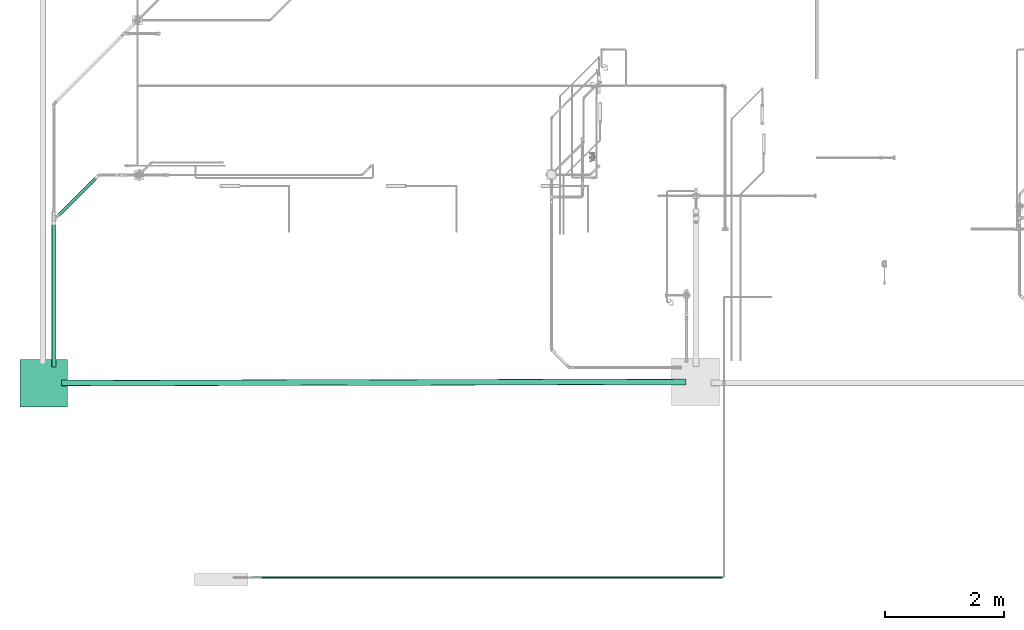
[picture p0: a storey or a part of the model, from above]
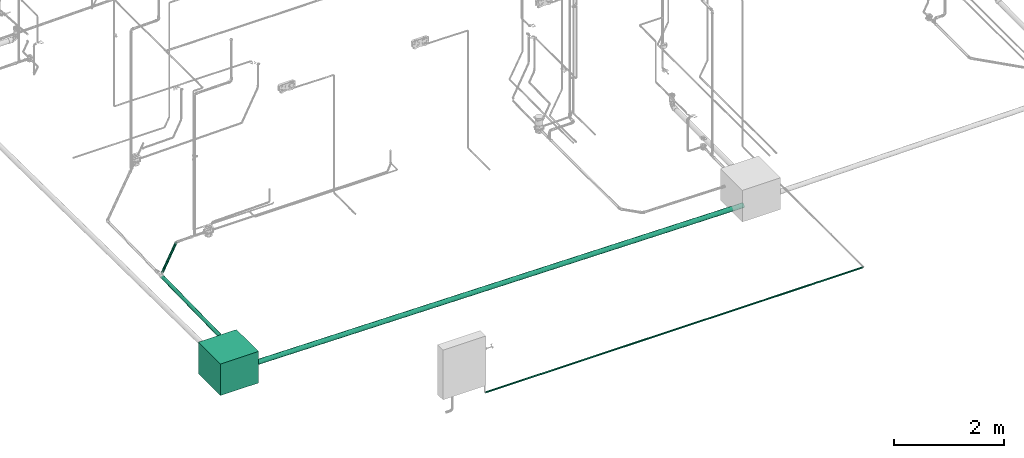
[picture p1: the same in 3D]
Properties of the parts of a building model (IFC2X3), part 1 of 4

# File
Description: ViewDefinition [CoordinationView_V2.0], RevitIdentifiers [VersionGUID: 1a3a2420-27dc-4e76-b48d-279fff6e6c55, NumberOfSaves: 164], CoordinateReference [CoordinateBase: Coordenadas compartilhadas]
File name: 14°43'43.87"S 56°20'14.91"O
Time: 2024-08-28T15:00:30-04:00
Written by: ODA SDAI 22.12
Made in: 23.1.20.70 - Exporter 23.2.5.0 - IU alternativa 23.2.5.0

# IfcProject, 14°43'43.87"S 56°20'14.91"O
LongName: CURSO PROJETO HIDROSSÁNITARIO RESIDENCIAL NO REVIT MEP; Phase: Project Status

# IfcSite, Default
RefLatitude: 42, 12, 46, 799999; RefLongitude: -71, -1, -58, -799999; RefElevation: 0 mm

# IfcBuilding
Pset_BuildingCommon - NumberOfStoreys: 2

# IfcBuildingStorey: Nível:Nivel Rodrigo MEP (2)
Name | LongName | Elevation (mm)
TÉRREO | TÉRREO | 100
DRENAGEM PLUVIAL - PLANTA DE COBERTURA | DRENAGEM PLUVIAL - PLANTA DE COBERTURA | 3200

# IfcBuildingElementProxy: Anel de Concreto Perfurado para Sumidouro_Rodrigo MEP:Anel de Concreto Perfurado para Sumidouro (4)
In: TÉRREO
Type - Material: .CONCRETO
Type - Pset_ManufacturerTypeInformation - Manufacturer: -
Pset_BuildingElementProxyCommon - Reference: Anel de Concreto Perfurado para Sumidouro; sets with these values: 2
Name (Anel de Concreto Perfurado para Sumidouro_Rodrigo MEP:Anel de Concreto Perfurado para Sumidouro:...)
7495602
7495603
7495605
7495606

# IfcBuildingElementProxy: Anel de Concreto para Fossa e Sumidouro_Rodrigo MEP:Anel de Concreto para Fossa e Sumidouro (7)
In: TÉRREO
Type - Material: .CONCRETO
Type - Pset_ManufacturerTypeInformation - Manufacturer: -
Pset_BuildingElementProxyCommon - Reference: Anel de Concreto para Fossa e Sumidouro; sets with these values: 2
Name (Anel de Concreto para Fossa e Sumidouro_Rodrigo MEP:Anel de Concreto para Fossa e Sumidouro:...)
7495571
7495572
7495577
7495578
7495588
7495589
7495593

# IfcBuildingElementProxy: Brita_Rodrigo MEP:Brita (2)
In: TÉRREO
Type - Material: Brita
Type - Pset_ManufacturerTypeInformation - Manufacturer: -
Pset_BuildingElementProxyCommon - Reference: Brita; sets with these values: 2
Name (Brita_Rodrigo MEP:Brita:...)
7495597
7495608

# IfcBuildingElementProxy: Laje de fundo para Fossa e Filtro Anaerobio_Rodrigo MEP:Laje de fundo para Fossa e Filtro Anaerobio (2)
In: TÉRREO
Type - Material: .CONCRETO
Type - Pset_ManufacturerTypeInformation - Manufacturer: -
Pset_BuildingElementProxyCommon - Reference: Laje de fundo para Fossa e Filtro Anaerobio; sets with these values: 2
Name (Laje de fundo para Fossa e Filtro Anaerobio_Rodrigo MEP:Laje de fundo para Fossa e Filtro Anaerobio:...)
7495576
7495592

# IfcBuildingElementProxy: Laje perfurada para Filtro Anaerobio_Rodrigo MEP:Laje perfurada para Filtro Anaerobio, Laje perfurada para Filtro Anaerobio_Rodrigo MEP:Laje perfurada para Filtro Anaerobio:7495595
In: TÉRREO
Type - Material: .CONCRETO
Type - Pset_ManufacturerTypeInformation - Manufacturer: -
Pset_BuildingElementProxyCommon - Reference: Laje perfurada para Filtro Anaerobio; sets with these values: 2

# IfcBuildingElementProxy: Tampa Fossa_Rodrigo MEP:Tampa Fossa (3)
In: TÉRREO
Type - Material: .CONCRETO
Type - Pset_ManufacturerTypeInformation - Manufacturer: -
Pset_BuildingElementProxyCommon - Reference: Tampa Fossa; sets with these values: 2
Name (Tampa Fossa_Rodrigo MEP:Tampa Fossa:...)
7495579
7495596
7495607

# IfcBuildingElementProxy: Tampa para Fossa, Filtro Anaerobio e Sumidouro_Rodrigo MEP:tampa para Fossa, Filtro Anaerobio e Sumidouro (3)
In: TÉRREO
Type - Material: .CONCRETO
Type - Pset_ManufacturerTypeInformation - Manufacturer: -
Pset_BuildingElementProxyCommon - Reference: tampa para Fossa, Filtro Anaerobio e Sumidouro; sets with these values: 2
Name (Tampa para Fossa, Filtro Anaerobio e Sumidouro_Rodrigo MEP:tampa para Fossa, Filtro Anaerobio e Sumidouro:...)
7495575
7495591
7495604

# IfcDistributionPort (2899)
Description: Flow
Name | FlowDirection | Group
Port_7029388_5 | SOURCEANDSINK | Esgoto Primário 7
InPort_7029716_0 | SINK | Esgoto Primário 7
OutPort_7029388_6 | SOURCE | Esgoto Primário 7
InPort_7029455_1 | SINK | Esgoto Primário 7
OutPort_7029509_1 | SOURCE | Esgoto Primário 7
InPort_7029455_2 | SINK
InPort_7029455_3 | SINK
InPort_7038227_0 | SINK | Esgoto Primário 8
OutPort_7029455_4 | SOURCE | Esgoto Primário 8
InPort_7029455_5 | SINK | Esgoto Primário 9
OutPort_7306475_0 | SOURCE | Esgoto Primário 9
InPort_7029509_0 | SINK | Esgoto Primário 7
OutPort_7029736_2 | SOURCE | Esgoto Primário 7
InPort_7029546_0 | SINK | Esgoto Primário 8
OutPort_7038226_1 | SOURCE | Esgoto Primário 8
OutPort_7029546_1 | SOURCE | Esgoto Primário 8
InPort_7029736_1 | SINK | Esgoto Primário 7
OutPort_7029716_1 | SOURCE | Esgoto Primário 7
InPort_7030112_0 | SINK | Esgoto Primário 10
OutPort_7029972_3 | SOURCE | Esgoto Primário 10
InPort_7030100_0 | SINK | Esgoto Primário 10
OutPort_7390308_2 | SOURCE | Esgoto Primário 10
OutPort_7030100_1 | SOURCE | Esgoto Primário 10
InPort_7390308_1 | SINK | Esgoto Primário 10
OutPort_7030112_1 | SOURCE | Esgoto Primário 10
InPort_7031165_1 | SINK | Água Fria - Extravasor e Limpeza 1
OutPort_7031441_1 | SOURCE | Água Fria - Extravasor e Limpeza 1
Port_7031165_2 | SOURCEANDSINK
InPort_7032074_1 | SINK | Água Fria - Extravasor e Limpeza 1
OutPort_7031418_0 | SOURCE | Água Fria - Extravasor e Limpeza 1
InPort_7031418_1 | SINK | Água Fria - Extravasor e Limpeza 1
OutPort_7031451_1 | SOURCE | Água Fria - Extravasor e Limpeza 1
InPort_7031441_2 | SINK | Água Fria - Extravasor e Limpeza 1
OutPort_7032081_0 | SOURCE | Água Fria - Extravasor e Limpeza 1
InPort_7031451_2 | SINK | Água Fria - Extravasor e Limpeza 1
OutPort_7031445_0 | SOURCE | Água Fria - Extravasor e Limpeza 1
InPort_7031445_1 | SINK | Água Fria - Extravasor e Limpeza 1
OutPort_7377898_1 | SOURCE | Água Fria - Extravasor e Limpeza 1
InPort_7031871_0 | SINK | Água Fria - Extravasor e Limpeza 1
OutPort_7377896_2 | SOURCE | Água Fria - Extravasor e Limpeza 1
InPort_7377898_2 | SINK | Água Fria - Extravasor e Limpeza 1
OutPort_7031871_1 | SOURCE | Água Fria - Extravasor e Limpeza 1
InPort_7032081_1 | SINK | Água Fria - Extravasor e Limpeza 1
OutPort_7032074_2 | SOURCE | Água Fria - Extravasor e Limpeza 1
InPort_7032948_1 | SINK | Água Fria - Extravasor e Limpeza 1
OutPort_7427211_1 | SOURCE | Água Fria - Extravasor e Limpeza 1
Port_7032948_2 | SOURCEANDSINK
InPort_7033167_1 | SINK | Água Fria - Extravasor e Limpeza 1
OutPort_7386636_0 | SOURCE | Água Fria - Extravasor e Limpeza 1
InPort_7033181_1 | SINK | Água Fria - Extravasor e Limpeza 1
OutPort_7033167_2 | SOURCE | Água Fria - Extravasor e Limpeza 1
InPort_7383525_1 | SINK | Água Fria - Extravasor e Limpeza 1
OutPort_7033181_0 | SOURCE | Água Fria - Extravasor e Limpeza 1
InPort_7293043_1 | SINK | Água Fria - Extravasor e Limpeza 1
OutPort_7033639_1 | SOURCE | Água Fria - Extravasor e Limpeza 1
InPort_7033639_2 | SINK | Água Fria - Extravasor e Limpeza 1
OutPort_7377745_0 | SOURCE | Água Fria - Extravasor e Limpeza 1
InPort_7033647_1 | SINK | Água Fria - Extravasor e Limpeza 1
OutPort_7386486_1 | SOURCE | Água Fria - Extravasor e Limpeza 1
InPort_7033652_1 | SINK | Água Fria - Extravasor e Limpeza 1
OutPort_7033647_2 | SOURCE | Água Fria - Extravasor e Limpeza 1
InPort_7377870_2 | SINK | Água Fria - Extravasor e Limpeza 1
OutPort_7033652_0 | SOURCE | Água Fria - Extravasor e Limpeza 1
InPort_7034796_1 | SINK | Água Fria - Extravasor e Limpeza 1
OutPort_7034971_1 | SOURCE | Água Fria - Extravasor e Limpeza 1
Port_7034796_2 | SOURCEANDSINK
InPort_7034971_2 | SINK | Água Fria - Extravasor e Limpeza 1
OutPort_7035195_0 | SOURCE | Água Fria - Extravasor e Limpeza 1
InPort_7035195_1 | SINK | Água Fria - Extravasor e Limpeza 1
OutPort_7377770_1 | SOURCE | Água Fria - Extravasor e Limpeza 1
InPort_7038217_0 | SINK | Esgoto - Ventilação 3
OutPort_7038239_2 | SOURCE | Esgoto - Ventilação 3
InPort_7038259_1 | SINK | Esgoto - Ventilação 3
OutPort_7038217_1 | SOURCE | Esgoto - Ventilação 3
InPort_7038226_2 | SINK | Esgoto Primário 8
OutPort_7038227_1 | SOURCE | Esgoto Primário 8
InPort_7038239_1 | SINK | Esgoto - Ventilação 3
OutPort_7038226_3 | SOURCE | Esgoto - Ventilação 3
OutPort_7038256_0 | SOURCE | Esgoto - Ventilação 3
InPort_7038256_1 | SINK | Esgoto - Ventilação 3
OutPort_7038259_2 | SOURCE | Esgoto - Ventilação 3
InPort_7435001_0 | SINK | Água Fria - Extravasor e Limpeza 1
OutPort_7132676_1 | SOURCE | Água Fria - Extravasor e Limpeza 1
InPort_7434857_0 | SINK | Água Fria - Extravasor e Limpeza 1
OutPort_7132676_2 | SOURCE | Água Fria - Extravasor e Limpeza 1
InPort_7389512_0 | SINK | Água Fria - Extravasor e Limpeza 2
OutPort_7132676_3 | SOURCE | Água Fria - Extravasor e Limpeza 2
InPort_7488134_0 | SINK | Água Fria - Extravasor e Limpeza 1
OutPort_7132676_4 | SOURCE | Água Fria - Extravasor e Limpeza 1
Port_7132676_5 | SOURCEANDSINK | Água Fria Alimentação 1
Port_7132676_6 | SOURCEANDSINK | Água Fria Alimentação 3
Port_7132676_7 | SOURCEANDSINK
Port_7132676_8 | SOURCEANDSINK
InPort_7435405_0 | SINK | Água Fria 9
OutPort_7133905_1 | SOURCE | Água Fria 9
InPort_7386144_1 | SINK | Água Fria 1
OutPort_7133905_2 | SOURCE | Água Fria 1
OutPort_7133905_3 | SOURCE | Água Fria - Extravasor e Limpeza 12
InPort_7389240_1 | SINK | Água Fria - Extravasor e Limpeza 2
OutPort_7133905_4 | SOURCE | Água Fria - Extravasor e Limpeza 2
Port_7133905_5 | SOURCEANDSINK | Água Fria - Extravasor e Limpeza 2
Port_7435984_0 | SOURCEANDSINK | Água Fria - Extravasor e Limpeza 2
Port_7133905_6 | SOURCEANDSINK | Água Fria Alimentação 4
InPort_7450968_0 | SINK | Água Fria - Extravasor e Limpeza 12
OutPort_7133905_7 | SOURCE | Água Fria - Extravasor e Limpeza 12
Port_7133905_8 | SOURCEANDSINK
InPort_7411687_0 | SINK | Esgoto Sanitário 72
OutPort_7182701_3 | SOURCE | Esgoto Sanitário 72
InPort_7182701_4 | SINK
InPort_7182701_5 | SINK
InPort_7182701_6 | SINK
InPort_7182701_7 | SINK
InPort_7182701_8 | SINK
InPort_7182701_9 | SINK
InPort_7182701_10 | SINK
InPort_7182701_11 | SINK
InPort_7182701_12 | SINK
InPort_7191995_0 | SINK | Água Pluvial 1
OutPort_7191267_1 | SOURCE | Água Pluvial 1
InPort_7192028_1 | SINK | Água Pluvial 1
OutPort_7191995_1 | SOURCE | Água Pluvial 1
InPort_7192022_0 | SINK | Água Pluvial 1
OutPort_7192028_2 | SOURCE | Água Pluvial 1
InPort_7192061_1 | SINK | Água Pluvial 1
OutPort_7192022_1 | SOURCE | Água Pluvial 1
InPort_7192041_0 | SINK | Água Pluvial 1
OutPort_7192061_2 | SOURCE | Água Pluvial 1
InPort_7192075_1 | SINK | Água Pluvial 1
OutPort_7192041_1 | SOURCE | Água Pluvial 1
OutPort_7192075_2 | SOURCE | Água Pluvial 1
Port_7293043_2 | SOURCEANDSINK
InPort_7306475_1 | SINK | Esgoto Primário 9
Port_7367177_0 | SOURCEANDSINK | Esgoto Primário 37
Port_7367177_1 | SOURCEANDSINK | Esgoto Primário 37
InPort_7377770_2 | SINK | Água Fria - Extravasor e Limpeza 1
OutPort_7377732_0 | SOURCE | Água Fria - Extravasor e Limpeza 1
InPort_7377732_1 | SINK | Água Fria - Extravasor e Limpeza 1
OutPort_7377744_3 | SOURCE | Água Fria - Extravasor e Limpeza 1
InPort_7377744_1 | SINK | Água Fria - Extravasor e Limpeza 1
OutPort_7377871_0 | SOURCE | Água Fria - Extravasor e Limpeza 1
InPort_7377745_1 | SINK | Água Fria - Extravasor e Limpeza 1
OutPort_7377744_2 | SOURCE | Água Fria - Extravasor e Limpeza 1
InPort_7377862_0 | SINK | Água Fria - Extravasor e Limpeza 1
OutPort_7377870_3 | SOURCE | Água Fria - Extravasor e Limpeza 1
InPort_7377896_1 | SINK | Água Fria - Extravasor e Limpeza 1
OutPort_7377862_1 | SOURCE | Água Fria - Extravasor e Limpeza 1
InPort_7377871_1 | SINK | Água Fria - Extravasor e Limpeza 1
OutPort_7377870_1 | SOURCE | Água Fria - Extravasor e Limpeza 1
InPort_7380749_1 | SINK | Água Fria - Extravasor e Limpeza 1
OutPort_7380714_1 | SOURCE | Água Fria - Extravasor e Limpeza 1
InPort_7380714_2 | SINK | Água Fria - Extravasor e Limpeza 1
OutPort_7380732_0 | SOURCE | Água Fria - Extravasor e Limpeza 1
InPort_7380722_1 | SINK | Água Fria - Extravasor e Limpeza 1
OutPort_7386044_1 | SOURCE | Água Fria - Extravasor e Limpeza 1
InPort_7380727_1 | SINK | Água Fria - Extravasor e Limpeza 1
OutPort_7380722_2 | SOURCE | Água Fria - Extravasor e Limpeza 1
InPort_7380731_1 | SINK | Água Fria - Extravasor e Limpeza 1
OutPort_7380727_0 | SOURCE | Água Fria - Extravasor e Limpeza 1
InPort_7380729_0 | SINK | Água Fria - Extravasor e Limpeza 1
OutPort_7380731_3 | SOURCE | Água Fria - Extravasor e Limpeza 1
InPort_7380745_2 | SINK | Água Fria - Extravasor e Limpeza 1
OutPort_7380729_1 | SOURCE | Água Fria - Extravasor e Limpeza 1
InPort_7380732_1 | SINK | Água Fria - Extravasor e Limpeza 1
OutPort_7380731_2 | SOURCE | Água Fria - Extravasor e Limpeza 1
InPort_7380735_0 | SINK | Água Fria - Extravasor e Limpeza 1
OutPort_7380743_1 | SOURCE | Água Fria - Extravasor e Limpeza 1
InPort_7380737_2 | SINK | Água Fria - Extravasor e Limpeza 1
OutPort_7380735_1 | SOURCE | Água Fria - Extravasor e Limpeza 1
InPort_7380750_1 | SINK | Água Fria - Extravasor e Limpeza 1
OutPort_7380737_1 | SOURCE | Água Fria - Extravasor e Limpeza 1
InPort_7380739_0 | SINK | Água Fria - Extravasor e Limpeza 1
OutPort_7380745_1 | SOURCE | Água Fria - Extravasor e Limpeza 1
InPort_7380747_2 | SINK | Água Fria - Extravasor e Limpeza 1
OutPort_7380739_1 | SOURCE | Água Fria - Extravasor e Limpeza 1
InPort_7380743_2 | SINK | Água Fria - Extravasor e Limpeza 1
OutPort_7380741_0 | SOURCE | Água Fria - Extravasor e Limpeza 1
InPort_7380741_1 | SINK | Água Fria - Extravasor e Limpeza 1
OutPort_7380747_1 | SOURCE | Água Fria - Extravasor e Limpeza 1
Port_7380749_2 | SOURCEANDSINK
Port_7380750_2 | SOURCEANDSINK
InPort_7380830_1 | SINK | Água Fria 1
OutPort_7380795_1 | SOURCE | Água Fria 1
InPort_7380795_2 | SINK | Água Fria 1
OutPort_7380813_0 | SOURCE | Água Fria 1
InPort_7380803_1 | SINK | Água Fria 1
OutPort_7386010_0 | SOURCE | Água Fria 1
InPort_7380808_1 | SINK | Água Fria 1
OutPort_7380803_2 | SOURCE | Água Fria 1
InPort_7380812_1 | SINK | Água Fria 1
OutPort_7380808_0 | SOURCE | Água Fria 1
InPort_7380810_0 | SINK | Água Fria 1
OutPort_7380812_3 | SOURCE | Água Fria 1
InPort_7380826_2 | SINK | Água Fria 1
OutPort_7380810_1 | SOURCE | Água Fria 1
InPort_7380813_1 | SINK | Água Fria 1
OutPort_7380812_2 | SOURCE | Água Fria 1
InPort_7380816_0 | SINK | Água Fria 1
OutPort_7380824_1 | SOURCE | Água Fria 1
InPort_7380818_2 | SINK | Água Fria 1
OutPort_7380816_1 | SOURCE | Água Fria 1
InPort_7380831_1 | SINK | Água Fria 1
OutPort_7380818_1 | SOURCE | Água Fria 1
InPort_7380820_0 | SINK | Água Fria 1
OutPort_7380826_1 | SOURCE | Água Fria 1
InPort_7380828_2 | SINK | Água Fria 1
OutPort_7380820_1 | SOURCE | Água Fria 1
InPort_7380824_2 | SINK | Água Fria 1
OutPort_7380822_0 | SOURCE | Água Fria 1
InPort_7380822_1 | SINK | Água Fria 1
OutPort_7380828_1 | SOURCE | Água Fria 1
Port_7380830_2 | SOURCEANDSINK
Port_7380831_2 | SOURCEANDSINK
InPort_7380996_1 | SINK | Água Fria 9
OutPort_7380961_1 | SOURCE | Água Fria 9
InPort_7380961_2 | SINK | Água Fria 9
OutPort_7380979_0 | SOURCE | Água Fria 9
InPort_7380969_1 | SINK | Água Fria 9
OutPort_7388749_0 | SOURCE | Água Fria 9
InPort_7380974_1 | SINK | Água Fria 9
OutPort_7380969_2 | SOURCE | Água Fria 9
InPort_7380978_1 | SINK | Água Fria 9
OutPort_7380974_0 | SOURCE | Água Fria 9
InPort_7380976_0 | SINK | Água Fria 9
OutPort_7380978_3 | SOURCE | Água Fria 9
InPort_7380992_2 | SINK | Água Fria 9
OutPort_7380976_1 | SOURCE | Água Fria 9
InPort_7380979_1 | SINK | Água Fria 9
OutPort_7380978_2 | SOURCE | Água Fria 9
InPort_7380982_0 | SINK | Água Fria 9
OutPort_7417016_1 | SOURCE | Água Fria 9
InPort_7380984_2 | SINK | Água Fria 9
OutPort_7380982_1 | SOURCE | Água Fria 9
InPort_7380997_1 | SINK | Água Fria 9
OutPort_7380984_1 | SOURCE | Água Fria 9
InPort_7380986_0 | SINK | Água Fria 9
OutPort_7380992_1 | SOURCE | Água Fria 9
InPort_7380994_2 | SINK | Água Fria 9
OutPort_7380986_1 | SOURCE | Água Fria 9
InPort_7380990_2 | SINK | Água Fria 9
OutPort_7380988_0 | SOURCE | Água Fria 9
InPort_7380988_1 | SINK | Água Fria 9
OutPort_7380994_1 | SOURCE | Água Fria 9
InPort_7417019_0 | SINK | Água Fria 9
OutPort_7380990_1 | SOURCE | Água Fria 9
Port_7380996_2 | SOURCEANDSINK
Port_7380997_2 | SOURCEANDSINK
InPort_7382155_1 | SINK | Água Fria - Extravasor e Limpeza 1
OutPort_7382259_1 | SOURCE | Água Fria - Extravasor e Limpeza 1
Port_7382155_2 | SOURCEANDSINK
InPort_7382259_2 | SINK | Água Fria - Extravasor e Limpeza 1
OutPort_7382245_0 | SOURCE | Água Fria - Extravasor e Limpeza 1
InPort_7382245_1 | SINK | Água Fria - Extravasor e Limpeza 1
OutPort_7388926_1 | SOURCE | Água Fria - Extravasor e Limpeza 1
InPort_7382303_1 | SINK | Água Fria - Extravasor e Limpeza 1
OutPort_7382351_1 | SOURCE | Água Fria - Extravasor e Limpeza 1
Port_7382303_2 | SOURCEANDSINK
InPort_7382351_2 | SINK | Água Fria - Extravasor e Limpeza 1
OutPort_7382432_0 | SOURCE | Água Fria - Extravasor e Limpeza 1
InPort_7382415_1 | SINK | Água Fria - Extravasor e Limpeza 1
OutPort_7387592_0 | SOURCE | Água Fria - Extravasor e Limpeza 1
InPort_7382432_1 | SINK | Água Fria - Extravasor e Limpeza 1
OutPort_7382415_2 | SOURCE | Água Fria - Extravasor e Limpeza 1
InPort_7382590_1 | SINK | Água Fria - Extravasor e Limpeza 1
OutPort_7382593_1 | SOURCE | Água Fria - Extravasor e Limpeza 1
Port_7382590_2 | SOURCEANDSINK
InPort_7382593_2 | SINK | Água Fria - Extravasor e Limpeza 1
OutPort_7382600_0 | SOURCE | Água Fria - Extravasor e Limpeza 1
InPort_7382595_1 | SINK | Água Fria - Extravasor e Limpeza 1
OutPort_7387844_0 | SOURCE | Água Fria - Extravasor e Limpeza 1
InPort_7382600_1 | SINK | Água Fria - Extravasor e Limpeza 1
OutPort_7382595_2 | SOURCE | Água Fria - Extravasor e Limpeza 1
InPort_7382800_1 | SINK | Água Fria - Extravasor e Limpeza 1
OutPort_7382840_1 | SOURCE | Água Fria - Extravasor e Limpeza 1
Port_7382800_2 | SOURCEANDSINK
InPort_7382981_1 | SINK | Água Fria - Extravasor e Limpeza 1
OutPort_7382826_0 | SOURCE | Água Fria - Extravasor e Limpeza 1
InPort_7382826_1 | SINK | Água Fria - Extravasor e Limpeza 1
OutPort_7389126_1 | SOURCE | Água Fria - Extravasor e Limpeza 1
InPort_7382840_2 | SINK | Água Fria - Extravasor e Limpeza 1
OutPort_7383059_0 | SOURCE | Água Fria - Extravasor e Limpeza 1
InPort_7382987_1 | SINK | Água Fria - Extravasor e Limpeza 1
OutPort_7382981_2 | SOURCE | Água Fria - Extravasor e Limpeza 1
InPort_7383058_1 | SINK | Água Fria - Extravasor e Limpeza 1
OutPort_7382987_0 | SOURCE | Água Fria - Extravasor e Limpeza 1
InPort_7383050_0 | SINK | Água Fria - Extravasor e Limpeza 1
OutPort_7383058_3 | SOURCE | Água Fria - Extravasor e Limpeza 1
InPort_7383086_2 | SINK | Água Fria - Extravasor e Limpeza 1
OutPort_7383050_1 | SOURCE | Água Fria - Extravasor e Limpeza 1
InPort_7383059_1 | SINK | Água Fria - Extravasor e Limpeza 1
OutPort_7383058_2 | SOURCE | Água Fria - Extravasor e Limpeza 1
InPort_7383078_0 | SINK | Água Fria - Extravasor e Limpeza 1
OutPort_7383086_1 | SOURCE | Água Fria - Extravasor e Limpeza 1
InPort_7383177_1 | SINK | Água Fria - Extravasor e Limpeza 1
OutPort_7383078_1 | SOURCE | Água Fria - Extravasor e Limpeza 1
InPort_7383169_0 | SINK | Água Fria - Extravasor e Limpeza 1
OutPort_7383177_2 | SOURCE | Água Fria - Extravasor e Limpeza 1
InPort_7383206_1 | SINK | Água Fria - Extravasor e Limpeza 1
OutPort_7383169_1 | SOURCE | Água Fria - Extravasor e Limpeza 1
InPort_7383223_1 | SINK | Água Fria - Extravasor e Limpeza 1
OutPort_7383206_2 | SOURCE | Água Fria - Extravasor e Limpeza 1
InPort_7383275_0 | SINK | Água Fria - Extravasor e Limpeza 1
OutPort_7383281_1 | SOURCE | Água Fria - Extravasor e Limpeza 1
InPort_7383277_2 | SINK | Água Fria - Extravasor e Limpeza 1
OutPort_7383275_1 | SOURCE | Água Fria - Extravasor e Limpeza 1
InPort_7383279_1 | SINK | Água Fria - Extravasor e Limpeza 1
OutPort_7383277_1 | SOURCE | Água Fria - Extravasor e Limpeza 1
Port_7383279_2 | SOURCEANDSINK
InPort_7383280_1 | SINK | Água Fria - Extravasor e Limpeza 1
OutPort_7383281_3 | SOURCE | Água Fria - Extravasor e Limpeza 1
Port_7383280_2 | SOURCEANDSINK
InPort_7383281_2 | SINK | Água Fria - Extravasor e Limpeza 1
OutPort_7383283_1 | SOURCE | Água Fria - Extravasor e Limpeza 1
InPort_7383283_0 | SINK | Água Fria - Extravasor e Limpeza 1
OutPort_7383294_2 | SOURCE | Água Fria - Extravasor e Limpeza 1
InPort_7383294_1 | SINK | Água Fria - Extravasor e Limpeza 1
OutPort_7383292_0 | SOURCE | Água Fria - Extravasor e Limpeza 1
InPort_7383292_1 | SINK | Água Fria - Extravasor e Limpeza 1
OutPort_7383564_1 | SOURCE | Água Fria - Extravasor e Limpeza 1
InPort_7427189_0 | SINK | Água Fria - Extravasor e Limpeza 1
OutPort_7383525_2 | SOURCE | Água Fria - Extravasor e Limpeza 1
InPort_7383542_0 | SINK | Água Fria - Extravasor e Limpeza 1
OutPort_7383525_3 | SOURCE | Água Fria - Extravasor e Limpeza 1
InPort_7383564_2 | SINK | Água Fria - Extravasor e Limpeza 1
OutPort_7383542_1 | SOURCE | Água Fria - Extravasor e Limpeza 1
InPort_7383580_1 | SINK | Água Fria - Extravasor e Limpeza 1
OutPort_7383583_1 | SOURCE | Água Fria - Extravasor e Limpeza 1
Port_7383580_2 | SOURCEANDSINK
InPort_7383583_2 | SINK | Água Fria - Extravasor e Limpeza 1
OutPort_7383590_0 | SOURCE | Água Fria - Extravasor e Limpeza 1
InPort_7383585_1 | SINK | Água Fria - Extravasor e Limpeza 1
OutPort_7389001_0 | SOURCE | Água Fria - Extravasor e Limpeza 1
InPort_7383590_1 | SINK | Água Fria - Extravasor e Limpeza 1
OutPort_7383585_2 | SOURCE | Água Fria - Extravasor e Limpeza 1
InPort_7383633_1 | SINK | Água Fria - Extravasor e Limpeza 1
OutPort_7383636_1 | SOURCE | Água Fria - Extravasor e Limpeza 1
Port_7383633_2 | SOURCEANDSINK
InPort_7383638_1 | SINK | Água Fria - Extravasor e Limpeza 1
OutPort_7383634_0 | SOURCE | Água Fria - Extravasor e Limpeza 1
InPort_7383634_1 | SINK | Água Fria - Extravasor e Limpeza 1
OutPort_7388879_1 | SOURCE | Água Fria - Extravasor e Limpeza 1
InPort_7383636_2 | SINK | Água Fria - Extravasor e Limpeza 1
OutPort_7383643_0 | SOURCE | Água Fria - Extravasor e Limpeza 1
InPort_7383643_1 | SINK | Água Fria - Extravasor e Limpeza 1
OutPort_7383638_2 | SOURCE | Água Fria - Extravasor e Limpeza 1
InPort_7383758_0 | SINK | Água Fria 9
OutPort_7383764_1 | SOURCE | Água Fria 9
InPort_7383760_2 | SINK | Água Fria 9
OutPort_7383758_1 | SOURCE | Água Fria 9
InPort_7383762_1 | SINK | Água Fria 9
OutPort_7383760_1 | SOURCE | Água Fria 9
Port_7383762_2 | SOURCEANDSINK
InPort_7383763_1 | SINK | Água Fria 9
OutPort_7383764_3 | SOURCE | Água Fria 9
Port_7383763_2 | SOURCEANDSINK
InPort_7383764_2 | SINK | Água Fria 9
OutPort_7383766_1 | SOURCE | Água Fria 9
InPort_7383766_0 | SINK | Água Fria 9
OutPort_7383777_2 | SOURCE | Água Fria 9
InPort_7383770_1 | SINK | Água Fria 9
OutPort_7383768_0 | SOURCE | Água Fria 9
InPort_7383768_1 | SINK | Água Fria 9
OutPort_7389791_1 | SOURCE | Água Fria 9
InPort_7383775_1 | SINK | Água Fria 9
OutPort_7383770_2 | SOURCE | Água Fria 9
InPort_7383777_1 | SINK | Água Fria 9
OutPort_7383775_0 | SOURCE | Água Fria 9
Port_7383818_0 | SOURCEANDSINK | Água Fria 9
Port_7383921_1 | SOURCEANDSINK | Água Fria 9
Port_7383818_1 | SOURCEANDSINK | Água Fria 9
Port_7501636_1 | SOURCEANDSINK | Água Fria 9
Port_7383921_2 | SOURCEANDSINK | Água Fria 9
Port_7383927_0 | SOURCEANDSINK | Água Fria 9
Port_7383927_1 | SOURCEANDSINK | Água Fria 9
Port_7492597_1 | SOURCEANDSINK | Água Fria 9
Port_7384061_0 | SOURCEANDSINK | Água Fria 9
Port_7501647_2 | SOURCEANDSINK | Água Fria 9
Port_7384061_1 | SOURCEANDSINK | Água Fria 9
Port_7384180_1 | SOURCEANDSINK | Água Fria 9
Port_7384077_1 | SOURCEANDSINK | Água Fria 9
Port_7384181_0 | SOURCEANDSINK | Água Fria 9
Port_7384077_2 | SOURCEANDSINK | Água Fria 9
Port_7384169_0 | SOURCEANDSINK | Água Fria 9
Port_7384180_3 | SOURCEANDSINK | Água Fria 9
Port_7384169_1 | SOURCEANDSINK | Água Fria 9
Port_7384190_1 | SOURCEANDSINK | Água Fria 9
Port_7384180_2 | SOURCEANDSINK | Água Fria 9
Port_7384181_1 | SOURCEANDSINK | Água Fria 9
Port_7384184_0 | SOURCEANDSINK | Água Fria 9
Port_7384190_2 | SOURCEANDSINK | Água Fria 9
Port_7384184_1 | SOURCEANDSINK | Água Fria 9
Port_7384202_1 | SOURCEANDSINK | Água Fria 9
Port_7384192_0 | SOURCEANDSINK | Água Fria 9
Port_7384202_2 | SOURCEANDSINK | Água Fria 9
Port_7384192_1 | SOURCEANDSINK | Água Fria 9
Port_7384294_1 | SOURCEANDSINK | Água Fria 9
Port_7384294_2 | SOURCEANDSINK | Água Fria 9
InPort_7384374_0 | SINK | Água Fria 9
OutPort_7384380_1 | SOURCE | Água Fria 9
InPort_7384376_2 | SINK | Água Fria 9
OutPort_7384374_1 | SOURCE | Água Fria 9
InPort_7384378_1 | SINK | Água Fria 9
OutPort_7384376_1 | SOURCE | Água Fria 9
Port_7384378_2 | SOURCEANDSINK
InPort_7384379_1 | SINK | Água Fria 9
OutPort_7384380_3 | SOURCE | Água Fria 9
Port_7384379_2 | SOURCEANDSINK
InPort_7384380_2 | SINK | Água Fria 9
OutPort_7384382_1 | SOURCE | Água Fria 9
InPort_7384382_0 | SINK | Água Fria 9
OutPort_7384393_2 | SOURCE | Água Fria 9
InPort_7384386_1 | SINK | Água Fria 9
OutPort_7384384_0 | SOURCE | Água Fria 9
InPort_7384384_1 | SINK | Água Fria 9
OutPort_7388571_1 | SOURCE | Água Fria 9
InPort_7384391_1 | SINK | Água Fria 9
OutPort_7384386_2 | SOURCE | Água Fria 9
InPort_7384393_1 | SINK | Água Fria 9
OutPort_7384391_0 | SOURCE | Água Fria 9
InPort_7384567_1 | SINK | Água Fria 9
OutPort_7384610_2 | SOURCE | Água Fria 9
Port_7384567_2 | SOURCEANDSINK
InPort_7384610_1 | SINK | Água Fria 9
OutPort_7384607_0 | SOURCE | Água Fria 9
InPort_7384607_1 | SINK | Água Fria 9
OutPort_7384639_1 | SOURCE | Água Fria 9
InPort_7384782_1 | SINK | Água Fria 9
OutPort_7384636_0 | SOURCE | Água Fria 9
InPort_7384636_1 | SINK | Água Fria 9
OutPort_7388602_1 | SOURCE | Água Fria 9
InPort_7384639_2 | SINK | Água Fria 9
OutPort_7384799_0 | SOURCE | Água Fria 9
InPort_7384799_1 | SINK | Água Fria 9
OutPort_7384782_2 | SOURCE | Água Fria 9
InPort_7385013_1 | SINK | Água Fria 1
OutPort_7385016_1 | SOURCE | Água Fria 1
Port_7385013_2 | SOURCEANDSINK
InPort_7385018_1 | SINK | Água Fria 1
OutPort_7385014_0 | SOURCE | Água Fria 1
InPort_7385014_1 | SINK | Água Fria 1
OutPort_7486918_1 | SOURCE | Água Fria 1
InPort_7385016_2 | SINK | Água Fria 1
OutPort_7385023_0 | SOURCE | Água Fria 1
InPort_7385023_1 | SINK | Água Fria 1
OutPort_7385018_2 | SOURCE | Água Fria 1
InPort_7385173_1 | SINK | Água Fria 1
OutPort_7385176_2 | SOURCE | Água Fria 1
Port_7385173_2 | SOURCEANDSINK
InPort_7385176_1 | SINK | Água Fria 1
OutPort_7385174_0 | SOURCE | Água Fria 1
InPort_7385174_1 | SINK | Água Fria 1
OutPort_7385180_1 | SOURCE | Água Fria 1
InPort_7385182_1 | SINK | Água Fria 1
OutPort_7385178_0 | SOURCE | Água Fria 1
InPort_7385178_1 | SINK | Água Fria 1
OutPort_7486926_1 | SOURCE | Água Fria 1
InPort_7385180_2 | SINK | Água Fria 1
OutPort_7385187_0 | SOURCE | Água Fria 1
InPort_7385187_1 | SINK | Água Fria 1
OutPort_7385182_2 | SOURCE | Água Fria 1
InPort_7385301_1 | SINK | Água Fria - Extravasor e Limpeza 1
OutPort_7385315_1 | SOURCE | Água Fria - Extravasor e Limpeza 1
Port_7385301_2 | SOURCEANDSINK
InPort_7385302_0 | SINK | Água Fria - Extravasor e Limpeza 1
OutPort_7385313_2 | SOURCE | Água Fria - Extravasor e Limpeza 1
InPort_7385315_2 | SINK | Água Fria - Extravasor e Limpeza 1
OutPort_7385302_1 | SOURCE | Água Fria - Extravasor e Limpeza 1
InPort_7385306_1 | SINK | Água Fria - Extravasor e Limpeza 1
OutPort_7385304_0 | SOURCE | Água Fria - Extravasor e Limpeza 1
InPort_7385304_1 | SINK | Água Fria - Extravasor e Limpeza 1
OutPort_7387908_1 | SOURCE | Água Fria - Extravasor e Limpeza 1
InPort_7385311_1 | SINK | Água Fria - Extravasor e Limpeza 1
OutPort_7385306_2 | SOURCE | Água Fria - Extravasor e Limpeza 1
InPort_7385313_1 | SINK | Água Fria - Extravasor e Limpeza 1
OutPort_7385311_0 | SOURCE | Água Fria - Extravasor e Limpeza 1
InPort_7385352_1 | SINK | Água Fria 1
OutPort_7385403_1 | SOURCE | Água Fria 1
Port_7385352_2 | SOURCEANDSINK
InPort_7432426_1 | SINK | Água Fria 1
OutPort_7385389_0 | SOURCE | Água Fria 1
InPort_7385389_1 | SINK | Água Fria 1
OutPort_7388818_1 | SOURCE | Água Fria 1
InPort_7385403_2 | SINK | Água Fria 1
OutPort_7432432_0 | SOURCE | Água Fria 1
InPort_7385497_1 | SINK | Água Fria - Extravasor e Limpeza 1
OutPort_7385482_1 | SOURCE | Água Fria - Extravasor e Limpeza 1
InPort_7385482_2 | SINK | Água Fria - Extravasor e Limpeza 1
OutPort_7385501_0 | SOURCE | Água Fria - Extravasor e Limpeza 1
InPort_7385492_1 | SINK | Água Fria - Extravasor e Limpeza 1
OutPort_7385493_1 | SOURCE | Água Fria - Extravasor e Limpeza 1
Port_7385492_2 | SOURCEANDSINK
InPort_7385493_2 | SINK | Água Fria - Extravasor e Limpeza 1
OutPort_7385495_0 | SOURCE | Água Fria - Extravasor e Limpeza 1
InPort_7385495_1 | SINK | Água Fria - Extravasor e Limpeza 1
OutPort_7385504_1 | SOURCE | Água Fria - Extravasor e Limpeza 1
Port_7385497_2 | SOURCEANDSINK
InPort_7416091_1 | SINK | Água Fria - Extravasor e Limpeza 1
OutPort_7385498_0 | SOURCE | Água Fria - Extravasor e Limpeza 1
InPort_7385498_1 | SINK | Água Fria - Extravasor e Limpeza 1
OutPort_7385500_3 | SOURCE | Água Fria - Extravasor e Limpeza 1
InPort_7385500_1 | SINK | Água Fria - Extravasor e Limpeza 1
OutPort_7429220_0 | SOURCE | Água Fria - Extravasor e Limpeza 1
InPort_7385501_1 | SINK | Água Fria - Extravasor e Limpeza 1
OutPort_7385500_2 | SOURCE | Água Fria - Extravasor e Limpeza 1
InPort_7385504_2 | SINK | Água Fria - Extravasor e Limpeza 1
OutPort_7416094_0 | SOURCE | Água Fria - Extravasor e Limpeza 1
InPort_7385545_1 | SINK | Água Fria - Extravasor e Limpeza 1
OutPort_7385548_1 | SOURCE | Água Fria - Extravasor e Limpeza 1
Port_7385545_2 | SOURCEANDSINK
InPort_7385562_1 | SINK | Água Fria - Extravasor e Limpeza 1
OutPort_7385546_0 | SOURCE | Água Fria - Extravasor e Limpeza 1
InPort_7385546_1 | SINK | Água Fria - Extravasor e Limpeza 1
OutPort_7385551_1 | SOURCE | Água Fria - Extravasor e Limpeza 1
InPort_7385548_2 | SINK | Água Fria - Extravasor e Limpeza 1
OutPort_7385567_0 | SOURCE | Água Fria - Extravasor e Limpeza 1
InPort_7385551_2 | SINK | Água Fria - Extravasor e Limpeza 1
OutPort_7385549_0 | SOURCE | Água Fria - Extravasor e Limpeza 1
InPort_7385549_1 | SINK | Água Fria - Extravasor e Limpeza 1
OutPort_7385554_1 | SOURCE | Água Fria - Extravasor e Limpeza 1
InPort_7385554_2 | SINK | Água Fria - Extravasor e Limpeza 1
OutPort_7385560_0 | SOURCE | Água Fria - Extravasor e Limpeza 1
InPort_7385555_1 | SINK | Água Fria - Extravasor e Limpeza 1
OutPort_7387007_0 | SOURCE | Água Fria - Extravasor e Limpeza 1
InPort_7385560_1 | SINK | Água Fria - Extravasor e Limpeza 1
OutPort_7385555_2 | SOURCE | Água Fria - Extravasor e Limpeza 1
InPort_7385567_1 | SINK | Água Fria - Extravasor e Limpeza 1
OutPort_7385562_2 | SOURCE | Água Fria - Extravasor e Limpeza 1
InPort_7388945_2 | SINK | Água Fria - Extravasor e Limpeza 1
OutPort_7385954_0 | SOURCE | Água Fria - Extravasor e Limpeza 1
InPort_7385954_1 | SINK | Água Fria - Extravasor e Limpeza 1
OutPort_7487359_1 | SOURCE | Água Fria - Extravasor e Limpeza 1
InPort_7386010_1 | SINK | Água Fria 1
OutPort_7387137_1 | SOURCE | Água Fria 1
InPort_7386044_0 | SINK | Água Fria - Extravasor e Limpeza 1
OutPort_7388945_1 | SOURCE | Água Fria - Extravasor e Limpeza 1
InPort_7435461_1 | SINK | Água Fria 1
OutPort_7386144_0 | SOURCE | Água Fria 1
InPort_7386152_0 | SINK | Água Fria 1
OutPort_7386160_2 | SOURCE | Água Fria 1
InPort_7386168_1 | SINK | Água Fria 1
OutPort_7386152_1 | SOURCE | Água Fria 1
InPort_7386160_1 | SINK | Água Fria 1
OutPort_7435463_0 | SOURCE | Água Fria 1
InPort_7388803_0 | SINK | Água Fria 1
OutPort_7386168_2 | SOURCE | Água Fria 1
InPort_7386232_0 | SINK | Água Fria - Extravasor e Limpeza 1
OutPort_7434855_1 | SOURCE | Água Fria - Extravasor e Limpeza 1
InPort_7493223_1 | SINK | Água Fria - Extravasor e Limpeza 1
OutPort_7386232_1 | SOURCE | Água Fria - Extravasor e Limpeza 1
InPort_7386320_0 | SINK | Água Fria - Extravasor e Limpeza 1
OutPort_7487381_2 | SOURCE | Água Fria - Extravasor e Limpeza 1
InPort_7388843_1 | SINK | Água Fria - Extravasor e Limpeza 1
OutPort_7386320_1 | SOURCE | Água Fria - Extravasor e Limpeza 1
InPort_7387137_2 | SINK | Água Fria 1
OutPort_7386331_0 | SOURCE | Água Fria 1
InPort_7386331_1 | SINK | Água Fria 1
OutPort_7387979_2 | SOURCE | Água Fria 1
InPort_7386461_0 | SINK | Água Fria - Extravasor e Limpeza 1
OutPort_7389058_1 | SOURCE | Água Fria - Extravasor e Limpeza 1
InPort_7386593_1 | SINK | Água Fria - Extravasor e Limpeza 1
OutPort_7386461_1 | SOURCE | Água Fria - Extravasor e Limpeza 1
InPort_7386510_1 | SINK | Água Fria - Extravasor e Limpeza 1
OutPort_7386471_0 | SOURCE | Água Fria - Extravasor e Limpeza 1
InPort_7386471_1 | SINK | Água Fria - Extravasor e Limpeza 1
OutPort_7386593_2 | SOURCE | Água Fria - Extravasor e Limpeza 1
InPort_7386486_0 | SINK | Água Fria - Extravasor e Limpeza 1
OutPort_7389983_2 | SOURCE | Água Fria - Extravasor e Limpeza 1
InPort_7389983_1 | SINK | Água Fria - Extravasor e Limpeza 1
OutPort_7386510_2 | SOURCE | Água Fria - Extravasor e Limpeza 1
InPort_7386565_0 | SINK | Água Fria - Extravasor e Limpeza 1
OutPort_7386614_2 | SOURCE | Água Fria - Extravasor e Limpeza 1
InPort_7389058_3 | SINK | Água Fria - Extravasor e Limpeza 1
OutPort_7386565_1 | SOURCE | Água Fria - Extravasor e Limpeza 1
InPort_7386604_0 | SINK | Água Fria - Extravasor e Limpeza 1
OutPort_7388966_2 | SOURCE | Água Fria - Extravasor e Limpeza 1
InPort_7386743_2 | SINK | Água Fria - Extravasor e Limpeza 1
OutPort_7386604_1 | SOURCE | Água Fria - Extravasor e Limpeza 1
InPort_7386614_1 | SINK | Água Fria - Extravasor e Limpeza 1
OutPort_7386615_1 | SOURCE | Água Fria - Extravasor e Limpeza 1
InPort_7388967_0 | SINK | Água Fria - Extravasor e Limpeza 1
OutPort_7386614_3 | SOURCE | Água Fria - Extravasor e Limpeza 1
InPort_7386615_0 | SINK | Água Fria - Extravasor e Limpeza 1
OutPort_7387822_2 | SOURCE | Água Fria - Extravasor e Limpeza 1
InPort_7386739_2 | SINK | Água Fria - Extravasor e Limpeza 1
OutPort_7386620_0 | SOURCE | Água Fria - Extravasor e Limpeza 1
InPort_7386620_1 | SINK | Água Fria - Extravasor e Limpeza 1
OutPort_7389902_2 | SOURCE | Água Fria - Extravasor e Limpeza 1
InPort_7386636_1 | SINK | Água Fria - Extravasor e Limpeza 1
OutPort_7386739_1 | SOURCE | Água Fria - Extravasor e Limpeza 1
InPort_7389902_1 | SINK | Água Fria - Extravasor e Limpeza 1
OutPort_7386743_1 | SOURCE | Água Fria - Extravasor e Limpeza 1
InPort_7386789_0 | SINK | Água Fria - Extravasor e Limpeza 1
OutPort_7434999_1 | SOURCE | Água Fria - Extravasor e Limpeza 1
InPort_7386806_1 | SINK | Água Fria - Extravasor e Limpeza 1
OutPort_7386789_1 | SOURCE | Água Fria - Extravasor e Limpeza 1
InPort_7386798_0 | SINK | Água Fria - Extravasor e Limpeza 1
OutPort_7386806_2 | SOURCE | Água Fria - Extravasor e Limpeza 1
InPort_7486542_1 | SINK | Água Fria - Extravasor e Limpeza 1
OutPort_7386798_1 | SOURCE | Água Fria - Extravasor e Limpeza 1
InPort_7386968_0 | SINK | Água Fria - Extravasor e Limpeza 1
OutPort_7386976_3 | SOURCE | Água Fria - Extravasor e Limpeza 1
InPort_7387075_1 | SINK | Água Fria - Extravasor e Limpeza 1
OutPort_7386968_1 | SOURCE | Água Fria - Extravasor e Limpeza 1
InPort_7386976_1 | SINK | Água Fria - Extravasor e Limpeza 1
OutPort_7452819_0 | SOURCE | Água Fria - Extravasor e Limpeza 1
InPort_7386977_1 | SINK | Água Fria - Extravasor e Limpeza 1
OutPort_7386976_2 | SOURCE | Água Fria - Extravasor e Limpeza 1
InPort_7389700_1 | SINK | Água Fria - Extravasor e Limpeza 1
OutPort_7386977_0 | SOURCE | Água Fria - Extravasor e Limpeza 1
InPort_7387071_2 | SINK | Água Fria - Extravasor e Limpeza 1
OutPort_7386985_0 | SOURCE | Água Fria - Extravasor e Limpeza 1
InPort_7386985_1 | SINK | Água Fria - Extravasor e Limpeza 1
OutPort_7387085_2 | SOURCE | Água Fria - Extravasor e Limpeza 1
InPort_7387007_1 | SINK | Água Fria - Extravasor e Limpeza 1
OutPort_7387071_1 | SOURCE | Água Fria - Extravasor e Limpeza 1
InPort_7387085_1 | SINK | Água Fria - Extravasor e Limpeza 1
OutPort_7387075_2 | SOURCE | Água Fria - Extravasor e Limpeza 1
InPort_7387144_0 | SINK | Água Fria 1
OutPort_7388802_2 | SOURCE | Água Fria 1
InPort_7387979_1 | SINK | Água Fria 1
OutPort_7387144_1 | SOURCE | Água Fria 1
InPort_7387386_0 | SINK | Água Fria 1
OutPort_7486914_1 | SOURCE | Água Fria 1
InPort_7486926_2 | SINK | Água Fria 1
OutPort_7387386_1 | SOURCE | Água Fria 1
InPort_7388926_2 | SINK | Água Fria - Extravasor e Limpeza 1
OutPort_7387515_0 | SOURCE | Água Fria - Extravasor e Limpeza 1
InPort_7387515_1 | SINK | Água Fria - Extravasor e Limpeza 1
OutPort_7388920_3 | SOURCE | Água Fria - Extravasor e Limpeza 1
InPort_7487181_1 | SINK | Água Fria - Extravasor e Limpeza 1
OutPort_7387569_0 | SOURCE | Água Fria - Extravasor e Limpeza 1
InPort_7387569_1 | SINK | Água Fria - Extravasor e Limpeza 1
OutPort_7486542_2 | SOURCE | Água Fria - Extravasor e Limpeza 1
InPort_7387592_1 | SINK | Água Fria - Extravasor e Limpeza 1
OutPort_7487477_2 | SOURCE | Água Fria - Extravasor e Limpeza 1
InPort_7387812_0 | SINK | Água Fria - Extravasor e Limpeza 1
OutPort_7387822_3 | SOURCE | Água Fria - Extravasor e Limpeza 1
InPort_7387855_2 | SINK | Água Fria - Extravasor e Limpeza 1
OutPort_7387812_1 | SOURCE | Água Fria - Extravasor e Limpeza 1
InPort_7387822_1 | SINK | Água Fria - Extravasor e Limpeza 1
OutPort_7487182_0 | SOURCE | Água Fria - Extravasor e Limpeza 1
InPort_7387851_2 | SINK | Água Fria - Extravasor e Limpeza 1
OutPort_7387830_0 | SOURCE | Água Fria - Extravasor e Limpeza 1
InPort_7387830_1 | SINK | Água Fria - Extravasor e Limpeza 1
OutPort_7387855_1 | SOURCE | Água Fria - Extravasor e Limpeza 1
InPort_7387844_1 | SINK | Água Fria - Extravasor e Limpeza 1
OutPort_7387851_1 | SOURCE | Água Fria - Extravasor e Limpeza 1
InPort_7387875_0 | SINK | Água Fria - Extravasor e Limpeza 1
OutPort_7387883_3 | SOURCE | Água Fria - Extravasor e Limpeza 1
InPort_7387897_1 | SINK | Água Fria - Extravasor e Limpeza 1
OutPort_7387875_1 | SOURCE | Água Fria - Extravasor e Limpeza 1
InPort_7387883_1 | SINK | Água Fria - Extravasor e Limpeza 1
OutPort_7486484_0 | SOURCE | Água Fria - Extravasor e Limpeza 1
Port_7387883_2 | SOURCEANDSINK | Água Fria - Extravasor e Limpeza 1
Port_7387884_1 | SOURCEANDSINK | Água Fria - Extravasor e Limpeza 1
Port_7387884_0 | SOURCEANDSINK | Água Fria - Extravasor e Limpeza 1
Port_7452818_1 | SOURCEANDSINK | Água Fria - Extravasor e Limpeza 1
InPort_7387891_0 | SINK | Água Fria - Extravasor e Limpeza 1
OutPort_7387897_2 | SOURCE | Água Fria - Extravasor e Limpeza 1
InPort_7387912_2 | SINK | Água Fria - Extravasor e Limpeza 1
OutPort_7387891_1 | SOURCE | Água Fria - Extravasor e Limpeza 1
InPort_7387908_2 | SINK | Água Fria - Extravasor e Limpeza 1
OutPort_7387900_0 | SOURCE | Água Fria - Extravasor e Limpeza 1
InPort_7387900_1 | SINK | Água Fria - Extravasor e Limpeza 1
OutPort_7387912_1 | SOURCE | Água Fria - Extravasor e Limpeza 1
Port_7388152_0 | SOURCEANDSINK | Água Fria 9
Port_7492559_3 | SOURCEANDSINK | Água Fria 9
Port_7388152_1 | SOURCEANDSINK | Água Fria 9
Port_7388553_2 | SOURCEANDSINK | Água Fria 9
InPort_7388208_0 | SINK | Água Fria 9
OutPort_7492646_2 | SOURCE | Água Fria 9
InPort_7389791_2 | SINK | Água Fria 9
OutPort_7388208_1 | SOURCE | Água Fria 9
Port_7388444_0 | SOURCEANDSINK | Água Fria 9
Port_7492595_1 | SOURCEANDSINK | Água Fria 9
Port_7388444_1 | SOURCEANDSINK | Água Fria 9
Port_7492597_2 | SOURCEANDSINK | Água Fria 9
InPort_7388538_0 | SINK | Água Fria 9
OutPort_7388553_3 | SOURCE | Água Fria 9
InPort_7388575_1 | SINK | Água Fria 9
OutPort_7388538_1 | SOURCE | Água Fria 9
Port_7388553_1 | SOURCEANDSINK | Água Fria 9
Port_7388554_1 | SOURCEANDSINK | Água Fria 9
Port_7388554_0 | SOURCEANDSINK | Água Fria 9
Port_7388586_2 | SOURCEANDSINK | Água Fria 9
InPort_7388571_2 | SINK | Água Fria 9
OutPort_7388561_0 | SOURCE | Água Fria 9
InPort_7388561_1 | SINK | Água Fria 9
OutPort_7388575_2 | SOURCE | Água Fria 9
InPort_7388578_0 | SINK | Água Fria 9
OutPort_7388586_3 | SOURCE | Água Fria 9
InPort_7388606_1 | SINK | Água Fria 9
OutPort_7388578_1 | SOURCE | Água Fria 9
Port_7388586_1 | SOURCEANDSINK | Água Fria 9
Port_7486633_0 | SOURCEANDSINK | Água Fria 9
InPort_7388602_2 | SINK | Água Fria 9
OutPort_7388594_0 | SOURCE | Água Fria 9
InPort_7388594_1 | SINK | Água Fria 9
OutPort_7388606_2 | SOURCE | Água Fria 9
InPort_7388662_0 | SINK | Água Fria 9
OutPort_7435403_1 | SOURCE | Água Fria 9
InPort_7388678_1 | SINK | Água Fria 9
OutPort_7388662_1 | SOURCE | Água Fria 9
InPort_7388670_0 | SINK | Água Fria 9
OutPort_7388678_2 | SOURCE | Água Fria 9
InPort_7388686_1 | SINK | Água Fria 9
OutPort_7388670_1 | SOURCE | Água Fria 9
InPort_7388680_0 | SINK | Água Fria 9
OutPort_7486627_2 | SOURCE | Água Fria 9
InPort_7388761_2 | SINK | Água Fria 9
OutPort_7388680_1 | SOURCE | Água Fria 9
InPort_7486628_0 | SINK | Água Fria 9
OutPort_7388686_2 | SOURCE | Água Fria 9
InPort_7388757_2 | SINK | Água Fria 9
OutPort_7388738_0 | SOURCE | Água Fria 9
InPort_7388738_1 | SINK | Água Fria 9
OutPort_7388761_1 | SOURCE | Água Fria 9
InPort_7388749_1 | SINK | Água Fria 9
OutPort_7388757_1 | SOURCE | Água Fria 9
InPort_7388794_0 | SINK | Água Fria 1
OutPort_7388802_3 | SOURCE | Água Fria 1
InPort_7486852_1 | SINK | Água Fria 1
OutPort_7388794_1 | SOURCE | Água Fria 1
InPort_7388802_1 | SINK | Água Fria 1
OutPort_7388803_1 | SOURCE | Água Fria 1
InPort_7388818_2 | SINK | Água Fria 1
OutPort_7388810_0 | SOURCE | Água Fria 1
InPort_7388810_1 | SINK | Água Fria 1
OutPort_7486852_3 | SOURCE | Água Fria 1
InPort_7388835_0 | SINK | Água Fria - Extravasor e Limpeza 1
OutPort_7388920_2 | SOURCE | Água Fria - Extravasor e Limpeza 1
InPort_7509194_1 | SINK | Água Fria - Extravasor e Limpeza 1
OutPort_7388835_1 | SOURCE | Água Fria - Extravasor e Limpeza 1
InPort_7487359_2 | SINK | Água Fria - Extravasor e Limpeza 1
OutPort_7388843_2 | SOURCE | Água Fria - Extravasor e Limpeza 1
InPort_7501685_0 | SINK | Água Fria - Extravasor e Limpeza 1
OutPort_7388843_3 | SOURCE | Água Fria - Extravasor e Limpeza 1
InPort_7388879_2 | SINK | Água Fria - Extravasor e Limpeza 1
OutPort_7388869_0 | SOURCE | Água Fria - Extravasor e Limpeza 1
InPort_7388869_1 | SINK | Água Fria - Extravasor e Limpeza 1
OutPort_7509194_3 | SOURCE | Água Fria - Extravasor e Limpeza 1
InPort_7388920_1 | SINK | Água Fria - Extravasor e Limpeza 1
OutPort_7501697_0 | SOURCE | Água Fria - Extravasor e Limpeza 1
InPort_7388958_0 | SINK | Água Fria - Extravasor e Limpeza 1
OutPort_7388966_3 | SOURCE | Água Fria - Extravasor e Limpeza 1
InPort_7389049_1 | SINK | Água Fria - Extravasor e Limpeza 1
OutPort_7388958_1 | SOURCE | Água Fria - Extravasor e Limpeza 1
InPort_7388966_1 | SINK | Água Fria - Extravasor e Limpeza 1
OutPort_7388967_1 | SOURCE | Água Fria - Extravasor e Limpeza 1
InPort_7389045_2 | SINK | Água Fria - Extravasor e Limpeza 1
OutPort_7388989_0 | SOURCE | Água Fria - Extravasor e Limpeza 1
InPort_7388989_1 | SINK | Água Fria - Extravasor e Limpeza 1
OutPort_7389049_2 | SOURCE | Água Fria - Extravasor e Limpeza 1
InPort_7389001_1 | SINK | Água Fria - Extravasor e Limpeza 1
OutPort_7389045_1 | SOURCE | Água Fria - Extravasor e Limpeza 1
InPort_7389079_1 | SINK | Água Fria - Extravasor e Limpeza 1
OutPort_7389058_2 | SOURCE | Água Fria - Extravasor e Limpeza 1
InPort_7389069_0 | SINK | Água Fria - Extravasor e Limpeza 1
OutPort_7389079_2 | SOURCE | Água Fria - Extravasor e Limpeza 1
InPort_7389145_2 | SINK | Água Fria - Extravasor e Limpeza 1
OutPort_7389069_1 | SOURCE | Água Fria - Extravasor e Limpeza 1
InPort_7389126_2 | SINK | Água Fria - Extravasor e Limpeza 1
OutPort_7389081_0 | SOURCE | Água Fria - Extravasor e Limpeza 1
InPort_7389081_1 | SINK | Água Fria - Extravasor e Limpeza 1
OutPort_7389145_1 | SOURCE | Água Fria - Extravasor e Limpeza 1
InPort_7389462_1 | SINK | Água Fria - Extravasor e Limpeza 2
OutPort_7389240_0 | SOURCE | Água Fria - Extravasor e Limpeza 2
InPort_7436973_0 | SINK | Água Fria - Extravasor e Limpeza 2
OutPort_7389462_2 | SOURCE | Água Fria - Extravasor e Limpeza 2
InPort_7436959_1 | SINK | Água Fria - Extravasor e Limpeza 2
OutPort_7389510_1 | SOURCE | Água Fria - Extravasor e Limpeza 2
InPort_7389510_2 | SINK | Água Fria - Extravasor e Limpeza 2
OutPort_7389512_1 | SOURCE | Água Fria - Extravasor e Limpeza 2
InPort_7429214_1 | SINK | Água Fria - Extravasor e Limpeza 1
OutPort_7389688_0 | SOURCE | Água Fria - Extravasor e Limpeza 1
InPort_7389688_1 | SINK | Água Fria - Extravasor e Limpeza 1
OutPort_7389731_2 | SOURCE | Água Fria - Extravasor e Limpeza 1
InPort_7389731_1 | SINK | Água Fria - Extravasor e Limpeza 1
OutPort_7389700_2 | SOURCE | Água Fria - Extravasor e Limpeza 1
InPort_7390480_3 | SINK
InPort_7390728_0 | SINK | Esgoto Sanitário 2
OutPort_7390480_4 | SOURCE | Esgoto Sanitário 2
InPort_7390557_1 | SINK | Esgoto Sanitário 3
OutPort_7390870_0 | SOURCE | Esgoto Sanitário 3
InPort_7390557_2 | SINK
InPort_7390557_3 | SINK | Esgoto Sanitário 2
OutPort_7390759_0 | SOURCE | Esgoto Sanitário 2
InPort_7415520_0 | SINK | Esgoto Sanitário 1
OutPort_7390557_4 | SOURCE | Esgoto Sanitário 1
InPort_7390557_5 | SINK
InPort_7390658_0 | SINK | Esgoto Sanitário 1
OutPort_7390674_1 | SOURCE | Esgoto Sanitário 1
OutPort_7390658_1 | SOURCE | Esgoto Sanitário 1
InPort_7390674_2 | SINK | Esgoto Sanitário 1
OutPort_7415463_1 | SOURCE | Esgoto Sanitário 1
InPort_7390753_2 | SINK | Esgoto Sanitário 2
OutPort_7390728_1 | SOURCE | Esgoto Sanitário 2
InPort_7390743_0 | SINK | Esgoto Sanitário 2
OutPort_7390753_1 | SOURCE | Esgoto Sanitário 2
InPort_7390838_1 | SINK | Esgoto Sanitário 2
OutPort_7390743_1 | SOURCE | Esgoto Sanitário 2
InPort_7390759_1 | SINK | Esgoto Sanitário 2
OutPort_7390838_2 | SOURCE | Esgoto Sanitário 2
Port_7390845_5 | SOURCEANDSINK
InPort_7390895_0 | SINK | Esgoto Sanitário 3
OutPort_7390845_6 | SOURCE | Esgoto Sanitário 3
InPort_7390870_1 | SINK | Esgoto Sanitário 3
OutPort_7390907_2 | SOURCE | Esgoto Sanitário 3
InPort_7390881_0 | SINK | Esgoto Sanitário 3
OutPort_7390897_2 | SOURCE | Esgoto Sanitário 3
InPort_7390907_1 | SINK | Esgoto Sanitário 3
OutPort_7390881_1 | SOURCE | Esgoto Sanitário 3
InPort_7390897_1 | SINK | Esgoto Sanitário 3
OutPort_7390895_1 | SOURCE | Esgoto Sanitário 3
InPort_7390940_1 | SINK
InPort_7390940_2 | SINK
InPort_7390940_3 | SINK | Esgoto Sanitário 4
OutPort_7391026_0 | SOURCE | Esgoto Sanitário 4
InPort_7414859_0 | SINK | Esgoto Sanitário 6
OutPort_7390940_4 | SOURCE | Esgoto Sanitário 6
InPort_7390940_5 | SINK | Esgoto Sanitário 5
OutPort_7415421_0 | SOURCE | Esgoto Sanitário 5
Port_7390981_5 | SOURCEANDSINK
InPort_7391049_0 | SINK | Esgoto Sanitário 4
OutPort_7390981_6 | SOURCE | Esgoto Sanitário 4
InPort_7391026_1 | SINK | Esgoto Sanitário 4
OutPort_7391055_2 | SOURCE | Esgoto Sanitário 4
InPort_7391035_0 | SINK | Esgoto Sanitário 4
OutPort_7391051_2 | SOURCE | Esgoto Sanitário 4
InPort_7391055_1 | SINK | Esgoto Sanitário 4
OutPort_7391035_1 | SOURCE | Esgoto Sanitário 4
InPort_7391051_1 | SINK | Esgoto Sanitário 4
OutPort_7391049_1 | SOURCE | Esgoto Sanitário 4
InPort_7391071_0 | SINK | Esgoto Sanitário 6
OutPort_7414858_1 | SOURCE | Esgoto Sanitário 6
OutPort_7391071_1 | SOURCE | Esgoto Sanitário 6
InPort_7391109_0 | SINK | Esgoto Sanitário 7
OutPort_7391105_3 | SOURCE | Esgoto Sanitário 7
InPort_7391107_0 | SINK | Esgoto Sanitário 7
OutPort_7391111_2 | SOURCE | Esgoto Sanitário 7
OutPort_7391107_1 | SOURCE | Esgoto Sanitário 7
InPort_7391111_1 | SINK | Esgoto Sanitário 7
OutPort_7391109_1 | SOURCE | Esgoto Sanitário 7
InPort_7399081_0 | SINK | Esgoto Sanitário 11
OutPort_7391159_1 | SOURCE | Esgoto Sanitário 11
InPort_7391159_2 | SINK
InPort_7391159_3 | SINK
InPort_7391159_4 | SINK | Esgoto Sanitário 10
OutPort_7391445_1 | SOURCE | Esgoto Sanitário 10
InPort_7391159_5 | SINK | Água Fria Alimentação 2
OutPort_7439256_0 | SOURCE | Água Fria Alimentação 2
InPort_7391159_6 | SINK
InPort_7391159_7 | SINK | Esgoto Sanitário 9
OutPort_7391866_0 | SOURCE | Esgoto Sanitário 9
InPort_7391159_8 | SINK | Esgoto Sanitário 8
OutPort_7391497_0 | SOURCE | Esgoto Sanitário 8
InPort_7391159_9 | SINK
Port_7391229_5 | SOURCEANDSINK
InPort_7391530_0 | SINK | Esgoto Sanitário 8
OutPort_7391229_6 | SOURCE | Esgoto Sanitário 8
Port_7391275_5 | SOURCEANDSINK | Esgoto Sanitário 13
Port_7391464_0 | SOURCEANDSINK | Esgoto Sanitário 13
InPort_7392050_0 | SINK | Esgoto Sanitário 10
OutPort_7391275_6 | SOURCE | Esgoto Sanitário 10
InPort_7391445_0 | SINK | Esgoto Sanitário 10
OutPort_7392074_2 | SOURCE | Esgoto Sanitário 10
Port_7391464_1 | SOURCEANDSINK | Esgoto Sanitário 13
InPort_7391497_1 | SINK | Esgoto Sanitário 8
OutPort_7391512_2 | SOURCE | Esgoto Sanitário 8
InPort_7391512_1 | SINK | Esgoto Sanitário 8
OutPort_7391506_0 | SOURCE | Esgoto Sanitário 8
InPort_7391506_1 | SINK | Esgoto Sanitário 8
OutPort_7391536_1 | SOURCE | Esgoto Sanitário 8
InPort_7391516_0 | SINK | Esgoto Sanitário 8
OutPort_7391532_2 | SOURCE | Esgoto Sanitário 8
InPort_7391536_2 | SINK | Esgoto Sanitário 8
OutPort_7391516_1 | SOURCE | Esgoto Sanitário 8
InPort_7391532_1 | SINK | Esgoto Sanitário 8
OutPort_7391530_1 | SOURCE | Esgoto Sanitário 8
InPort_7391560_0 | SINK | Esgoto Sanitário 11
OutPort_7505195_1 | SOURCE | Esgoto Sanitário 11
OutPort_7391560_1 | SOURCE | Esgoto Sanitário 11
Port_7391618_5 | SOURCEANDSINK | Esgoto Sanitário 12
InPort_7391895_0 | SINK | Esgoto Sanitário 9
OutPort_7391618_6 | SOURCE | Esgoto Sanitário 9
InPort_7391866_1 | SINK | Esgoto Sanitário 9
OutPort_7391901_2 | SOURCE | Esgoto Sanitário 9
InPort_7391881_0 | SINK | Esgoto Sanitário 9
OutPort_7391897_2 | SOURCE | Esgoto Sanitário 9
InPort_7391901_1 | SINK | Esgoto Sanitário 9
OutPort_7391881_1 | SOURCE | Esgoto Sanitário 9
InPort_7391897_1 | SINK | Esgoto Sanitário 9
OutPort_7391895_1 | SOURCE | Esgoto Sanitário 9
InPort_7392074_1 | SINK | Esgoto Sanitário 10
OutPort_7392050_1 | SOURCE | Esgoto Sanitário 10
InPort_7392107_1 | SINK
InPort_7392107_2 | SINK | Esgoto Sanitário 14
InPort_7392107_3 | SINK | Esgoto Sanitário 15
OutPort_7491224_0 | SOURCE | Esgoto Sanitário 15
InPort_7491366_0 | SINK | Esgoto Sanitário 16
OutPort_7392107_4 | SOURCE | Esgoto Sanitário 16
InPort_7392107_5 | SINK
InPort_7392509_0 | SINK | Esgoto Sanitário 17
OutPort_7392505_3 | SOURCE | Esgoto Sanitário 17
InPort_7392507_0 | SINK | Esgoto Sanitário 17
OutPort_7503503_2 | SOURCE | Esgoto Sanitário 17
InPort_7503883_3 | SINK | Esgoto Sanitário 17
OutPort_7392507_1 | SOURCE | Esgoto Sanitário 17
InPort_7503503_1 | SINK | Esgoto Sanitário 17
OutPort_7392509_1 | SOURCE | Esgoto Sanitário 17
InPort_7392586_0 | SINK | Esgoto Sanitário 18
OutPort_7392582_3 | SOURCE | Esgoto Sanitário 18
InPort_7392584_0 | SINK | Esgoto Sanitário 18
OutPort_7392588_2 | SOURCE | Esgoto Sanitário 18
OutPort_7392584_1 | SOURCE | Esgoto Sanitário 18
InPort_7392588_1 | SINK | Esgoto Sanitário 18
OutPort_7392586_1 | SOURCE | Esgoto Sanitário 18
InPort_7507308_0 | SINK | Esgoto Sanitário 40
OutPort_7392671_3 | SOURCE | Esgoto Sanitário 40
InPort_7392671_4 | SINK
InPort_7392671_5 | SINK
InPort_7392671_6 | SINK
InPort_7392671_7 | SINK
InPort_7392671_8 | SINK
InPort_7392671_9 | SINK
InPort_7392671_10 | SINK
InPort_7392671_11 | SINK
InPort_7392671_12 | SINK
InPort_7504511_0 | SINK | Esgoto Sanitário 23
OutPort_7392928_3 | SOURCE | Esgoto Sanitário 23
InPort_7392928_4 | SINK
InPort_7392928_5 | SINK | Esgoto Sanitário 41
InPort_7392928_6 | SINK
InPort_7392928_7 | SINK
InPort_7392928_8 | SINK
InPort_7392928_9 | SINK
InPort_7392928_10 | SINK
InPort_7392928_11 | SINK
InPort_7392928_12 | SINK
InPort_7392972_3 | SINK | Esgoto Sanitário 79
OutPort_7426250_0 | SOURCE | Esgoto Sanitário 79
InPort_7504074_0 | SINK | Esgoto Sanitário 20
OutPort_7392972_4 | SOURCE | Esgoto Sanitário 20
InPort_7392994_1 | SINK | Esgoto Sanitário 20
OutPort_7504074_1 | SOURCE | Esgoto Sanitário 20
InPort_7392994_2 | SINK
InPort_7392994_3 | SINK | Esgoto Sanitário 20
OutPort_7504140_1 | SOURCE | Esgoto Sanitário 20
InPort_7503828_0 | SINK | Esgoto Sanitário 17
OutPort_7392994_4 | SOURCE | Esgoto Sanitário 17
InPort_7392994_5 | SINK | Esgoto Sanitário 76
OutPort_7415914_0 | SOURCE | Esgoto Sanitário 76
Port_7393067_5 | SOURCEANDSINK
InPort_7393334_0 | SINK | Esgoto Sanitário 20
OutPort_7393067_6 | SOURCE | Esgoto Sanitário 20
InPort_7393320_0 | SINK | Esgoto Sanitário 20
OutPort_7393336_2 | SOURCE | Esgoto Sanitário 20
InPort_7504214_1 | SINK | Esgoto Sanitário 20
OutPort_7393320_1 | SOURCE | Esgoto Sanitário 20
InPort_7393336_1 | SINK | Esgoto Sanitário 20
OutPort_7393334_1 | SOURCE | Esgoto Sanitário 20
Port_7397277_7 | SOURCEANDSINK
InPort_7397335_0 | SINK | Esgoto Sanitário 24
OutPort_7397277_8 | SOURCE | Esgoto Sanitário 24
InPort_7397354_1 | SINK | Esgoto Sanitário 24
OutPort_7397335_1 | SOURCE | Esgoto Sanitário 24
InPort_7397348_0 | SINK | Esgoto Sanitário 24
OutPort_7397354_2 | SOURCE | Esgoto Sanitário 24
OutPort_7397348_1 | SOURCE | Esgoto Sanitário 24
InPort_7397422_3 | SINK
InPort_7505148_0 | SINK | Esgoto Sanitário 25
OutPort_7397422_4 | SOURCE | Esgoto Sanitário 25
Port_7397422_5 | SOURCEANDSINK
Port_7397422_6 | SOURCEANDSINK
InPort_7397422_7 | SINK
InPort_7397422_8 | SINK
InPort_7399067_0 | SINK | Esgoto - Ventilação 4
OutPort_7399092_2 | SOURCE | Esgoto - Ventilação 4
InPort_7399111_1 | SINK | Esgoto - Ventilação 4
OutPort_7399067_1 | SOURCE | Esgoto - Ventilação 4
InPort_7399078_0 | SINK | Esgoto - Ventilação 4
OutPort_7399080_3 | SOURCE | Esgoto - Ventilação 4
InPort_7399092_1 | SINK | Esgoto - Ventilação 4
OutPort_7399078_1 | SOURCE | Esgoto - Ventilação 4
InPort_7505196_0 | SINK | Esgoto Sanitário 11
OutPort_7399080_1 | SOURCE | Esgoto Sanitário 11
InPort_7399080_2 | SINK | Esgoto Sanitário 11
OutPort_7399081_1 | SOURCE | Esgoto Sanitário 11
InPort_7399108_0 | SINK | Esgoto - Ventilação 4
OutPort_7399111_2 | SOURCE | Esgoto - Ventilação 4
InPort_7399147_1 | SINK | Esgoto - Ventilação 4
OutPort_7399108_1 | SOURCE | Esgoto - Ventilação 4
InPort_7399139_0 | SINK | Esgoto - Ventilação 4
OutPort_7399147_2 | SOURCE | Esgoto - Ventilação 4
InPort_7399163_1 | SINK | Esgoto - Ventilação 4
OutPort_7399139_1 | SOURCE | Esgoto - Ventilação 4
InPort_7399157_0 | SINK | Esgoto - Ventilação 4
OutPort_7399163_2 | SOURCE | Esgoto - Ventilação 4
InPort_7399192_1 | SINK | Esgoto - Ventilação 4
OutPort_7399157_1 | SOURCE | Esgoto - Ventilação 4
Port_7399608_5 | SOURCEANDSINK
InPort_7400434_0 | SINK | Esgoto Sanitário 30
OutPort_7399608_6 | SOURCE | Esgoto Sanitário 30
InPort_7400951_0 | SINK | Esgoto Sanitário 27
OutPort_7400082_1 | SOURCE | Esgoto Sanitário 27
InPort_7400082_2 | SINK
InPort_7400082_3 | SINK
InPort_7400082_4 | SINK
InPort_7400082_5 | SINK
InPort_7400082_6 | SINK
InPort_7400082_7 | SINK
InPort_7400082_8 | SINK | Esgoto Sanitário 30
OutPort_7400512_0 | SOURCE | Esgoto Sanitário 30
InPort_7400082_9 | SINK
InPort_7400200_0 | SINK | Esgoto Sanitário 27
OutPort_7400206_2 | SOURCE | Esgoto Sanitário 27
OutPort_7400200_1 | SOURCE | Esgoto Sanitário 27
InPort_7400206_1 | SINK | Esgoto Sanitário 27
OutPort_7400762_1 | SOURCE | Esgoto Sanitário 27
InPort_7400453_1 | SINK | Esgoto Sanitário 30
OutPort_7400434_1 | SOURCE | Esgoto Sanitário 30
InPort_7400447_0 | SINK | Esgoto Sanitário 30
OutPort_7400453_2 | SOURCE | Esgoto Sanitário 30
InPort_7400732_2 | SINK | Esgoto Sanitário 30
OutPort_7400447_1 | SOURCE | Esgoto Sanitário 30
InPort_7400512_1 | SINK | Esgoto Sanitário 30
OutPort_7400732_1 | SOURCE | Esgoto Sanitário 30
InPort_7400758_0 | SINK | Esgoto - Ventilação 7
OutPort_7400950_3 | SOURCE | Esgoto - Ventilação 7
InPort_7400990_1 | SINK | Esgoto - Ventilação 7
OutPort_7400758_1 | SOURCE | Esgoto - Ventilação 7
InPort_7400762_0 | SINK | Esgoto Sanitário 27
OutPort_7401249_1 | SOURCE | Esgoto Sanitário 27
InPort_7401250_0 | SINK | Esgoto Sanitário 27
OutPort_7400950_1 | SOURCE | Esgoto Sanitário 27
InPort_7400950_2 | SINK | Esgoto Sanitário 27
OutPort_7400951_1 | SOURCE | Esgoto Sanitário 27
InPort_7400973_0 | SINK | Esgoto - Ventilação 7
OutPort_7400990_2 | SOURCE | Esgoto - Ventilação 7
InPort_7401006_1 | SINK | Esgoto - Ventilação 7
OutPort_7400973_1 | SOURCE | Esgoto - Ventilação 7
InPort_7401000_0 | SINK | Esgoto - Ventilação 7
OutPort_7401006_2 | SOURCE | Esgoto - Ventilação 7
InPort_7401035_1 | SINK | Esgoto - Ventilação 7
OutPort_7401000_1 | SOURCE | Esgoto - Ventilação 7
InPort_7401068_1 | SINK
InPort_7401068_2 | SINK | Esgoto Sanitário 31
OutPort_7401724_1 | SOURCE | Esgoto Sanitário 31
InPort_7401068_3 | SINK
InPort_7412471_0 | SINK | Esgoto Sanitário 27
OutPort_7401068_4 | SOURCE | Esgoto Sanitário 27
InPort_7401068_5 | SINK
InPort_7401178_0 | SINK | Esgoto Sanitário 27
OutPort_7412470_1 | SOURCE | Esgoto Sanitário 27
InPort_7401487_1 | SINK | Esgoto Sanitário 27
OutPort_7401178_1 | SOURCE | Esgoto Sanitário 27
InPort_7401249_3 | SINK | Esgoto Sanitário 27
OutPort_7401186_0 | SOURCE | Esgoto Sanitário 27
InPort_7401186_1 | SINK | Esgoto Sanitário 27
OutPort_7401487_2 | SOURCE | Esgoto Sanitário 27
InPort_7401249_2 | SINK | Esgoto Sanitário 27
OutPort_7401250_1 | SOURCE | Esgoto Sanitário 27
Port_7401636_5 | SOURCEANDSINK | Esgoto Sanitário 32
Port_7401736_0 | SOURCEANDSINK | Esgoto Sanitário 32
InPort_7401868_0 | SINK | Esgoto Sanitário 31
OutPort_7401636_6 | SOURCE | Esgoto Sanitário 31
InPort_7401724_0 | SINK | Esgoto Sanitário 31
OutPort_7412950_2 | SOURCE | Esgoto Sanitário 31
Port_7401736_1 | SOURCEANDSINK | Esgoto Sanitário 32
InPort_7412950_1 | SINK | Esgoto Sanitário 31
OutPort_7401868_1 | SOURCE | Esgoto Sanitário 31
InPort_7401928_1 | SINK | Esgoto Sanitário 34
OutPort_7402094_1 | SOURCE | Esgoto Sanitário 34
InPort_7401928_2 | SINK
InPort_7401928_3 | SINK
InPort_7412048_0 | SINK | Esgoto Sanitário 33
OutPort_7401928_4 | SOURCE | Esgoto Sanitário 33
InPort_7401928_5 | SINK
InPort_7401988_0 | SINK | Esgoto Sanitário 33
OutPort_7412047_1 | SOURCE | Esgoto Sanitário 33
InPort_7402002_2 | SINK | Esgoto Sanitário 33
OutPort_7401988_1 | SOURCE | Esgoto Sanitário 33
InPort_7401996_0 | SINK | Esgoto Sanitário 33
OutPort_7402002_1 | SOURCE | Esgoto Sanitário 33
InPort_7402018_2 | SINK | Esgoto Sanitário 33
OutPort_7401996_1 | SOURCE | Esgoto Sanitário 33
InPort_7402012_0 | SINK | Esgoto Sanitário 33
OutPort_7402018_1 | SOURCE | Esgoto Sanitário 33
OutPort_7402012_1 | SOURCE | Esgoto Sanitário 33
Port_7402067_5 | SOURCEANDSINK | Esgoto Sanitário 35
Port_7402106_0 | SOURCEANDSINK | Esgoto Sanitário 35
InPort_7402135_0 | SINK | Esgoto Sanitário 34
OutPort_7402067_6 | SOURCE | Esgoto Sanitário 34
InPort_7402094_0 | SINK | Esgoto Sanitário 34
OutPort_7402154_2 | SOURCE | Esgoto Sanitário 34
Port_7402106_1 | SOURCEANDSINK | Esgoto Sanitário 35
InPort_7402154_1 | SINK | Esgoto Sanitário 34
OutPort_7402135_1 | SOURCE | Esgoto Sanitário 34
InPort_7412315_0 | SINK | Esgoto Sanitário 36
OutPort_7402194_1 | SOURCE | Esgoto Sanitário 36
InPort_7402194_2 | SINK
InPort_7402194_3 | SINK | Esgoto Sanitário 37
OutPort_7403063_0 | SOURCE | Esgoto Sanitário 37
InPort_7402194_4 | SINK
InPort_7402194_5 | SINK
InPort_7402194_6 | SINK
InPort_7402194_7 | SINK | Esgoto Sanitário 38
OutPort_7403006_1 | SOURCE | Esgoto Sanitário 38
InPort_7402194_8 | SINK | Esgoto Sanitário 39
OutPort_7403128_0 | SOURCE | Esgoto Sanitário 39
InPort_7402194_9 | SINK
Port_7402464_0 | SOURCEANDSINK | Esgoto Sanitário 36
Port_7412314_1 | SOURCEANDSINK | Esgoto Sanitário 36
Port_7402464_1 | SOURCEANDSINK | Esgoto Sanitário 36
Port_7402841_5 | SOURCEANDSINK
InPort_7403084_0 | SINK | Esgoto Sanitário 37
OutPort_7402841_6 | SOURCE | Esgoto Sanitário 37
Port_7402857_5 | SOURCEANDSINK
InPort_7403151_0 | SINK | Esgoto Sanitário 39
OutPort_7402857_6 | SOURCE | Esgoto Sanitário 39
Port_7402901_5 | SOURCEANDSINK
InPort_7403023_0 | SINK | Esgoto Sanitário 38
OutPort_7402901_6 | SOURCE | Esgoto Sanitário 38
InPort_7403006_0 | SINK | Esgoto Sanitário 38
OutPort_7403025_2 | SOURCE | Esgoto Sanitário 38
InPort_7403025_1 | SINK | Esgoto Sanitário 38
OutPort_7403023_1 | SOURCE | Esgoto Sanitário 38
InPort_7403063_1 | SINK | Esgoto Sanitário 37
OutPort_7403090_1 | SOURCE | Esgoto Sanitário 37
InPort_7403072_0 | SINK | Esgoto Sanitário 37
OutPort_7403086_2 | SOURCE | Esgoto Sanitário 37
InPort_7403090_2 | SINK | Esgoto Sanitário 37
OutPort_7403072_1 | SOURCE | Esgoto Sanitário 37
InPort_7403086_1 | SINK | Esgoto Sanitário 37
OutPort_7403084_1 | SOURCE | Esgoto Sanitário 37
InPort_7403128_1 | SINK | Esgoto Sanitário 39
OutPort_7403157_1 | SOURCE | Esgoto Sanitário 39
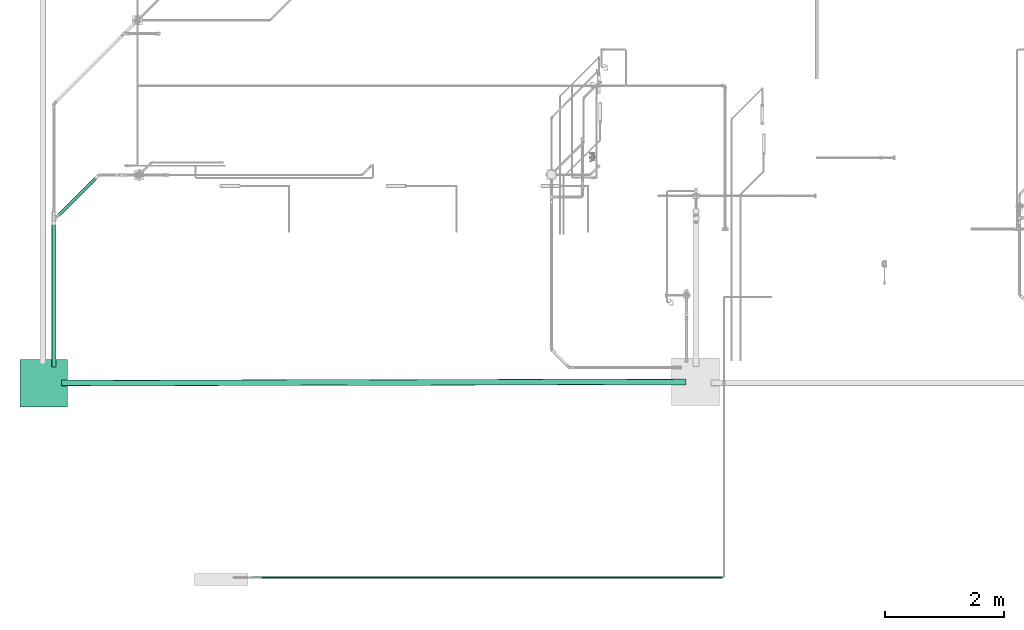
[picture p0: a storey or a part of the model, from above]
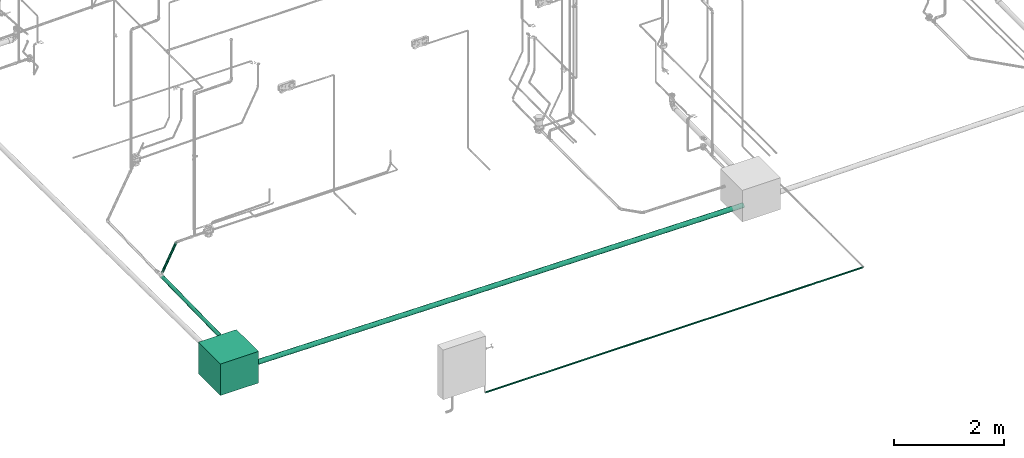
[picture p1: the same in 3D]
Properties of the parts of a building model (IFC2X3), part 2 of 4

# IfcDistributionPort (2899)
Name | FlowDirection | Group
InPort_7403137_0 | SINK | Esgoto Sanitário 39
OutPort_7403153_2 | SOURCE | Esgoto Sanitário 39
InPort_7403157_2 | SINK | Esgoto Sanitário 39
OutPort_7403137_1 | SOURCE | Esgoto Sanitário 39
InPort_7403153_1 | SINK | Esgoto Sanitário 39
OutPort_7403151_1 | SOURCE | Esgoto Sanitário 39
Port_7403470_5 | SOURCEANDSINK | Esgoto Sanitário 42
InPort_7403479_0 | SINK | Esgoto Sanitário 42
OutPort_7403470_6 | SOURCE | Esgoto Sanitário 42
InPort_7403472_1 | SINK | Esgoto Sanitário 42
OutPort_7403475_1 | SOURCE | Esgoto Sanitário 42
InPort_7403472_2 | SINK
InPort_7403472_3 | SINK
InPort_7403486_0 | SINK | Esgoto Sanitário 44
OutPort_7403472_4 | SOURCE | Esgoto Sanitário 44
InPort_7403472_5 | SINK | Esgoto Sanitário 45
OutPort_7403511_0 | SOURCE | Esgoto Sanitário 45
InPort_7403475_0 | SINK | Esgoto Sanitário 42
OutPort_7403481_2 | SOURCE | Esgoto Sanitário 42
InPort_7403477_0 | SINK | Esgoto Sanitário 44
OutPort_7403485_1 | SOURCE | Esgoto Sanitário 44
OutPort_7403477_1 | SOURCE | Esgoto Sanitário 44
InPort_7403481_1 | SINK | Esgoto Sanitário 42
OutPort_7403479_1 | SOURCE | Esgoto Sanitário 42
InPort_7403483_0 | SINK | Esgoto - Ventilação 2
OutPort_7403493_2 | SOURCE | Esgoto - Ventilação 2
InPort_7403499_1 | SINK | Esgoto - Ventilação 2
OutPort_7403483_1 | SOURCE | Esgoto - Ventilação 2
InPort_7403485_2 | SINK | Esgoto Sanitário 44
OutPort_7403486_1 | SOURCE | Esgoto Sanitário 44
InPort_7403493_1 | SINK | Esgoto - Ventilação 2
OutPort_7403485_3 | SOURCE | Esgoto - Ventilação 2
InPort_7438639_1 | SINK | Esgoto - Ventilação 2
OutPort_7403497_0 | SOURCE | Esgoto - Ventilação 2
InPort_7403497_1 | SINK | Esgoto - Ventilação 2
OutPort_7403499_2 | SOURCE | Esgoto - Ventilação 2
InPort_7403511_1 | SINK | Esgoto Sanitário 45
InPort_7403517_0 | SINK | Esgoto Sanitário 49
OutPort_7403513_3 | SOURCE | Esgoto Sanitário 49
InPort_7403515_0 | SINK | Esgoto Sanitário 49
OutPort_7403579_2 | SOURCE | Esgoto Sanitário 49
OutPort_7403515_1 | SOURCE | Esgoto Sanitário 49
InPort_7403579_1 | SINK | Esgoto Sanitário 49
OutPort_7403517_1 | SOURCE | Esgoto Sanitário 49
InPort_7405101_0 | SINK | Esgoto Sanitário 51
OutPort_7403525_3 | SOURCE | Esgoto Sanitário 51
InPort_7403525_4 | SINK
InPort_7403525_5 | SINK
InPort_7403525_6 | SINK
InPort_7403525_7 | SINK
InPort_7403525_8 | SINK | Esgoto Sanitário 21
OutPort_7508052_0 | SOURCE | Esgoto Sanitário 21
InPort_7403525_9 | SINK
InPort_7403525_10 | SINK
InPort_7403525_11 | SINK
InPort_7403525_12 | SINK
InPort_7403859_1 | SINK
InPort_7403859_2 | SINK | Esgoto Sanitário 46
OutPort_7404314_1 | SOURCE | Esgoto Sanitário 46
InPort_7403859_3 | SINK
InPort_7413020_0 | SINK | Esgoto Sanitário 43
OutPort_7403859_4 | SOURCE | Esgoto Sanitário 43
InPort_7403859_5 | SINK
InPort_7403936_1 | SINK
InPort_7403936_2 | SINK | Esgoto Sanitário 48
OutPort_7404531_0 | SOURCE | Esgoto Sanitário 48
InPort_7403936_3 | SINK
InPort_7413272_0 | SINK | Esgoto Sanitário 43
OutPort_7403936_4 | SOURCE | Esgoto Sanitário 43
InPort_7403936_5 | SINK
InPort_7403986_0 | SINK | Esgoto Sanitário 43
OutPort_7413271_1 | SOURCE | Esgoto Sanitário 43
InPort_7404252_2 | SINK | Esgoto Sanitário 43
OutPort_7403986_1 | SOURCE | Esgoto Sanitário 43
InPort_7404107_3 | SINK | Esgoto Sanitário 43
OutPort_7404000_0 | SOURCE | Esgoto Sanitário 43
InPort_7404000_1 | SINK | Esgoto Sanitário 43
OutPort_7404252_1 | SOURCE | Esgoto Sanitário 43
InPort_7404034_0 | SINK | Esgoto Sanitário 43
OutPort_7404107_1 | SOURCE | Esgoto Sanitário 43
InPort_7404048_2 | SINK | Esgoto Sanitário 43
OutPort_7404034_1 | SOURCE | Esgoto Sanitário 43
InPort_7404042_0 | SINK | Esgoto Sanitário 43
OutPort_7404048_1 | SOURCE | Esgoto Sanitário 43
OutPort_7404042_1 | SOURCE | Esgoto Sanitário 43
InPort_7404107_2 | SINK | Esgoto Sanitário 43
OutPort_7404108_1 | SOURCE | Esgoto Sanitário 43
InPort_7404108_0 | SINK | Esgoto Sanitário 43
OutPort_7413019_1 | SOURCE | Esgoto Sanitário 43
Port_7404263_5 | SOURCEANDSINK | Esgoto Sanitário 47
Port_7404326_0 | SOURCEANDSINK | Esgoto Sanitário 47
InPort_7404457_0 | SINK | Esgoto Sanitário 46
OutPort_7404263_6 | SOURCE | Esgoto Sanitário 46
InPort_7404314_0 | SINK | Esgoto Sanitário 46
OutPort_7404474_2 | SOURCE | Esgoto Sanitário 46
Port_7404326_1 | SOURCEANDSINK | Esgoto Sanitário 47
InPort_7404474_1 | SINK | Esgoto Sanitário 46
OutPort_7404457_1 | SOURCE | Esgoto Sanitário 46
Port_7404506_5 | SOURCEANDSINK
InPort_7404554_0 | SINK | Esgoto Sanitário 48
OutPort_7404506_6 | SOURCE | Esgoto Sanitário 48
InPort_7404531_1 | SINK | Esgoto Sanitário 48
OutPort_7404560_1 | SOURCE | Esgoto Sanitário 48
InPort_7404540_0 | SINK | Esgoto Sanitário 48
OutPort_7404556_2 | SOURCE | Esgoto Sanitário 48
InPort_7404560_2 | SINK | Esgoto Sanitário 48
OutPort_7404540_1 | SOURCE | Esgoto Sanitário 48
InPort_7404556_1 | SINK | Esgoto Sanitário 48
OutPort_7404554_1 | SOURCE | Esgoto Sanitário 48
OutPort_7404690_3 | SOURCE | Esgoto Sanitário 78
InPort_7404690_4 | SINK
InPort_7404690_5 | SINK
InPort_7404690_6 | SINK
InPort_7404690_7 | SINK
InPort_7404690_8 | SINK
InPort_7404690_9 | SINK
InPort_7404690_10 | SINK
InPort_7404690_11 | SINK
InPort_7404690_12 | SINK
InPort_7404861_0 | SINK | Esgoto Sanitário 50
OutPort_7404857_3 | SOURCE | Esgoto Sanitário 50
InPort_7502599_1 | SINK | Esgoto Sanitário 50
OutPort_7404861_1 | SOURCE | Esgoto Sanitário 50
OutPort_7405101_1 | SOURCE | Esgoto Sanitário 51
InPort_7405141_1 | SINK
InPort_7405141_2 | SINK | Esgoto Sanitário 53
OutPort_7405296_0 | SOURCE | Esgoto Sanitário 53
InPort_7405141_3 | SINK
InPort_7413539_0 | SINK | Esgoto Sanitário 52
OutPort_7405141_4 | SOURCE | Esgoto Sanitário 52
InPort_7405141_5 | SINK
InPort_7405192_0 | SINK | Esgoto Sanitário 52
OutPort_7413538_1 | SOURCE | Esgoto Sanitário 52
InPort_7405207_1 | SINK | Esgoto Sanitário 52
OutPort_7405192_1 | SOURCE | Esgoto Sanitário 52
InPort_7405201_0 | SINK | Esgoto Sanitário 52
OutPort_7405207_2 | SOURCE | Esgoto Sanitário 52
OutPort_7405201_1 | SOURCE | Esgoto Sanitário 52
Port_7405253_5 | SOURCEANDSINK
InPort_7405569_0 | SINK | Esgoto Sanitário 53
OutPort_7405253_6 | SOURCE | Esgoto Sanitário 53
InPort_7405296_1 | SINK | Esgoto Sanitário 53
OutPort_7405577_2 | SOURCE | Esgoto Sanitário 53
InPort_7405551_0 | SINK | Esgoto Sanitário 53
OutPort_7405571_2 | SOURCE | Esgoto Sanitário 53
InPort_7405577_1 | SINK | Esgoto Sanitário 53
OutPort_7405551_1 | SOURCE | Esgoto Sanitário 53
InPort_7405571_1 | SINK | Esgoto Sanitário 53
OutPort_7405569_1 | SOURCE | Esgoto Sanitário 53
InPort_7405864_0 | SINK | Esgoto Sanitário 50
OutPort_7502599_2 | SOURCE | Esgoto Sanitário 50
OutPort_7405864_1 | SOURCE | Esgoto Sanitário 50
Port_7406668_5 | SOURCEANDSINK
InPort_7407364_0 | SINK | Esgoto Sanitário 57
OutPort_7406668_6 | SOURCE | Esgoto Sanitário 57
Port_7406707_5 | SOURCEANDSINK
InPort_7407313_0 | SINK | Esgoto Sanitário 59
OutPort_7406707_6 | SOURCE | Esgoto Sanitário 59
Port_7406719_5 | SOURCEANDSINK
InPort_7407245_0 | SINK | Esgoto Sanitário 58
OutPort_7406719_6 | SOURCE | Esgoto Sanitário 58
InPort_7413811_0 | SINK | Esgoto Sanitário 56
OutPort_7407036_1 | SOURCE | Esgoto Sanitário 56
InPort_7407036_2 | SINK
InPort_7407036_3 | SINK | Esgoto Sanitário 57
OutPort_7407343_0 | SOURCE | Esgoto Sanitário 57
InPort_7407036_4 | SINK | Esgoto Sanitário 58
OutPort_7407217_0 | SOURCE | Esgoto Sanitário 58
InPort_7407036_5 | SINK | Esgoto Sanitário 75
OutPort_7414809_0 | SOURCE | Esgoto Sanitário 75
InPort_7407036_6 | SINK
InPort_7407036_7 | SINK | Esgoto Sanitário 59
OutPort_7407275_0 | SOURCE | Esgoto Sanitário 59
InPort_7407036_8 | SINK
InPort_7407036_9 | SINK
InPort_7407157_0 | SINK | Esgoto Sanitário 56
OutPort_7413810_1 | SOURCE | Esgoto Sanitário 56
InPort_7502825_1 | SINK | Esgoto Sanitário 56
OutPort_7407157_1 | SOURCE | Esgoto Sanitário 56
InPort_7407217_1 | SINK | Esgoto Sanitário 58
OutPort_7407251_1 | SOURCE | Esgoto Sanitário 58
InPort_7407233_0 | SINK | Esgoto Sanitário 58
OutPort_7407247_2 | SOURCE | Esgoto Sanitário 58
InPort_7407251_2 | SINK | Esgoto Sanitário 58
OutPort_7407233_1 | SOURCE | Esgoto Sanitário 58
InPort_7407247_1 | SINK | Esgoto Sanitário 58
OutPort_7407245_1 | SOURCE | Esgoto Sanitário 58
InPort_7407275_1 | SINK | Esgoto Sanitário 59
OutPort_7407297_1 | SOURCE | Esgoto Sanitário 59
InPort_7407297_2 | SINK | Esgoto Sanitário 59
OutPort_7407291_0 | SOURCE | Esgoto Sanitário 59
InPort_7407291_1 | SINK | Esgoto Sanitário 59
OutPort_7407319_2 | SOURCE | Esgoto Sanitário 59
InPort_7407301_0 | SINK | Esgoto Sanitário 59
OutPort_7407315_2 | SOURCE | Esgoto Sanitário 59
InPort_7407319_1 | SINK | Esgoto Sanitário 59
OutPort_7407301_1 | SOURCE | Esgoto Sanitário 59
InPort_7407315_1 | SINK | Esgoto Sanitário 59
OutPort_7407313_1 | SOURCE | Esgoto Sanitário 59
InPort_7407343_1 | SINK | Esgoto Sanitário 57
OutPort_7407370_2 | SOURCE | Esgoto Sanitário 57
InPort_7407352_0 | SINK | Esgoto Sanitário 57
OutPort_7407366_2 | SOURCE | Esgoto Sanitário 57
InPort_7407370_1 | SINK | Esgoto Sanitário 57
OutPort_7407352_1 | SOURCE | Esgoto Sanitário 57
InPort_7407366_1 | SINK | Esgoto Sanitário 57
OutPort_7407364_1 | SOURCE | Esgoto Sanitário 57
InPort_7506664_0 | SINK | Esgoto Sanitário 63
OutPort_7407902_1 | SOURCE | Esgoto Sanitário 63
InPort_7407902_2 | SINK | Esgoto Sanitário 64
InPort_7407902_3 | SINK | Esgoto Sanitário 64
OutPort_7408856_0 | SOURCE | Esgoto Sanitário 64
InPort_7407902_4 | SINK
InPort_7407902_5 | SINK
InPort_7407902_6 | SINK | Esgoto Sanitário 66
InPort_7407902_7 | SINK | Esgoto Sanitário 66
OutPort_7408917_1 | SOURCE | Esgoto Sanitário 66
InPort_7407902_8 | SINK
InPort_7407902_9 | SINK
Port_7408344_5 | SOURCEANDSINK
InPort_7408946_0 | SINK | Esgoto Sanitário 66
OutPort_7408344_6 | SOURCE | Esgoto Sanitário 66
Port_7408401_5 | SOURCEANDSINK
InPort_7408887_0 | SINK | Esgoto Sanitário 64
OutPort_7408401_6 | SOURCE | Esgoto Sanitário 64
InPort_7408856_1 | SINK | Esgoto Sanitário 64
OutPort_7506366_2 | SOURCE | Esgoto Sanitário 64
InPort_7506366_1 | SINK | Esgoto Sanitário 64
OutPort_7408865_0 | SOURCE | Esgoto Sanitário 64
InPort_7408865_1 | SINK | Esgoto Sanitário 64
OutPort_7408893_1 | SOURCE | Esgoto Sanitário 64
InPort_7408875_0 | SINK | Esgoto Sanitário 64
OutPort_7408889_2 | SOURCE | Esgoto Sanitário 64
InPort_7408893_2 | SINK | Esgoto Sanitário 64
OutPort_7408875_1 | SOURCE | Esgoto Sanitário 64
InPort_7408889_1 | SINK | Esgoto Sanitário 64
OutPort_7408887_1 | SOURCE | Esgoto Sanitário 64
InPort_7408917_0 | SINK | Esgoto Sanitário 66
OutPort_7408952_1 | SOURCE | Esgoto Sanitário 66
InPort_7408934_0 | SINK | Esgoto Sanitário 66
OutPort_7408948_2 | SOURCE | Esgoto Sanitário 66
InPort_7408952_2 | SINK | Esgoto Sanitário 66
OutPort_7408934_1 | SOURCE | Esgoto Sanitário 66
InPort_7408948_1 | SINK | Esgoto Sanitário 66
OutPort_7408946_1 | SOURCE | Esgoto Sanitário 66
InPort_7414209_0 | SINK | Esgoto Sanitário 63
OutPort_7409151_1 | SOURCE | Esgoto Sanitário 63
InPort_7409151_2 | SINK
InPort_7409151_3 | SINK | Esgoto Sanitário 65
OutPort_7409279_0 | SOURCE | Esgoto Sanitário 65
InPort_7409151_4 | SINK
InPort_7409151_5 | SINK
InPort_7409151_6 | SINK | Esgoto Sanitário 68
OutPort_7409360_0 | SOURCE | Esgoto Sanitário 68
InPort_7409151_7 | SINK
InPort_7409151_8 | SINK
InPort_7409151_9 | SINK
InPort_7409279_1 | SINK | Esgoto Sanitário 65
OutPort_7409296_1 | SOURCE | Esgoto Sanitário 65
InPort_7409296_2 | SINK | Esgoto Sanitário 65
OutPort_7409290_0 | SOURCE | Esgoto Sanitário 65
InPort_7409290_1 | SINK | Esgoto Sanitário 65
OutPort_7409309_1 | SOURCE | Esgoto Sanitário 65
InPort_7409306_0 | SINK | Esgoto Sanitário 65
InPort_7409309_2 | SINK | Esgoto Sanitário 65
OutPort_7409306_1 | SOURCE | Esgoto Sanitário 65
InPort_7409360_1 | SINK | Esgoto Sanitário 68
OutPort_7409382_2 | SOURCE | Esgoto Sanitário 68
InPort_7409382_1 | SINK | Esgoto Sanitário 68
OutPort_7409376_0 | SOURCE | Esgoto Sanitário 68
InPort_7409376_1 | SINK | Esgoto Sanitário 68
OutPort_7409395_1 | SOURCE | Esgoto Sanitário 68
InPort_7409392_0 | SINK | Esgoto Sanitário 68
InPort_7409395_2 | SINK | Esgoto Sanitário 68
OutPort_7409392_1 | SOURCE | Esgoto Sanitário 68
InPort_7409821_1 | SINK | Esgoto Sanitário 83
InPort_7409821_2 | SINK
InPort_7409821_3 | SINK | Esgoto Sanitário 85
OutPort_7480440_1 | SOURCE | Esgoto Sanitário 85
InPort_7479980_0 | SINK | Esgoto Sanitário 69
OutPort_7409821_4 | SOURCE | Esgoto Sanitário 69
InPort_7409821_5 | SINK
OutPort_7411241_3 | SOURCE | Esgoto Sanitário 73
InPort_7411241_4 | SINK
InPort_7411241_5 | SINK
InPort_7411241_6 | SINK | Esgoto Sanitário 19
OutPort_7506964_0 | SOURCE | Esgoto Sanitário 19
InPort_7411241_7 | SINK
InPort_7411241_8 | SINK
InPort_7411241_9 | SINK
InPort_7411241_10 | SINK
InPort_7411241_11 | SINK
InPort_7411241_12 | SINK
Port_7411528_0 | SOURCEANDSINK | Esgoto Sanitário 71
Port_7411528_1 | SOURCEANDSINK | Esgoto Sanitário 71
OutPort_7411687_1 | SOURCE | Esgoto Sanitário 72
InPort_7412038_0 | SINK | Esgoto - Ventilação 5
OutPort_7412059_2 | SOURCE | Esgoto - Ventilação 5
InPort_7412078_1 | SINK | Esgoto - Ventilação 5
OutPort_7412038_1 | SOURCE | Esgoto - Ventilação 5
InPort_7412045_0 | SINK | Esgoto - Ventilação 5
OutPort_7412047_3 | SOURCE | Esgoto - Ventilação 5
InPort_7412059_1 | SINK | Esgoto - Ventilação 5
OutPort_7412045_1 | SOURCE | Esgoto - Ventilação 5
InPort_7412047_2 | SINK | Esgoto Sanitário 33
OutPort_7412048_1 | SOURCE | Esgoto Sanitário 33
InPort_7412075_0 | SINK | Esgoto - Ventilação 5
OutPort_7412078_2 | SOURCE | Esgoto - Ventilação 5
InPort_7412169_1 | SINK | Esgoto - Ventilação 5
OutPort_7412075_1 | SOURCE | Esgoto - Ventilação 5
InPort_7412163_0 | SINK | Esgoto - Ventilação 5
OutPort_7412169_2 | SOURCE | Esgoto - Ventilação 5
InPort_7412185_1 | SINK | Esgoto - Ventilação 5
OutPort_7412163_1 | SOURCE | Esgoto - Ventilação 5
InPort_7412179_0 | SINK | Esgoto - Ventilação 5
OutPort_7412185_2 | SOURCE | Esgoto - Ventilação 5
InPort_7412237_1 | SINK | Esgoto - Ventilação 5
OutPort_7412179_1 | SOURCE | Esgoto - Ventilação 5
InPort_7412314_2 | SINK | Esgoto Sanitário 36
OutPort_7412315_1 | SOURCE | Esgoto Sanitário 36
Port_7412314_3 | SOURCEANDSINK | Esgoto Sanitário 36
InPort_7412444_0 | SINK | Esgoto - Ventilação 10
OutPort_7412483_2 | SOURCE | Esgoto - Ventilação 10
InPort_7412499_2 | SINK | Esgoto - Ventilação 10
OutPort_7412444_1 | SOURCE | Esgoto - Ventilação 10
InPort_7412464_0 | SINK | Esgoto - Ventilação 10
OutPort_7412470_3 | SOURCE | Esgoto - Ventilação 10
InPort_7412483_1 | SINK | Esgoto - Ventilação 10
OutPort_7412464_1 | SOURCE | Esgoto - Ventilação 10
InPort_7412470_2 | SINK | Esgoto Sanitário 27
OutPort_7412471_1 | SOURCE | Esgoto Sanitário 27
InPort_7412493_0 | SINK | Esgoto - Ventilação 10
OutPort_7412499_1 | SOURCE | Esgoto - Ventilação 10
InPort_7412521_1 | SINK | Esgoto - Ventilação 10
OutPort_7412493_1 | SOURCE | Esgoto - Ventilação 10
InPort_7412518_0 | SINK | Esgoto - Ventilação 10
OutPort_7412521_2 | SOURCE | Esgoto - Ventilação 10
InPort_7412696_1 | SINK | Esgoto - Ventilação 10
OutPort_7412518_1 | SOURCE | Esgoto - Ventilação 10
InPort_7412688_0 | SINK | Esgoto - Ventilação 10
OutPort_7412696_2 | SOURCE | Esgoto - Ventilação 10
InPort_7412712_1 | SINK | Esgoto - Ventilação 10
OutPort_7412688_1 | SOURCE | Esgoto - Ventilação 10
InPort_7412706_0 | SINK | Esgoto - Ventilação 10
OutPort_7412712_2 | SOURCE | Esgoto - Ventilação 10
InPort_7412741_1 | SINK | Esgoto - Ventilação 10
OutPort_7412706_1 | SOURCE | Esgoto - Ventilação 10
InPort_7413010_0 | SINK | Esgoto - Ventilação 11
OutPort_7413031_2 | SOURCE | Esgoto - Ventilação 11
InPort_7413047_2 | SINK | Esgoto - Ventilação 11
OutPort_7413010_1 | SOURCE | Esgoto - Ventilação 11
InPort_7413017_0 | SINK | Esgoto - Ventilação 11
OutPort_7413019_3 | SOURCE | Esgoto - Ventilação 11
InPort_7413031_1 | SINK | Esgoto - Ventilação 11
OutPort_7413017_1 | SOURCE | Esgoto - Ventilação 11
InPort_7413019_2 | SINK | Esgoto Sanitário 43
OutPort_7413020_1 | SOURCE | Esgoto Sanitário 43
InPort_7413041_0 | SINK | Esgoto - Ventilação 11
OutPort_7413047_1 | SOURCE | Esgoto - Ventilação 11
InPort_7413066_1 | SINK | Esgoto - Ventilação 11
OutPort_7413041_1 | SOURCE | Esgoto - Ventilação 11
InPort_7413063_0 | SINK | Esgoto - Ventilação 11
OutPort_7413066_2 | SOURCE | Esgoto - Ventilação 11
InPort_7413205_1 | SINK | Esgoto - Ventilação 11
OutPort_7413063_1 | SOURCE | Esgoto - Ventilação 11
InPort_7413258_0 | SINK | Esgoto - Ventilação 12
OutPort_7413283_2 | SOURCE | Esgoto - Ventilação 12
InPort_7413309_1 | SINK | Esgoto - Ventilação 12
OutPort_7413258_1 | SOURCE | Esgoto - Ventilação 12
InPort_7413269_0 | SINK | Esgoto - Ventilação 12
OutPort_7413271_3 | SOURCE | Esgoto - Ventilação 12
InPort_7413283_1 | SINK | Esgoto - Ventilação 12
OutPort_7413269_1 | SOURCE | Esgoto - Ventilação 12
InPort_7413271_2 | SINK | Esgoto Sanitário 43
OutPort_7413272_1 | SOURCE | Esgoto Sanitário 43
InPort_7413306_0 | SINK | Esgoto - Ventilação 12
OutPort_7413309_2 | SOURCE | Esgoto - Ventilação 12
InPort_7413462_1 | SINK | Esgoto - Ventilação 12
OutPort_7413306_1 | SOURCE | Esgoto - Ventilação 12
InPort_7413454_0 | SINK | Esgoto - Ventilação 12
OutPort_7413462_2 | SOURCE | Esgoto - Ventilação 12
InPort_7413478_1 | SINK | Esgoto - Ventilação 12
OutPort_7413454_1 | SOURCE | Esgoto - Ventilação 12
InPort_7413472_0 | SINK | Esgoto - Ventilação 12
OutPort_7413478_2 | SOURCE | Esgoto - Ventilação 12
InPort_7413508_1 | SINK | Esgoto - Ventilação 12
OutPort_7413472_1 | SOURCE | Esgoto - Ventilação 12
InPort_7413529_0 | SINK | Esgoto - Ventilação 13
OutPort_7413550_2 | SOURCE | Esgoto - Ventilação 13
InPort_7413569_1 | SINK | Esgoto - Ventilação 13
OutPort_7413529_1 | SOURCE | Esgoto - Ventilação 13
InPort_7413536_0 | SINK | Esgoto - Ventilação 13
OutPort_7413538_3 | SOURCE | Esgoto - Ventilação 13
InPort_7413550_1 | SINK | Esgoto - Ventilação 13
OutPort_7413536_1 | SOURCE | Esgoto - Ventilação 13
InPort_7413538_2 | SINK | Esgoto Sanitário 52
OutPort_7413539_1 | SOURCE | Esgoto Sanitário 52
InPort_7413566_0 | SINK | Esgoto - Ventilação 13
OutPort_7413569_2 | SOURCE | Esgoto - Ventilação 13
InPort_7413638_1 | SINK | Esgoto - Ventilação 13
OutPort_7413566_1 | SOURCE | Esgoto - Ventilação 13
InPort_7413630_0 | SINK | Esgoto - Ventilação 13
OutPort_7413638_2 | SOURCE | Esgoto - Ventilação 13
InPort_7413654_1 | SINK | Esgoto - Ventilação 13
OutPort_7413630_1 | SOURCE | Esgoto - Ventilação 13
InPort_7413648_0 | SINK | Esgoto - Ventilação 13
OutPort_7413654_2 | SOURCE | Esgoto - Ventilação 13
InPort_7413683_1 | SINK | Esgoto - Ventilação 13
OutPort_7413648_1 | SOURCE | Esgoto - Ventilação 13
InPort_7413799_0 | SINK | Esgoto - Ventilação 14
OutPort_7413822_2 | SOURCE | Esgoto - Ventilação 14
InPort_7413839_1 | SINK | Esgoto - Ventilação 14
OutPort_7413799_1 | SOURCE | Esgoto - Ventilação 14
InPort_7413808_0 | SINK | Esgoto - Ventilação 14
OutPort_7413810_3 | SOURCE | Esgoto - Ventilação 14
InPort_7413822_1 | SINK | Esgoto - Ventilação 14
OutPort_7413808_1 | SOURCE | Esgoto - Ventilação 14
InPort_7413810_2 | SINK | Esgoto Sanitário 56
OutPort_7413811_1 | SOURCE | Esgoto Sanitário 56
InPort_7413833_0 | SINK | Esgoto - Ventilação 14
OutPort_7413839_2 | SOURCE | Esgoto - Ventilação 14
InPort_7413862_1 | SINK | Esgoto - Ventilação 14
OutPort_7413833_1 | SOURCE | Esgoto - Ventilação 14
InPort_7413859_0 | SINK | Esgoto - Ventilação 14
OutPort_7413862_2 | SOURCE | Esgoto - Ventilação 14
InPort_7413941_1 | SINK | Esgoto - Ventilação 14
OutPort_7413859_1 | SOURCE | Esgoto - Ventilação 14
InPort_7413933_0 | SINK | Esgoto - Ventilação 14
OutPort_7413941_2 | SOURCE | Esgoto - Ventilação 14
InPort_7413957_1 | SINK | Esgoto - Ventilação 14
OutPort_7413933_1 | SOURCE | Esgoto - Ventilação 14
InPort_7413951_0 | SINK | Esgoto - Ventilação 14
OutPort_7413957_2 | SOURCE | Esgoto - Ventilação 14
InPort_7413991_1 | SINK | Esgoto - Ventilação 14
OutPort_7413951_1 | SOURCE | Esgoto - Ventilação 14
InPort_7414020_0 | SINK | Esgoto - Ventilação 16
OutPort_7414208_3 | SOURCE | Esgoto - Ventilação 16
InPort_7414233_1 | SINK | Esgoto - Ventilação 16
OutPort_7414020_1 | SOURCE | Esgoto - Ventilação 16
InPort_7414024_0 | SINK | Esgoto Sanitário 63
OutPort_7414208_1 | SOURCE | Esgoto Sanitário 63
InPort_7505487_1 | SINK | Esgoto Sanitário 63
OutPort_7414024_1 | SOURCE | Esgoto Sanitário 63
InPort_7414208_2 | SINK | Esgoto Sanitário 63
OutPort_7414209_1 | SOURCE | Esgoto Sanitário 63
InPort_7414225_0 | SINK | Esgoto - Ventilação 16
OutPort_7414233_2 | SOURCE | Esgoto - Ventilação 16
InPort_7414249_1 | SINK | Esgoto - Ventilação 16
OutPort_7414225_1 | SOURCE | Esgoto - Ventilação 16
InPort_7414243_0 | SINK | Esgoto - Ventilação 16
OutPort_7414249_2 | SOURCE | Esgoto - Ventilação 16
InPort_7414279_1 | SINK | Esgoto - Ventilação 16
OutPort_7414243_1 | SOURCE | Esgoto - Ventilação 16
InPort_7414809_1 | SINK | Esgoto Sanitário 75
InPort_7414847_0 | SINK | Esgoto - Ventilação 15
OutPort_7414870_2 | SOURCE | Esgoto - Ventilação 15
InPort_7414886_1 | SINK | Esgoto - Ventilação 15
OutPort_7414847_1 | SOURCE | Esgoto - Ventilação 15
InPort_7414856_0 | SINK | Esgoto - Ventilação 15
OutPort_7414858_3 | SOURCE | Esgoto - Ventilação 15
InPort_7414870_1 | SINK | Esgoto - Ventilação 15
OutPort_7414856_1 | SOURCE | Esgoto - Ventilação 15
InPort_7414858_2 | SINK | Esgoto Sanitário 6
OutPort_7414859_1 | SOURCE | Esgoto Sanitário 6
InPort_7414880_0 | SINK | Esgoto - Ventilação 15
OutPort_7414886_2 | SOURCE | Esgoto - Ventilação 15
InPort_7414905_1 | SINK | Esgoto - Ventilação 15
OutPort_7414880_1 | SOURCE | Esgoto - Ventilação 15
InPort_7415004_1 | SINK | Esgoto - Ventilação 15
OutPort_7414902_0 | SOURCE | Esgoto - Ventilação 15
InPort_7414902_1 | SINK | Esgoto - Ventilação 15
OutPort_7414905_2 | SOURCE | Esgoto - Ventilação 15
InPort_7415421_1 | SINK | Esgoto Sanitário 5
InPort_7415459_0 | SINK | Esgoto - Ventilação 19
OutPort_7415519_3 | SOURCE | Esgoto - Ventilação 19
InPort_7415538_1 | SINK | Esgoto - Ventilação 19
OutPort_7415459_1 | SOURCE | Esgoto - Ventilação 19
InPort_7415463_0 | SINK | Esgoto Sanitário 1
OutPort_7415519_1 | SOURCE | Esgoto Sanitário 1
InPort_7415519_2 | SINK | Esgoto Sanitário 1
OutPort_7415520_1 | SOURCE | Esgoto Sanitário 1
InPort_7415532_0 | SINK | Esgoto - Ventilação 19
OutPort_7415538_2 | SOURCE | Esgoto - Ventilação 19
InPort_7415554_1 | SINK | Esgoto - Ventilação 19
OutPort_7415532_1 | SOURCE | Esgoto - Ventilação 19
InPort_7415548_0 | SINK | Esgoto - Ventilação 19
OutPort_7415554_2 | SOURCE | Esgoto - Ventilação 19
InPort_7415583_1 | SINK | Esgoto - Ventilação 19
OutPort_7415548_1 | SOURCE | Esgoto - Ventilação 19
InPort_7415914_1 | SINK | Esgoto Sanitário 76
InPort_7416094_1 | SINK | Água Fria - Extravasor e Limpeza 1
OutPort_7416091_2 | SOURCE | Água Fria - Extravasor e Limpeza 1
InPort_7417016_2 | SINK | Água Fria 9
OutPort_7417019_1 | SOURCE | Água Fria 9
InPort_7417941_0 | SINK | Água Pluvial 2
OutPort_7417940_1 | SOURCE | Água Pluvial 2
InPort_7418412_1 | SINK | Água Pluvial 2
OutPort_7417941_1 | SOURCE | Água Pluvial 2
InPort_7417943_0 | SINK | Água Pluvial 2
OutPort_7418412_2 | SOURCE | Água Pluvial 2
InPort_7418434_2 | SINK | Água Pluvial 2
OutPort_7417943_1 | SOURCE | Água Pluvial 2
InPort_7417947_0 | SINK | Água Pluvial 2
OutPort_7418434_1 | SOURCE | Água Pluvial 2
InPort_7418469_1 | SINK | Água Pluvial 2
OutPort_7417947_1 | SOURCE | Água Pluvial 2
InPort_7417951_0 | SINK | Água Pluvial 2
OutPort_7418469_2 | SOURCE | Água Pluvial 2
OutPort_7417951_1 | SOURCE | Água Pluvial 2
InPort_7418822_0 | SINK | Água Pluvial 3
OutPort_7418821_1 | SOURCE | Água Pluvial 3
InPort_7418830_1 | SINK | Água Pluvial 3
OutPort_7418822_1 | SOURCE | Água Pluvial 3
InPort_7418824_0 | SINK | Água Pluvial 3
OutPort_7418830_2 | SOURCE | Água Pluvial 3
InPort_7418832_2 | SINK | Água Pluvial 3
OutPort_7418824_1 | SOURCE | Água Pluvial 3
InPort_7418826_0 | SINK | Água Pluvial 3
OutPort_7418832_1 | SOURCE | Água Pluvial 3
InPort_7418834_1 | SINK | Água Pluvial 3
OutPort_7418826_1 | SOURCE | Água Pluvial 3
InPort_7418828_0 | SINK | Água Pluvial 3
OutPort_7418834_2 | SOURCE | Água Pluvial 3
OutPort_7418828_1 | SOURCE | Água Pluvial 3
InPort_7419044_0 | SINK | Água Pluvial 4
OutPort_7419043_1 | SOURCE | Água Pluvial 4
InPort_7419048_1 | SINK | Água Pluvial 4
OutPort_7419044_1 | SOURCE | Água Pluvial 4
InPort_7419046_0 | SINK | Água Pluvial 4
OutPort_7419048_2 | SOURCE | Água Pluvial 4
InPort_7419052_1 | SINK | Água Pluvial 4
OutPort_7419046_1 | SOURCE | Água Pluvial 4
InPort_7419050_0 | SINK | Água Pluvial 4
OutPort_7419052_2 | SOURCE | Água Pluvial 4
InPort_7419056_1 | SINK | Água Pluvial 4
OutPort_7419050_1 | SOURCE | Água Pluvial 4
OutPort_7419056_2 | SOURCE | Água Pluvial 4
InPort_7419068_0 | SINK | Água Pluvial 5
OutPort_7419067_1 | SOURCE | Água Pluvial 5
InPort_7419072_1 | SINK | Água Pluvial 5
OutPort_7419068_1 | SOURCE | Água Pluvial 5
InPort_7419070_0 | SINK | Água Pluvial 5
OutPort_7419072_2 | SOURCE | Água Pluvial 5
InPort_7419076_1 | SINK | Água Pluvial 5
OutPort_7419070_1 | SOURCE | Água Pluvial 5
InPort_7419074_0 | SINK | Água Pluvial 5
OutPort_7419076_2 | SOURCE | Água Pluvial 5
InPort_7419080_1 | SINK | Água Pluvial 5
OutPort_7419074_1 | SOURCE | Água Pluvial 5
OutPort_7419080_2 | SOURCE | Água Pluvial 5
InPort_7419108_0 | SINK | Água Pluvial 6
OutPort_7419107_1 | SOURCE | Água Pluvial 6
InPort_7419264_1 | SINK | Água Pluvial 6
OutPort_7419108_1 | SOURCE | Água Pluvial 6
InPort_7419110_0 | SINK | Água Pluvial 6
OutPort_7419264_2 | SOURCE | Água Pluvial 6
InPort_7419470_2 | SINK | Água Pluvial 6
OutPort_7419110_1 | SOURCE | Água Pluvial 6
InPort_7419114_0 | SINK | Água Pluvial 6
OutPort_7419323_1 | SOURCE | Água Pluvial 6
InPort_7419120_1 | SINK | Água Pluvial 6
OutPort_7419114_1 | SOURCE | Água Pluvial 6
OutPort_7419120_2 | SOURCE | Água Pluvial 6
InPort_7419323_2 | SINK | Água Pluvial 6
OutPort_7419269_0 | SOURCE | Água Pluvial 6
InPort_7419269_1 | SINK | Água Pluvial 6
OutPort_7419470_1 | SOURCE | Água Pluvial 6
InPort_7419507_0 | SINK | Água Pluvial 7
OutPort_7419506_1 | SOURCE | Água Pluvial 7
InPort_7419517_1 | SINK | Água Pluvial 7
OutPort_7419507_1 | SOURCE | Água Pluvial 7
InPort_7419509_0 | SINK | Água Pluvial 7
OutPort_7419517_2 | SOURCE | Água Pluvial 7
InPort_7419523_2 | SINK | Água Pluvial 7
OutPort_7419509_1 | SOURCE | Água Pluvial 7
InPort_7419511_0 | SINK | Água Pluvial 7
OutPort_7419521_1 | SOURCE | Água Pluvial 7
InPort_7419515_1 | SINK | Água Pluvial 7
OutPort_7419511_1 | SOURCE | Água Pluvial 7
OutPort_7419515_2 | SOURCE | Água Pluvial 7
InPort_7419521_2 | SINK | Água Pluvial 7
OutPort_7419519_0 | SOURCE | Água Pluvial 7
InPort_7419519_1 | SINK | Água Pluvial 7
OutPort_7419523_1 | SOURCE | Água Pluvial 7
InPort_7420571_0 | SINK | Água Pluvial 15
OutPort_7420570_1 | SOURCE | Água Pluvial 15
InPort_7420816_1 | SINK | Água Pluvial 15
OutPort_7420571_1 | SOURCE | Água Pluvial 15
InPort_7420573_0 | SINK | Água Pluvial 15
OutPort_7420816_2 | SOURCE | Água Pluvial 15
InPort_7421032_1 | SINK | Água Pluvial 15
OutPort_7420573_1 | SOURCE | Água Pluvial 15
InPort_7420823_0 | SINK | Água Pluvial 15
OutPort_7421032_2 | SOURCE | Água Pluvial 15
InPort_7421063_1 | SINK | Água Pluvial 15
OutPort_7420823_1 | SOURCE | Água Pluvial 15
InPort_7421055_0 | SINK | Água Pluvial 15
OutPort_7421063_2 | SOURCE | Água Pluvial 15
InPort_7421108_1 | SINK | Água Pluvial 15
OutPort_7421055_1 | SOURCE | Água Pluvial 15
OutPort_7421108_2 | SOURCE | Água Pluvial 15
InPort_7421404_0 | SINK | Água Pluvial 17
OutPort_7421403_1 | SOURCE | Água Pluvial 17
InPort_7421408_1 | SINK | Água Pluvial 17
OutPort_7421404_1 | SOURCE | Água Pluvial 17
InPort_7421406_0 | SINK | Água Pluvial 17
OutPort_7421408_2 | SOURCE | Água Pluvial 17
InPort_7421412_1 | SINK | Água Pluvial 17
OutPort_7421406_1 | SOURCE | Água Pluvial 17
InPort_7421410_0 | SINK | Água Pluvial 17
OutPort_7421412_2 | SOURCE | Água Pluvial 17
InPort_7421416_1 | SINK | Água Pluvial 17
OutPort_7421410_1 | SOURCE | Água Pluvial 17
InPort_7421414_0 | SINK | Água Pluvial 17
OutPort_7421416_2 | SOURCE | Água Pluvial 17
InPort_7421457_1 | SINK | Água Pluvial 17
OutPort_7421414_1 | SOURCE | Água Pluvial 17
OutPort_7421457_2 | SOURCE | Água Pluvial 17
InPort_7422312_0 | SINK | Água Pluvial 18
OutPort_7422311_1 | SOURCE | Água Pluvial 18
InPort_7422320_1 | SINK | Água Pluvial 18
OutPort_7422312_1 | SOURCE | Água Pluvial 18
InPort_7422314_0 | SINK | Água Pluvial 18
OutPort_7422320_2 | SOURCE | Água Pluvial 18
InPort_7422322_2 | SINK | Água Pluvial 18
OutPort_7422314_1 | SOURCE | Água Pluvial 18
InPort_7422316_0 | SINK | Água Pluvial 18
OutPort_7422322_1 | SOURCE | Água Pluvial 18
InPort_7422324_1 | SINK | Água Pluvial 18
OutPort_7422316_1 | SOURCE | Água Pluvial 18
InPort_7422318_0 | SINK | Água Pluvial 18
OutPort_7422324_2 | SOURCE | Água Pluvial 18
OutPort_7422318_1 | SOURCE | Água Pluvial 18
Port_7424440_1 | SOURCEANDSINK
Port_7424440_2 | SOURCEANDSINK
Port_7424489_0 | SOURCEANDSINK | Dreno Ar 3
Port_7440947_2 | SOURCEANDSINK | Dreno Ar 3
Port_7424489_1 | SOURCEANDSINK | Dreno Ar 3
Port_7440964_2 | SOURCEANDSINK | Dreno Ar 3
Port_7424491_1 | SOURCEANDSINK | Dreno Ar 3
Port_7424495_0 | SOURCEANDSINK | Dreno Ar 3
Port_7424491_2 | SOURCEANDSINK | Dreno Ar 3
Port_7424493_0 | SOURCEANDSINK | Dreno Ar 3
Port_7424497_2 | SOURCEANDSINK | Dreno Ar 3
Port_7424493_1 | SOURCEANDSINK | Dreno Ar 3
Port_7440947_1 | SOURCEANDSINK | Dreno Ar 3
Port_7424495_1 | SOURCEANDSINK | Dreno Ar 3
Port_7424497_1 | SOURCEANDSINK | Dreno Ar 3
InPort_7426250_1 | SINK | Esgoto Sanitário 79
InPort_7427211_2 | SINK | Água Fria - Extravasor e Limpeza 1
OutPort_7427189_1 | SOURCE | Água Fria - Extravasor e Limpeza 1
InPort_7429220_1 | SINK | Água Fria - Extravasor e Limpeza 1
OutPort_7429214_2 | SOURCE | Água Fria - Extravasor e Limpeza 1
InPort_7432432_1 | SINK | Água Fria 1
OutPort_7432426_2 | SOURCE | Água Fria 1
InPort_7432856_0 | SINK | Água Fria Alimentação 5
OutPort_7449886_1 | SOURCE | Água Fria Alimentação 5
InPort_7432859_2 | SINK | Água Fria Alimentação 5
OutPort_7432856_1 | SOURCE | Água Fria Alimentação 5
InPort_7475143_0 | SINK | Água Fria Alimentação 5
OutPort_7432859_1 | SOURCE | Água Fria Alimentação 5
InPort_7434855_2 | SINK | Água Fria - Extravasor e Limpeza 1
OutPort_7434857_1 | SOURCE | Água Fria - Extravasor e Limpeza 1
InPort_7434999_2 | SINK | Água Fria - Extravasor e Limpeza 1
OutPort_7435001_1 | SOURCE | Água Fria - Extravasor e Limpeza 1
InPort_7435403_2 | SINK | Água Fria 9
OutPort_7435405_1 | SOURCE | Água Fria 9
InPort_7435463_1 | SINK | Água Fria 1
OutPort_7435461_2 | SOURCE | Água Fria 1
InPort_7435879_1 | SINK | Água Fria - Extravasor e Limpeza 2
OutPort_7436959_0 | SOURCE | Água Fria - Extravasor e Limpeza 2
InPort_7435879_2 | SINK | Água Fria - Extravasor e Limpeza 2
OutPort_7436973_1 | SOURCE | Água Fria - Extravasor e Limpeza 2
InPort_7436766_0 | SINK | Água Fria - Extravasor e Limpeza 2
OutPort_7435879_3 | SOURCE | Água Fria - Extravasor e Limpeza 2
Port_7435984_1 | SOURCEANDSINK | Água Fria - Extravasor e Limpeza 2
Port_7436000_1 | SOURCEANDSINK | Água Fria - Extravasor e Limpeza 2
Port_7435992_0 | SOURCEANDSINK | Água Fria - Extravasor e Limpeza 2
Port_7436000_2 | SOURCEANDSINK | Água Fria - Extravasor e Limpeza 2
Port_7435992_1 | SOURCEANDSINK | Água Fria - Extravasor e Limpeza 2
Port_7436934_1 | SOURCEANDSINK | Água Fria - Extravasor e Limpeza 2
Port_7436002_0 | SOURCEANDSINK | Água Fria - Extravasor e Limpeza 2
Port_7436934_2 | SOURCEANDSINK | Água Fria - Extravasor e Limpeza 2
Port_7436002_1 | SOURCEANDSINK | Água Fria - Extravasor e Limpeza 2
Port_7436557_2 | SOURCEANDSINK | Água Fria - Extravasor e Limpeza 2
Port_7436305_0 | SOURCEANDSINK | Água Fria - Extravasor e Limpeza 2
Port_7436563_2 | SOURCEANDSINK | Água Fria - Extravasor e Limpeza 2
Port_7436305_1 | SOURCEANDSINK | Água Fria - Extravasor e Limpeza 2
Port_7436557_3 | SOURCEANDSINK | Água Fria - Extravasor e Limpeza 2
Port_7436348_0 | SOURCEANDSINK | Água Fria - Extravasor e Limpeza 2
Port_7436563_1 | SOURCEANDSINK | Água Fria - Extravasor e Limpeza 2
Port_7436348_1 | SOURCEANDSINK | Água Fria - Extravasor e Limpeza 2
Port_7436398_1 | SOURCEANDSINK | Água Fria - Extravasor e Limpeza 2
Port_7436386_0 | SOURCEANDSINK | Água Fria - Extravasor e Limpeza 2
Port_7436398_2 | SOURCEANDSINK | Água Fria - Extravasor e Limpeza 2
Port_7436386_1 | SOURCEANDSINK | Água Fria - Extravasor e Limpeza 2
InPort_7436546_1 | SINK | Água Fria - Extravasor e Limpeza 2
OutPort_7436993_0 | SOURCE | Água Fria - Extravasor e Limpeza 2
InPort_7436558_0 | SINK | Água Fria - Extravasor e Limpeza 2
OutPort_7436546_2 | SOURCE | Água Fria - Extravasor e Limpeza 2
InPort_7436557_1 | SINK | Água Fria - Extravasor e Limpeza 2
OutPort_7436558_1 | SOURCE | Água Fria - Extravasor e Limpeza 2
InPort_7436991_1 | SINK | Água Fria - Extravasor e Limpeza 2
OutPort_7436766_1 | SOURCE | Água Fria - Extravasor e Limpeza 2
InPort_7436993_1 | SINK | Água Fria - Extravasor e Limpeza 2
OutPort_7436991_2 | SOURCE | Água Fria - Extravasor e Limpeza 2
InPort_7439104_0 | SINK | Água Fria Alimentação 5
OutPort_7439112_2 | SOURCE | Água Fria Alimentação 5
InPort_7449845_1 | SINK | Água Fria Alimentação 5
OutPort_7439104_1 | SOURCE | Água Fria Alimentação 5
InPort_7439112_1 | SINK | Água Fria Alimentação 5
OutPort_7451251_0 | SOURCE | Água Fria Alimentação 5
InPort_7439256_1 | SINK | Água Fria Alimentação 2
Port_7440521_1 | SOURCEANDSINK
Port_7440521_2 | SOURCEANDSINK
Port_7440522_0 | SOURCEANDSINK | Dreno Ar 2
Port_7440693_2 | SOURCEANDSINK | Dreno Ar 2
Port_7440522_1 | SOURCEANDSINK | Dreno Ar 2
Port_7440710_1 | SOURCEANDSINK | Dreno Ar 2
Port_7440524_1 | SOURCEANDSINK | Dreno Ar 2
Port_7440528_0 | SOURCEANDSINK | Dreno Ar 2
Port_7440524_2 | SOURCEANDSINK | Dreno Ar 2
Port_7440526_0 | SOURCEANDSINK | Dreno Ar 2
Port_7440530_2 | SOURCEANDSINK | Dreno Ar 2
Port_7440526_1 | SOURCEANDSINK | Dreno Ar 2
Port_7440693_1 | SOURCEANDSINK | Dreno Ar 2
Port_7440528_1 | SOURCEANDSINK | Dreno Ar 2
Port_7440530_1 | SOURCEANDSINK | Dreno Ar 2
Port_7440630_1 | SOURCEANDSINK
Port_7440630_2 | SOURCEANDSINK
Port_7440648_0 | SOURCEANDSINK | Dreno Ar 2
Port_7440916_2 | SOURCEANDSINK | Dreno Ar 2
Port_7440648_1 | SOURCEANDSINK | Dreno Ar 2
Port_7440920_2 | SOURCEANDSINK | Dreno Ar 2
Port_7440650_1 | SOURCEANDSINK | Dreno Ar 2
Port_7440654_0 | SOURCEANDSINK | Dreno Ar 2
Port_7440650_2 | SOURCEANDSINK | Dreno Ar 2
Port_7440652_0 | SOURCEANDSINK | Dreno Ar 2
Port_7440656_2 | SOURCEANDSINK | Dreno Ar 2
Port_7440652_1 | SOURCEANDSINK | Dreno Ar 2
Port_7440916_1 | SOURCEANDSINK | Dreno Ar 2
Port_7440654_1 | SOURCEANDSINK | Dreno Ar 2
Port_7440656_1 | SOURCEANDSINK | Dreno Ar 2
Port_7440699_0 | SOURCEANDSINK | Dreno Ar 2
Port_7440908_1 | SOURCEANDSINK | Dreno Ar 2
Port_7440699_1 | SOURCEANDSINK | Dreno Ar 2
Port_7440722_2 | SOURCEANDSINK | Dreno Ar 2
Port_7440710_2 | SOURCEANDSINK | Dreno Ar 2
Port_7440909_0 | SOURCEANDSINK | Dreno Ar 2
Port_7440712_0 | SOURCEANDSINK | Dreno Ar 2
Port_7440722_1 | SOURCEANDSINK | Dreno Ar 2
Port_7440712_1 | SOURCEANDSINK | Dreno Ar 2
Port_7440906_0 | SOURCEANDSINK | Dreno Ar 2
Port_7440908_3 | SOURCEANDSINK | Dreno Ar 2
Port_7440906_1 | SOURCEANDSINK | Dreno Ar 2
Port_7440920_1 | SOURCEANDSINK | Dreno Ar 2
Port_7440908_2 | SOURCEANDSINK | Dreno Ar 2
Port_7440909_1 | SOURCEANDSINK | Dreno Ar 2
Port_7440953_0 | SOURCEANDSINK | Dreno Ar 3
Port_7440964_1 | SOURCEANDSINK | Dreno Ar 3
Port_7440953_1 | SOURCEANDSINK | Dreno Ar 3
Port_7440989_1 | SOURCEANDSINK
Port_7440989_2 | SOURCEANDSINK
Port_7440990_0 | SOURCEANDSINK | Dreno Ar 4
Port_7441000_2 | SOURCEANDSINK | Dreno Ar 4
Port_7440990_1 | SOURCEANDSINK | Dreno Ar 4
Port_7440992_1 | SOURCEANDSINK | Dreno Ar 4
Port_7440996_0 | SOURCEANDSINK | Dreno Ar 4
Port_7440992_2 | SOURCEANDSINK | Dreno Ar 4
Port_7440994_0 | SOURCEANDSINK | Dreno Ar 4
Port_7440998_2 | SOURCEANDSINK | Dreno Ar 4
Port_7440994_1 | SOURCEANDSINK | Dreno Ar 4
Port_7441000_1 | SOURCEANDSINK | Dreno Ar 4
Port_7440996_1 | SOURCEANDSINK | Dreno Ar 4
Port_7440998_1 | SOURCEANDSINK | Dreno Ar 4
Port_7441154_1 | SOURCEANDSINK
Port_7441154_2 | SOURCEANDSINK
Port_7441155_0 | SOURCEANDSINK | Dreno Ar 6
Port_7441187_2 | SOURCEANDSINK | Dreno Ar 6
Port_7441155_1 | SOURCEANDSINK | Dreno Ar 6
Port_7441214_1 | SOURCEANDSINK | Dreno Ar 6
Port_7441157_1 | SOURCEANDSINK | Dreno Ar 6
Port_7441161_0 | SOURCEANDSINK | Dreno Ar 6
Port_7441157_2 | SOURCEANDSINK | Dreno Ar 6
Port_7441159_0 | SOURCEANDSINK | Dreno Ar 6
Port_7441163_2 | SOURCEANDSINK | Dreno Ar 6
Port_7441159_1 | SOURCEANDSINK | Dreno Ar 6
Port_7441187_1 | SOURCEANDSINK | Dreno Ar 6
Port_7441161_1 | SOURCEANDSINK | Dreno Ar 6
Port_7441163_1 | SOURCEANDSINK | Dreno Ar 6
Port_7441206_0 | SOURCEANDSINK | Dreno Ar 6
Port_7441214_2 | SOURCEANDSINK | Dreno Ar 6
Port_7441206_1 | SOURCEANDSINK | Dreno Ar 6
Port_7441452_1 | SOURCEANDSINK
Port_7441452_2 | SOURCEANDSINK
Port_7441453_0 | SOURCEANDSINK | Dreno Ar 5
Port_7441654_2 | SOURCEANDSINK | Dreno Ar 5
Port_7441453_1 | SOURCEANDSINK | Dreno Ar 5
Port_7441667_2 | SOURCEANDSINK | Dreno Ar 5
Port_7441455_1 | SOURCEANDSINK | Dreno Ar 5
Port_7441459_0 | SOURCEANDSINK | Dreno Ar 5
Port_7441455_2 | SOURCEANDSINK | Dreno Ar 5
Port_7441457_0 | SOURCEANDSINK | Dreno Ar 5
Port_7441461_2 | SOURCEANDSINK | Dreno Ar 5
Port_7441457_1 | SOURCEANDSINK | Dreno Ar 5
Port_7441654_1 | SOURCEANDSINK | Dreno Ar 5
Port_7441459_1 | SOURCEANDSINK | Dreno Ar 5
Port_7441461_1 | SOURCEANDSINK | Dreno Ar 5
Port_7441477_1 | SOURCEANDSINK
Port_7441477_2 | SOURCEANDSINK
Port_7441478_0 | SOURCEANDSINK | Dreno Ar 7
Port_7441569_2 | SOURCEANDSINK | Dreno Ar 7
Port_7441478_1 | SOURCEANDSINK | Dreno Ar 7
Port_7441480_1 | SOURCEANDSINK | Dreno Ar 7
Port_7441484_0 | SOURCEANDSINK | Dreno Ar 7
Port_7441480_2 | SOURCEANDSINK | Dreno Ar 7
Port_7441482_0 | SOURCEANDSINK | Dreno Ar 7
Port_7441486_2 | SOURCEANDSINK | Dreno Ar 7
Port_7441482_1 | SOURCEANDSINK | Dreno Ar 7
Port_7441569_1 | SOURCEANDSINK | Dreno Ar 7
Port_7441484_1 | SOURCEANDSINK | Dreno Ar 7
Port_7441486_1 | SOURCEANDSINK | Dreno Ar 7
Port_7441510_1 | SOURCEANDSINK
Port_7441510_2 | SOURCEANDSINK
Port_7441511_0 | SOURCEANDSINK | Dreno Ar 8
Port_7441521_2 | SOURCEANDSINK | Dreno Ar 8
Port_7441511_1 | SOURCEANDSINK | Dreno Ar 8
Port_7441513_1 | SOURCEANDSINK | Dreno Ar 8
Port_7441517_0 | SOURCEANDSINK | Dreno Ar 8
Port_7441513_2 | SOURCEANDSINK | Dreno Ar 8
Port_7441515_0 | SOURCEANDSINK | Dreno Ar 8
Port_7441519_2 | SOURCEANDSINK | Dreno Ar 8
Port_7441515_1 | SOURCEANDSINK | Dreno Ar 8
Port_7441521_1 | SOURCEANDSINK | Dreno Ar 8
Port_7441517_1 | SOURCEANDSINK | Dreno Ar 8
Port_7441519_1 | SOURCEANDSINK | Dreno Ar 8
Port_7441659_0 | SOURCEANDSINK | Dreno Ar 5
Port_7441667_1 | SOURCEANDSINK | Dreno Ar 5
Port_7441659_1 | SOURCEANDSINK | Dreno Ar 5
Port_7441712_1 | SOURCEANDSINK
Port_7441712_2 | SOURCEANDSINK
Port_7441713_0 | SOURCEANDSINK | Dreno Ar 9
Port_7441723_2 | SOURCEANDSINK | Dreno Ar 9
Port_7441713_1 | SOURCEANDSINK | Dreno Ar 9
Port_7441727_1 | SOURCEANDSINK | Dreno Ar 9
Port_7441715_1 | SOURCEANDSINK | Dreno Ar 9
Port_7441719_0 | SOURCEANDSINK | Dreno Ar 9
Port_7441715_2 | SOURCEANDSINK | Dreno Ar 9
Port_7441717_0 | SOURCEANDSINK | Dreno Ar 9
Port_7441721_2 | SOURCEANDSINK | Dreno Ar 9
Port_7441717_1 | SOURCEANDSINK | Dreno Ar 9
Port_7441723_1 | SOURCEANDSINK | Dreno Ar 9
Port_7441719_1 | SOURCEANDSINK | Dreno Ar 9
Port_7441721_1 | SOURCEANDSINK | Dreno Ar 9
Port_7441725_0 | SOURCEANDSINK | Dreno Ar 9
Port_7441727_2 | SOURCEANDSINK | Dreno Ar 9
Port_7441725_1 | SOURCEANDSINK | Dreno Ar 9
Port_7441975_1 | SOURCEANDSINK
Port_7441975_2 | SOURCEANDSINK
Port_7442001_0 | SOURCEANDSINK | Dreno Ar 11
Port_7442123_2 | SOURCEANDSINK | Dreno Ar 11
Port_7442001_1 | SOURCEANDSINK | Dreno Ar 11
Port_7442003_1 | SOURCEANDSINK | Dreno Ar 11
Port_7442007_0 | SOURCEANDSINK | Dreno Ar 11
Port_7442003_2 | SOURCEANDSINK | Dreno Ar 11
Port_7442005_0 | SOURCEANDSINK | Dreno Ar 11
Port_7442009_2 | SOURCEANDSINK | Dreno Ar 11
Port_7442005_1 | SOURCEANDSINK | Dreno Ar 11
Port_7442123_1 | SOURCEANDSINK | Dreno Ar 11
Port_7442007_1 | SOURCEANDSINK | Dreno Ar 11
Port_7442009_1 | SOURCEANDSINK | Dreno Ar 11
Port_7442147_1 | SOURCEANDSINK
Port_7442147_2 | SOURCEANDSINK
Port_7442148_0 | SOURCEANDSINK | Dreno Ar 10
Port_7442158_2 | SOURCEANDSINK | Dreno Ar 10
Port_7442148_1 | SOURCEANDSINK | Dreno Ar 10
Port_7442150_1 | SOURCEANDSINK | Dreno Ar 10
Port_7442154_0 | SOURCEANDSINK | Dreno Ar 10
Port_7442150_2 | SOURCEANDSINK | Dreno Ar 10
Port_7442152_0 | SOURCEANDSINK | Dreno Ar 10
Port_7442156_2 | SOURCEANDSINK | Dreno Ar 10
Port_7442152_1 | SOURCEANDSINK | Dreno Ar 10
Port_7442158_1 | SOURCEANDSINK | Dreno Ar 10
Port_7442154_1 | SOURCEANDSINK | Dreno Ar 10
Port_7442156_1 | SOURCEANDSINK | Dreno Ar 10
Port_7442586_1 | SOURCEANDSINK
Port_7442586_2 | SOURCEANDSINK
Port_7442587_0 | SOURCEANDSINK | Dreno Ar 14
Port_7442597_2 | SOURCEANDSINK | Dreno Ar 14
Port_7442587_1 | SOURCEANDSINK | Dreno Ar 14
Port_7442589_1 | SOURCEANDSINK | Dreno Ar 14
Port_7442593_0 | SOURCEANDSINK | Dreno Ar 14
Port_7442589_2 | SOURCEANDSINK | Dreno Ar 14
Port_7442591_0 | SOURCEANDSINK | Dreno Ar 14
Port_7442595_2 | SOURCEANDSINK | Dreno Ar 14
Port_7442591_1 | SOURCEANDSINK | Dreno Ar 14
Port_7442597_1 | SOURCEANDSINK | Dreno Ar 14
Port_7442593_1 | SOURCEANDSINK | Dreno Ar 14
Port_7442595_1 | SOURCEANDSINK | Dreno Ar 14
Port_7442636_1 | SOURCEANDSINK
Port_7442636_2 | SOURCEANDSINK
Port_7442637_0 | SOURCEANDSINK | Dreno Ar 13
Port_7442647_2 | SOURCEANDSINK | Dreno Ar 13
Port_7442637_1 | SOURCEANDSINK | Dreno Ar 13
Port_7442639_1 | SOURCEANDSINK | Dreno Ar 13
Port_7442643_0 | SOURCEANDSINK | Dreno Ar 13
Port_7442639_2 | SOURCEANDSINK | Dreno Ar 13
Port_7442641_0 | SOURCEANDSINK | Dreno Ar 13
Port_7442645_2 | SOURCEANDSINK | Dreno Ar 13
Port_7442641_1 | SOURCEANDSINK | Dreno Ar 13
Port_7442647_1 | SOURCEANDSINK | Dreno Ar 13
Port_7442643_1 | SOURCEANDSINK | Dreno Ar 13
Port_7442645_1 | SOURCEANDSINK | Dreno Ar 13
Port_7442705_1 | SOURCEANDSINK
Port_7442705_2 | SOURCEANDSINK
Port_7442975_0 | SOURCEANDSINK | Dreno Ar 17
Port_7443071_2 | SOURCEANDSINK | Dreno Ar 17
Port_7442975_1 | SOURCEANDSINK | Dreno Ar 17
Port_7443087_1 | SOURCEANDSINK | Dreno Ar 17
Port_7442977_1 | SOURCEANDSINK | Dreno Ar 17
Port_7442981_0 | SOURCEANDSINK | Dreno Ar 17
Port_7442977_2 | SOURCEANDSINK | Dreno Ar 17
Port_7442979_0 | SOURCEANDSINK | Dreno Ar 17
Port_7442983_2 | SOURCEANDSINK | Dreno Ar 17
Port_7442979_1 | SOURCEANDSINK | Dreno Ar 17
Port_7443071_1 | SOURCEANDSINK | Dreno Ar 17
Port_7442981_1 | SOURCEANDSINK | Dreno Ar 17
Port_7442983_1 | SOURCEANDSINK | Dreno Ar 17
Port_7443077_0 | SOURCEANDSINK | Dreno Ar 17
Port_7443087_2 | SOURCEANDSINK | Dreno Ar 17
Port_7443077_1 | SOURCEANDSINK | Dreno Ar 17
Port_7443112_1 | SOURCEANDSINK
Port_7443112_2 | SOURCEANDSINK
Port_7443113_0 | SOURCEANDSINK | Dreno Ar 15
Port_7443163_2 | SOURCEANDSINK | Dreno Ar 15
Port_7443113_1 | SOURCEANDSINK | Dreno Ar 15
Port_7443176_2 | SOURCEANDSINK | Dreno Ar 15
Port_7443115_1 | SOURCEANDSINK | Dreno Ar 15
Port_7443119_0 | SOURCEANDSINK | Dreno Ar 15
Port_7443115_2 | SOURCEANDSINK | Dreno Ar 15
Port_7443117_0 | SOURCEANDSINK | Dreno Ar 15
Port_7443121_2 | SOURCEANDSINK | Dreno Ar 15
Port_7443117_1 | SOURCEANDSINK | Dreno Ar 15
Port_7443163_1 | SOURCEANDSINK | Dreno Ar 15
Port_7443119_1 | SOURCEANDSINK | Dreno Ar 15
Port_7443121_1 | SOURCEANDSINK | Dreno Ar 15
Port_7443168_0 | SOURCEANDSINK | Dreno Ar 15
Port_7443176_1 | SOURCEANDSINK | Dreno Ar 15
Port_7443168_1 | SOURCEANDSINK | Dreno Ar 15
Port_7443210_1 | SOURCEANDSINK
Port_7443210_2 | SOURCEANDSINK
Port_7443211_0 | SOURCEANDSINK | Dreno Ar 12
Port_7443251_2 | SOURCEANDSINK | Dreno Ar 12
Port_7443211_1 | SOURCEANDSINK | Dreno Ar 12
Port_7443264_2 | SOURCEANDSINK | Dreno Ar 12
Port_7443213_1 | SOURCEANDSINK | Dreno Ar 12
Port_7443217_0 | SOURCEANDSINK | Dreno Ar 12
Port_7443213_2 | SOURCEANDSINK | Dreno Ar 12
Port_7443215_0 | SOURCEANDSINK | Dreno Ar 12
Port_7443219_2 | SOURCEANDSINK | Dreno Ar 12
Port_7443215_1 | SOURCEANDSINK | Dreno Ar 12
Port_7443251_1 | SOURCEANDSINK | Dreno Ar 12
Port_7443217_1 | SOURCEANDSINK | Dreno Ar 12
Port_7443219_1 | SOURCEANDSINK | Dreno Ar 12
Port_7443256_0 | SOURCEANDSINK | Dreno Ar 12
Port_7443264_1 | SOURCEANDSINK | Dreno Ar 12
Port_7443256_1 | SOURCEANDSINK | Dreno Ar 12
Port_7443292_1 | SOURCEANDSINK
Port_7443292_2 | SOURCEANDSINK
Port_7443293_0 | SOURCEANDSINK | Dreno Ar 16
Port_7443335_2 | SOURCEANDSINK | Dreno Ar 16
Port_7443293_1 | SOURCEANDSINK | Dreno Ar 16
Port_7443356_2 | SOURCEANDSINK | Dreno Ar 16
Port_7443295_1 | SOURCEANDSINK | Dreno Ar 16
Port_7443299_0 | SOURCEANDSINK | Dreno Ar 16
Port_7443295_2 | SOURCEANDSINK | Dreno Ar 16
Port_7443297_0 | SOURCEANDSINK | Dreno Ar 16
Port_7443301_2 | SOURCEANDSINK | Dreno Ar 16
Port_7443297_1 | SOURCEANDSINK | Dreno Ar 16
Port_7443335_1 | SOURCEANDSINK | Dreno Ar 16
Port_7443299_1 | SOURCEANDSINK | Dreno Ar 16
Port_7443301_1 | SOURCEANDSINK | Dreno Ar 16
Port_7443348_0 | SOURCEANDSINK | Dreno Ar 16
Port_7443356_1 | SOURCEANDSINK | Dreno Ar 16
Port_7443348_1 | SOURCEANDSINK | Dreno Ar 16
Port_7443365_1 | SOURCEANDSINK
Port_7443365_2 | SOURCEANDSINK
Port_7443366_0 | SOURCEANDSINK | Dreno Ar 18
Port_7443376_2 | SOURCEANDSINK | Dreno Ar 18
Port_7443366_1 | SOURCEANDSINK | Dreno Ar 18
Port_7443416_1 | SOURCEANDSINK | Dreno Ar 18
Port_7443368_1 | SOURCEANDSINK | Dreno Ar 18
Port_7443372_0 | SOURCEANDSINK | Dreno Ar 18
Port_7443368_2 | SOURCEANDSINK | Dreno Ar 18
Port_7443370_0 | SOURCEANDSINK | Dreno Ar 18
Port_7443374_2 | SOURCEANDSINK | Dreno Ar 18
Port_7443370_1 | SOURCEANDSINK | Dreno Ar 18
Port_7443376_1 | SOURCEANDSINK | Dreno Ar 18
Port_7443372_1 | SOURCEANDSINK | Dreno Ar 18
Port_7443374_1 | SOURCEANDSINK | Dreno Ar 18
Port_7443408_0 | SOURCEANDSINK | Dreno Ar 18
Port_7443416_2 | SOURCEANDSINK | Dreno Ar 18
Port_7443408_1 | SOURCEANDSINK | Dreno Ar 18
Port_7443437_1 | SOURCEANDSINK
Port_7443437_2 | SOURCEANDSINK
Port_7443438_0 | SOURCEANDSINK | Dreno Ar 19
Port_7443448_2 | SOURCEANDSINK | Dreno Ar 19
Port_7443438_1 | SOURCEANDSINK | Dreno Ar 19
Port_7443452_1 | SOURCEANDSINK | Dreno Ar 19
Port_7443440_1 | SOURCEANDSINK | Dreno Ar 19
Port_7443444_0 | SOURCEANDSINK | Dreno Ar 19
Port_7443440_2 | SOURCEANDSINK | Dreno Ar 19
Port_7443442_0 | SOURCEANDSINK | Dreno Ar 19
Port_7443446_2 | SOURCEANDSINK | Dreno Ar 19
Port_7443442_1 | SOURCEANDSINK | Dreno Ar 19
Port_7443448_1 | SOURCEANDSINK | Dreno Ar 19
Port_7443444_1 | SOURCEANDSINK | Dreno Ar 19
Port_7443446_1 | SOURCEANDSINK | Dreno Ar 19
Port_7443450_0 | SOURCEANDSINK | Dreno Ar 19
Port_7443452_2 | SOURCEANDSINK | Dreno Ar 19
Port_7443450_1 | SOURCEANDSINK | Dreno Ar 19
Port_7443454_1 | SOURCEANDSINK
Port_7443454_2 | SOURCEANDSINK
Port_7443455_0 | SOURCEANDSINK | Dreno Ar 21
Port_7443465_2 | SOURCEANDSINK | Dreno Ar 21
Port_7443455_1 | SOURCEANDSINK | Dreno Ar 21
Port_7443495_1 | SOURCEANDSINK | Dreno Ar 21
Port_7443457_1 | SOURCEANDSINK | Dreno Ar 21
Port_7443461_0 | SOURCEANDSINK | Dreno Ar 21
Port_7443457_2 | SOURCEANDSINK | Dreno Ar 21
Port_7443459_0 | SOURCEANDSINK | Dreno Ar 21
Port_7443463_2 | SOURCEANDSINK | Dreno Ar 21
Port_7443459_1 | SOURCEANDSINK | Dreno Ar 21
Port_7443465_1 | SOURCEANDSINK | Dreno Ar 21
Port_7443461_1 | SOURCEANDSINK | Dreno Ar 21
Port_7443463_1 | SOURCEANDSINK | Dreno Ar 21
Port_7443487_0 | SOURCEANDSINK | Dreno Ar 21
Port_7443495_2 | SOURCEANDSINK | Dreno Ar 21
Port_7443487_1 | SOURCEANDSINK | Dreno Ar 21
Port_7443563_1 | SOURCEANDSINK
Port_7443563_2 | SOURCEANDSINK
Port_7443564_0 | SOURCEANDSINK | Dreno Ar 20
Port_7443574_2 | SOURCEANDSINK | Dreno Ar 20
Port_7443564_1 | SOURCEANDSINK | Dreno Ar 20
Port_7443566_1 | SOURCEANDSINK | Dreno Ar 20
Port_7443570_0 | SOURCEANDSINK | Dreno Ar 20
Port_7443566_2 | SOURCEANDSINK | Dreno Ar 20
Port_7443568_0 | SOURCEANDSINK | Dreno Ar 20
Port_7443572_2 | SOURCEANDSINK | Dreno Ar 20
Port_7443568_1 | SOURCEANDSINK | Dreno Ar 20
Port_7443574_1 | SOURCEANDSINK | Dreno Ar 20
Port_7443570_1 | SOURCEANDSINK | Dreno Ar 20
Port_7443572_1 | SOURCEANDSINK | Dreno Ar 20
Port_7443798_1 | SOURCEANDSINK
Port_7443798_2 | SOURCEANDSINK
Port_7443799_1 | SOURCEANDSINK | Dreno Ar 23
Port_7443799_2 | SOURCEANDSINK | Dreno Ar 23
Port_7443802_0 | SOURCEANDSINK | Dreno Ar 24
Port_7443812_2 | SOURCEANDSINK | Dreno Ar 24
Port_7443802_1 | SOURCEANDSINK | Dreno Ar 24
Port_7443804_1 | SOURCEANDSINK | Dreno Ar 24
Port_7443808_0 | SOURCEANDSINK | Dreno Ar 24
Port_7443804_2 | SOURCEANDSINK | Dreno Ar 24
Port_7443806_0 | SOURCEANDSINK | Dreno Ar 24
Port_7443810_2 | SOURCEANDSINK | Dreno Ar 24
Port_7443806_1 | SOURCEANDSINK | Dreno Ar 24
Port_7443812_1 | SOURCEANDSINK | Dreno Ar 24
Port_7443808_1 | SOURCEANDSINK | Dreno Ar 24
Port_7443810_1 | SOURCEANDSINK | Dreno Ar 24
Port_7443830_1 | SOURCEANDSINK
Port_7443830_2 | SOURCEANDSINK
Port_7443834_0 | SOURCEANDSINK | Dreno Ar 26
Port_7443844_2 | SOURCEANDSINK | Dreno Ar 26
Port_7443834_1 | SOURCEANDSINK | Dreno Ar 26
Port_7443838_0 | SOURCEANDSINK | Dreno Ar 26
Port_7443842_2 | SOURCEANDSINK | Dreno Ar 26
Port_7443838_1 | SOURCEANDSINK | Dreno Ar 26
Port_7443844_1 | SOURCEANDSINK | Dreno Ar 26
Port_7443840_0 | SOURCEANDSINK | Dreno Ar 26
Port_7443840_1 | SOURCEANDSINK | Dreno Ar 26
Port_7443842_1 | SOURCEANDSINK | Dreno Ar 26
Port_7443895_1 | SOURCEANDSINK
Port_7443895_2 | SOURCEANDSINK
Port_7443896_0 | SOURCEANDSINK | Dreno Ar 27
Port_7443943_2 | SOURCEANDSINK | Dreno Ar 27
Port_7443896_1 | SOURCEANDSINK | Dreno Ar 27
Port_7443957_2 | SOURCEANDSINK | Dreno Ar 27
Port_7443898_1 | SOURCEANDSINK | Dreno Ar 27
Port_7443902_0 | SOURCEANDSINK | Dreno Ar 27
Port_7443898_2 | SOURCEANDSINK | Dreno Ar 27
Port_7443900_0 | SOURCEANDSINK | Dreno Ar 27
Port_7443904_2 | SOURCEANDSINK | Dreno Ar 27
Port_7443900_1 | SOURCEANDSINK | Dreno Ar 27
Port_7443943_1 | SOURCEANDSINK | Dreno Ar 27
Port_7443902_1 | SOURCEANDSINK | Dreno Ar 27
Port_7443904_1 | SOURCEANDSINK | Dreno Ar 27
Port_7443949_0 | SOURCEANDSINK | Dreno Ar 27
Port_7443957_1 | SOURCEANDSINK | Dreno Ar 27
Port_7443949_1 | SOURCEANDSINK | Dreno Ar 27
InPort_7446299_1 | SINK | Água Fria - Extravasor e Limpeza 1
OutPort_7446510_1 | SOURCE | Água Fria - Extravasor e Limpeza 1
Port_7446299_2 | SOURCEANDSINK
InPort_7446353_1 | SINK | Água Fria - Extravasor e Limpeza 1
OutPort_7446468_1 | SOURCE | Água Fria - Extravasor e Limpeza 1
Port_7446353_2 | SOURCEANDSINK
InPort_7446363_1 | SINK | Água Fria - Extravasor e Limpeza 1
OutPort_7446434_1 | SOURCE | Água Fria - Extravasor e Limpeza 1
Port_7446363_2 | SOURCEANDSINK
InPort_7447290_1 | SINK | Água Fria - Extravasor e Limpeza 1
OutPort_7446417_0 | SOURCE | Água Fria - Extravasor e Limpeza 1
InPort_7446417_1 | SINK | Água Fria - Extravasor e Limpeza 1
OutPort_7446726_1 | SOURCE | Água Fria - Extravasor e Limpeza 1
InPort_7446434_2 | SINK | Água Fria - Extravasor e Limpeza 1
OutPort_7446582_0 | SOURCE | Água Fria - Extravasor e Limpeza 1
InPort_7446468_2 | SINK | Água Fria - Extravasor e Limpeza 1
OutPort_7446454_0 | SOURCE | Água Fria - Extravasor e Limpeza 1
InPort_7446454_1 | SINK | Água Fria - Extravasor e Limpeza 1
OutPort_7446538_3 | SOURCE | Água Fria - Extravasor e Limpeza 1
InPort_7446472_0 | SINK | Água Fria - Extravasor e Limpeza 1
OutPort_7446581_3 | SOURCE | Água Fria - Extravasor e Limpeza 1
InPort_7446538_1 | SINK | Água Fria - Extravasor e Limpeza 1
OutPort_7446472_1 | SOURCE | Água Fria - Extravasor e Limpeza 1
InPort_7446510_2 | SINK | Água Fria - Extravasor e Limpeza 1
OutPort_7446496_0 | SOURCE | Água Fria - Extravasor e Limpeza 1
InPort_7446496_1 | SINK | Água Fria - Extravasor e Limpeza 1
OutPort_7446619_1 | SOURCE | Água Fria - Extravasor e Limpeza 1
InPort_7446514_0 | SINK | Água Fria - Extravasor e Limpeza 1
OutPort_7446538_2 | SOURCE | Água Fria - Extravasor e Limpeza 1
InPort_7446619_2 | SINK | Água Fria - Extravasor e Limpeza 1
OutPort_7446514_1 | SOURCE | Água Fria - Extravasor e Limpeza 1
InPort_7446581_1 | SINK | Água Fria - Extravasor e Limpeza 1
OutPort_7447296_0 | SOURCE | Água Fria - Extravasor e Limpeza 1
InPort_7446582_1 | SINK | Água Fria - Extravasor e Limpeza 1
OutPort_7446581_2 | SOURCE | Água Fria - Extravasor e Limpeza 1
InPort_7446726_2 | SINK | Água Fria - Extravasor e Limpeza 1
OutPort_7487189_0 | SOURCE | Água Fria - Extravasor e Limpeza 1
InPort_7447296_1 | SINK | Água Fria - Extravasor e Limpeza 1
OutPort_7447290_2 | SOURCE | Água Fria - Extravasor e Limpeza 1
InPort_7449294_0 | SINK | Água Fria - Extravasor e Limpeza 1
OutPort_7509313_1 | SOURCE | Água Fria - Extravasor e Limpeza 1
InPort_7485759_2 | SINK | Água Fria - Extravasor e Limpeza 1
OutPort_7449294_1 | SOURCE | Água Fria - Extravasor e Limpeza 1
InPort_7449590_0 | SINK | Água Fria - Extravasor e Limpeza 1
OutPort_7449609_1 | SOURCE | Água Fria - Extravasor e Limpeza 1
InPort_7509247_1 | SINK | Água Fria - Extravasor e Limpeza 1
OutPort_7449590_1 | SOURCE | Água Fria - Extravasor e Limpeza 1
InPort_7449609_2 | SINK | Água Fria - Extravasor e Limpeza 1
OutPort_7452826_0 | SOURCE | Água Fria - Extravasor e Limpeza 1
InPort_7449835_0 | SINK | Água Fria Alimentação 5
OutPort_7449845_2 | SOURCE | Água Fria Alimentação 5
InPort_7449884_1 | SINK | Água Fria Alimentação 5
OutPort_7449835_1 | SOURCE | Água Fria Alimentação 5
InPort_7449849_0 | SINK | Água Fria Alimentação 5
OutPort_7449884_2 | SOURCE | Água Fria Alimentação 5
InPort_7449886_2 | SINK | Água Fria Alimentação 5
OutPort_7449849_1 | SOURCE | Água Fria Alimentação 5
InPort_7450992_1 | SINK | Água Fria - Extravasor e Limpeza 12
OutPort_7450968_1 | SOURCE | Água Fria - Extravasor e Limpeza 12
InPort_7451274_1 | SINK | Água Fria - Extravasor e Limpeza 12
OutPort_7450976_0 | SOURCE | Água Fria - Extravasor e Limpeza 12
InPort_7450976_1 | SINK | Água Fria - Extravasor e Limpeza 12
OutPort_7450992_2 | SOURCE | Água Fria - Extravasor e Limpeza 12
InPort_7451251_1 | SINK | Água Fria Alimentação 5
OutPort_7451274_2 | SOURCE | Água Fria Alimentação 5
Port_7452802_0 | SOURCEANDSINK | Água Fria - Extravasor e Limpeza 1
Port_7452818_3 | SOURCEANDSINK | Água Fria - Extravasor e Limpeza 1
Port_7452802_1 | SOURCEANDSINK | Água Fria - Extravasor e Limpeza 1
Port_7475392_1 | SOURCEANDSINK | Água Fria - Extravasor e Limpeza 1
InPort_7452819_1 | SINK | Água Fria - Extravasor e Limpeza 1
OutPort_7452818_2 | SOURCE | Água Fria - Extravasor e Limpeza 1
InPort_7452826_1 | SINK | Água Fria - Extravasor e Limpeza 1
OutPort_7509194_2 | SOURCE | Água Fria - Extravasor e Limpeza 1
InPort_7454165_1 | SINK
OutPort_7456933_3 | SOURCE | Esgoto Sanitário 80
InPort_7456933_4 | SINK
InPort_7456933_5 | SINK
InPort_7456933_6 | SINK
InPort_7456933_7 | SINK
InPort_7456933_8 | SINK
InPort_7456933_9 | SINK
InPort_7456933_10 | SINK
InPort_7456933_11 | SINK
InPort_7456933_12 | SINK
InPort_7474995_0 | SINK | Água Fria - Extravasor e Limpeza 3
OutPort_7474886_1 | SOURCE | Água Fria - Extravasor e Limpeza 3
InPort_7475044_1 | SINK | Água Fria - Extravasor e Limpeza 3
OutPort_7474995_1 | SOURCE | Água Fria - Extravasor e Limpeza 3
InPort_7475010_0 | SINK | Água Fria - Extravasor e Limpeza 3
OutPort_7475044_3 | SOURCE | Água Fria - Extravasor e Limpeza 3
InPort_7475026_1 | SINK | Água Fria - Extravasor e Limpeza 3
OutPort_7475010_1 | SOURCE | Água Fria - Extravasor e Limpeza 3
InPort_7475020_0 | SINK | Água Fria - Extravasor e Limpeza 3
OutPort_7475026_2 | SOURCE | Água Fria - Extravasor e Limpeza 3
InPort_7475176_1 | SINK | Água Fria - Extravasor e Limpeza 3
OutPort_7475020_1 | SOURCE | Água Fria - Extravasor e Limpeza 3
InPort_7475076_1 | SINK | Água Fria - Extravasor e Limpeza 3
OutPort_7475044_2 | SOURCE | Água Fria - Extravasor e Limpeza 3
InPort_7475176_2 | SINK | Água Fria - Extravasor e Limpeza 3
OutPort_7475143_1 | SOURCE | Água Fria - Extravasor e Limpeza 3
Port_7475392_2 | SOURCEANDSINK | Água Fria - Extravasor e Limpeza 1
InPort_7475438_0 | SINK | Água Fria - Extravasor e Limpeza 1
OutPort_7509313_3 | SOURCE | Água Fria - Extravasor e Limpeza 1
InPort_7485896_2 | SINK | Água Fria - Extravasor e Limpeza 1
OutPort_7475438_1 | SOURCE | Água Fria - Extravasor e Limpeza 1
Port_7475452_1 | SOURCEANDSINK | Água Fria 2
Port_7475452_2 | SOURCEANDSINK | Água Fria 2
Port_7475683_1 | SOURCEANDSINK | Água Fria 2
InPort_7485892_2 | SINK | Água Fria - Extravasor e Limpeza 1
OutPort_7475475_0 | SOURCE | Água Fria - Extravasor e Limpeza 1
InPort_7475475_1 | SINK | Água Fria - Extravasor e Limpeza 1
OutPort_7485896_1 | SOURCE | Água Fria - Extravasor e Limpeza 1
Port_7475683_2 | SOURCEANDSINK | Água Fria 2
InPort_7486918_2 | SINK | Água Fria 1
OutPort_7477108_0 | SOURCE | Água Fria 1
InPort_7477108_1 | SINK | Água Fria 1
OutPort_7486914_3 | SOURCE | Água Fria 1
InPort_7507493_1 | SINK | Esgoto Sanitário 69
OutPort_7479980_1 | SOURCE | Esgoto Sanitário 69
InPort_7507617_0 | SINK | Esgoto Sanitário 81
OutPort_7480029_3 | SOURCE | Esgoto Sanitário 81
InPort_7480029_4 | SINK
InPort_7480029_5 | SINK
InPort_7480029_6 | SINK
InPort_7480029_7 | SINK
InPort_7480029_8 | SINK
InPort_7480029_9 | SINK
InPort_7480029_10 | SINK
InPort_7480029_11 | SINK
InPort_7480029_12 | SINK
InPort_7480328_3 | SINK
InPort_7480440_0 | SINK | Esgoto Sanitário 85
OutPort_7480328_4 | SOURCE | Esgoto Sanitário 85
Port_7484271_1 | SOURCEANDSINK
Port_7484271_2 | SOURCEANDSINK
Port_7484528_1 | SOURCEANDSINK
Port_7484528_2 | SOURCEANDSINK
Port_7484816_1 | SOURCEANDSINK
Port_7484816_2 | SOURCEANDSINK
Port_7485295_1 | SOURCEANDSINK
Port_7485295_2 | SOURCEANDSINK
InPort_7485723_1 | SINK | Água Fria - Extravasor e Limpeza 1
OutPort_7485717_0 | SOURCE | Água Fria - Extravasor e Limpeza 1
InPort_7485717_1 | SINK | Água Fria - Extravasor e Limpeza 1
OutPort_7485892_1 | SOURCE | Água Fria - Extravasor e Limpeza 1
InPort_7485719_1 | SINK | Água Fria - Extravasor e Limpeza 1
OutPort_7485728_0 | SOURCE | Água Fria - Extravasor e Limpeza 1
InPort_7485732_1 | SINK | Água Fria - Extravasor e Limpeza 1
OutPort_7485719_2 | SOURCE | Água Fria - Extravasor e Limpeza 1
InPort_7485721_1 | SINK | Água Fria 3
OutPort_7485732_2 | SOURCE | Água Fria 3
InPort_7485728_1 | SINK | Água Fria - Extravasor e Limpeza 1
OutPort_7485723_2 | SOURCE | Água Fria - Extravasor e Limpeza 1
InPort_7485752_1 | SINK | Água Fria - Extravasor e Limpeza 1
OutPort_7485746_0 | SOURCE | Água Fria - Extravasor e Limpeza 1
InPort_7485746_1 | SINK | Água Fria - Extravasor e Limpeza 1
OutPort_7485759_1 | SOURCE | Água Fria - Extravasor e Limpeza 1
InPort_7485748_1 | SINK | Água Fria - Extravasor e Limpeza 1
OutPort_7485757_0 | SOURCE | Água Fria - Extravasor e Limpeza 1
InPort_7485761_1 | SINK | Água Fria - Extravasor e Limpeza 1
OutPort_7485748_2 | SOURCE | Água Fria - Extravasor e Limpeza 1
InPort_7485750_1 | SINK | Água Fria 4
OutPort_7485761_2 | SOURCE | Água Fria 4
InPort_7485757_1 | SINK | Água Fria - Extravasor e Limpeza 1
OutPort_7485752_2 | SOURCE | Água Fria - Extravasor e Limpeza 1
InPort_7486484_1 | SINK | Água Fria - Extravasor e Limpeza 1
OutPort_7486587_2 | SOURCE | Água Fria - Extravasor e Limpeza 1
InPort_7486587_1 | SINK | Água Fria - Extravasor e Limpeza 1
OutPort_7488007_1 | SOURCE | Água Fria - Extravasor e Limpeza 1
Port_7486613_0 | SOURCEANDSINK | Água Fria 9
Port_7486627_3 | SOURCEANDSINK | Água Fria 9
Port_7486613_1 | SOURCEANDSINK | Água Fria 9
Port_7486705_1 | SOURCEANDSINK | Água Fria 9
InPort_7486627_1 | SINK | Água Fria 9
OutPort_7486628_1 | SOURCE | Água Fria 9
Port_7486633_1 | SOURCEANDSINK | Água Fria 9
Port_7486725_2 | SOURCEANDSINK | Água Fria 9
Port_7486705_2 | SOURCEANDSINK | Água Fria 9
Port_7486725_1 | SOURCEANDSINK | Água Fria 9
InPort_7486863_0 | SINK | Água Fria 1
OutPort_7486852_2 | SOURCE | Água Fria 1
InPort_7486879_2 | SINK | Água Fria 1
OutPort_7486863_1 | SOURCE | Água Fria 1
InPort_7486915_0 | SINK | Água Fria 1
OutPort_7486879_1 | SOURCE | Água Fria 1
InPort_7486914_2 | SINK | Água Fria 1
OutPort_7486915_1 | SOURCE | Água Fria 1
InPort_7487016_1 | SINK | Água Fria - Extravasor e Limpeza 1
OutPort_7493225_1 | SOURCE | Água Fria - Extravasor e Limpeza 1
InPort_7487382_0 | SINK | Água Fria - Extravasor e Limpeza 1
OutPort_7487016_2 | SOURCE | Água Fria - Extravasor e Limpeza 1
InPort_7487067_0 | SINK | Água Fria - Extravasor e Limpeza 1
OutPort_7487073_1 | SOURCE | Água Fria - Extravasor e Limpeza 1
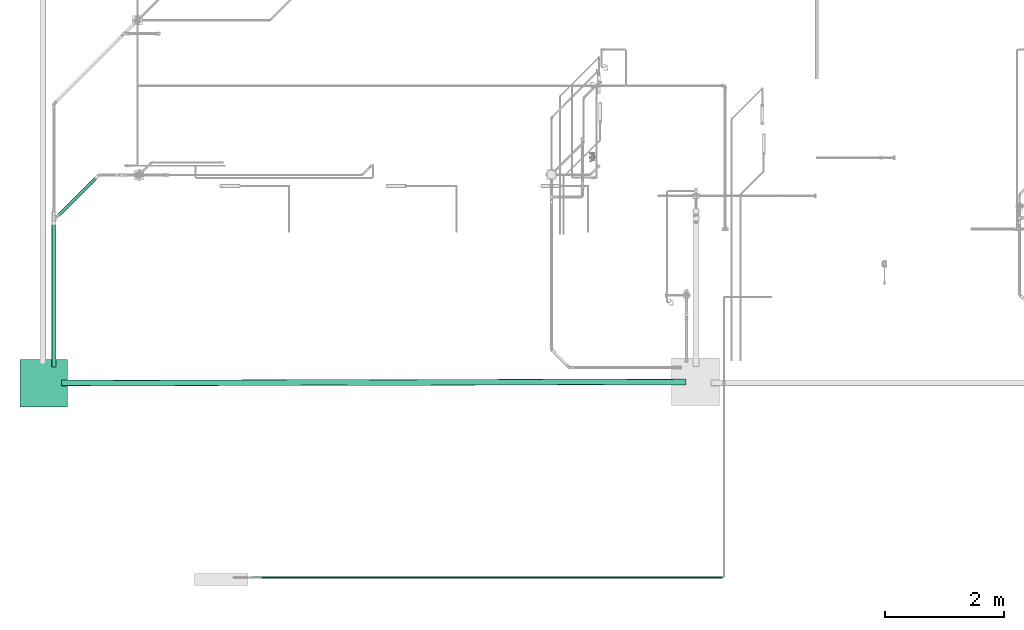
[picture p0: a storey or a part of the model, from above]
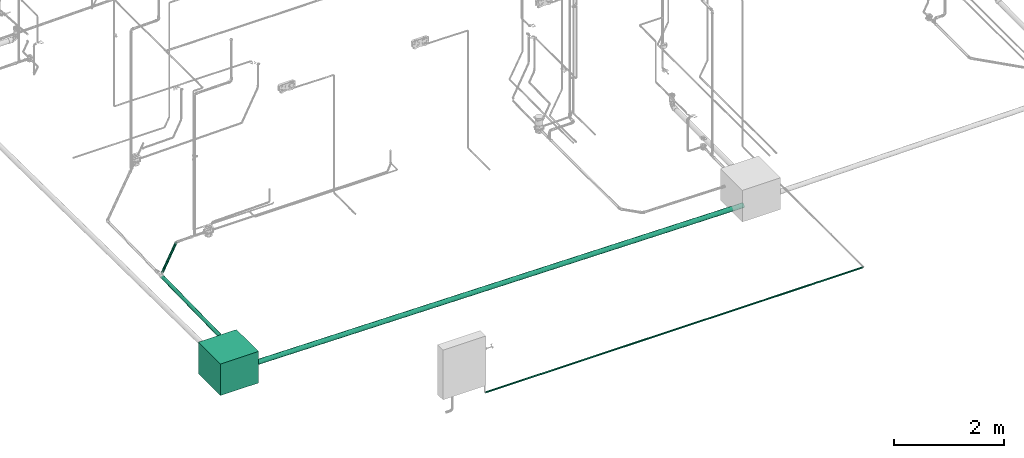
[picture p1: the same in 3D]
Properties of the parts of a building model (IFC2X3), part 3 of 4

# IfcDistributionPort (2899)
Name | FlowDirection | Group
InPort_7487069_2 | SINK | Água Fria - Extravasor e Limpeza 1
OutPort_7487067_1 | SOURCE | Água Fria - Extravasor e Limpeza 1
InPort_7487071_1 | SINK | Água Fria - Extravasor e Limpeza 1
OutPort_7487069_1 | SOURCE | Água Fria - Extravasor e Limpeza 1
Port_7487071_2 | SOURCEANDSINK
InPort_7487072_1 | SINK | Água Fria - Extravasor e Limpeza 1
OutPort_7487073_3 | SOURCE | Água Fria - Extravasor e Limpeza 1
Port_7487072_2 | SOURCEANDSINK
InPort_7487073_2 | SINK | Água Fria - Extravasor e Limpeza 1
OutPort_7487075_1 | SOURCE | Água Fria - Extravasor e Limpeza 1
InPort_7487075_0 | SINK | Água Fria - Extravasor e Limpeza 1
OutPort_7487086_2 | SOURCE | Água Fria - Extravasor e Limpeza 1
InPort_7487079_1 | SINK | Água Fria - Extravasor e Limpeza 1
OutPort_7487077_0 | SOURCE | Água Fria - Extravasor e Limpeza 1
InPort_7487077_1 | SINK | Água Fria - Extravasor e Limpeza 1
OutPort_7487405_3 | SOURCE | Água Fria - Extravasor e Limpeza 1
InPort_7487084_1 | SINK | Água Fria - Extravasor e Limpeza 1
OutPort_7487079_2 | SOURCE | Água Fria - Extravasor e Limpeza 1
InPort_7487086_1 | SINK | Água Fria - Extravasor e Limpeza 1
OutPort_7487084_0 | SOURCE | Água Fria - Extravasor e Limpeza 1
InPort_7487088_1 | SINK | Água Fria - Extravasor e Limpeza 1
OutPort_7487102_1 | SOURCE | Água Fria - Extravasor e Limpeza 1
Port_7487088_2 | SOURCEANDSINK
InPort_7487089_0 | SINK | Água Fria - Extravasor e Limpeza 1
OutPort_7487100_2 | SOURCE | Água Fria - Extravasor e Limpeza 1
InPort_7487102_2 | SINK | Água Fria - Extravasor e Limpeza 1
OutPort_7487089_1 | SOURCE | Água Fria - Extravasor e Limpeza 1
InPort_7487093_1 | SINK | Água Fria - Extravasor e Limpeza 1
OutPort_7487091_0 | SOURCE | Água Fria - Extravasor e Limpeza 1
InPort_7487091_1 | SINK | Água Fria - Extravasor e Limpeza 1
OutPort_7487423_2 | SOURCE | Água Fria - Extravasor e Limpeza 1
InPort_7487098_1 | SINK | Água Fria - Extravasor e Limpeza 1
OutPort_7487093_2 | SOURCE | Água Fria - Extravasor e Limpeza 1
InPort_7487100_1 | SINK | Água Fria - Extravasor e Limpeza 1
OutPort_7487098_0 | SOURCE | Água Fria - Extravasor e Limpeza 1
InPort_7487106_0 | SINK | Água Fria - Extravasor e Limpeza 1
OutPort_7487405_1 | SOURCE | Água Fria - Extravasor e Limpeza 1
InPort_7487423_1 | SINK | Água Fria - Extravasor e Limpeza 1
OutPort_7487106_1 | SOURCE | Água Fria - Extravasor e Limpeza 1
InPort_7487167_0 | SINK | Água Fria - Extravasor e Limpeza 1
OutPort_7487181_3 | SOURCE | Água Fria - Extravasor e Limpeza 1
InPort_7487250_2 | SINK | Água Fria - Extravasor e Limpeza 1
OutPort_7487167_1 | SOURCE | Água Fria - Extravasor e Limpeza 1
InPort_7487182_1 | SINK | Água Fria - Extravasor e Limpeza 1
OutPort_7487181_2 | SOURCE | Água Fria - Extravasor e Limpeza 1
InPort_7487189_1 | SINK | Água Fria - Extravasor e Limpeza 1
OutPort_7487250_1 | SOURCE | Água Fria - Extravasor e Limpeza 1
InPort_7487366_0 | SINK | Água Fria - Extravasor e Limpeza 1
OutPort_7487440_2 | SOURCE | Água Fria - Extravasor e Limpeza 1
InPort_7487405_2 | SINK | Água Fria - Extravasor e Limpeza 1
OutPort_7487366_1 | SOURCE | Água Fria - Extravasor e Limpeza 1
InPort_7487381_1 | SINK | Água Fria - Extravasor e Limpeza 1
OutPort_7487382_1 | SOURCE | Água Fria - Extravasor e Limpeza 1
InPort_7501934_0 | SINK | Água Fria - Extravasor e Limpeza 1
OutPort_7487381_3 | SOURCE | Água Fria - Extravasor e Limpeza 1
InPort_7487432_0 | SINK | Água Fria - Extravasor e Limpeza 1
OutPort_7487440_3 | SOURCE | Água Fria - Extravasor e Limpeza 1
InPort_7487454_1 | SINK | Água Fria - Extravasor e Limpeza 1
OutPort_7487432_1 | SOURCE | Água Fria - Extravasor e Limpeza 1
InPort_7487440_1 | SINK | Água Fria - Extravasor e Limpeza 1
OutPort_7501944_0 | SOURCE | Água Fria - Extravasor e Limpeza 1
InPort_7487477_1 | SINK | Água Fria - Extravasor e Limpeza 1
OutPort_7487446_0 | SOURCE | Água Fria - Extravasor e Limpeza 1
InPort_7487446_1 | SINK | Água Fria - Extravasor e Limpeza 1
OutPort_7487454_2 | SOURCE | Água Fria - Extravasor e Limpeza 1
InPort_7487987_0 | SINK | Água Fria - Extravasor e Limpeza 1
OutPort_7488132_1 | SOURCE | Água Fria - Extravasor e Limpeza 1
InPort_7488005_1 | SINK | Água Fria - Extravasor e Limpeza 1
OutPort_7487987_1 | SOURCE | Água Fria - Extravasor e Limpeza 1
InPort_7487997_0 | SINK | Água Fria - Extravasor e Limpeza 1
OutPort_7488005_2 | SOURCE | Água Fria - Extravasor e Limpeza 1
InPort_7488015_1 | SINK | Água Fria - Extravasor e Limpeza 1
OutPort_7487997_1 | SOURCE | Água Fria - Extravasor e Limpeza 1
InPort_7488007_0 | SINK | Água Fria - Extravasor e Limpeza 1
OutPort_7488015_2 | SOURCE | Água Fria - Extravasor e Limpeza 1
InPort_7488132_2 | SINK | Água Fria - Extravasor e Limpeza 1
OutPort_7488134_1 | SOURCE | Água Fria - Extravasor e Limpeza 1
Port_7488180_0 | SOURCEANDSINK | Esgoto - Ventilação 18
Port_7488184_2 | SOURCEANDSINK | Esgoto - Ventilação 18
Port_7488180_1 | SOURCEANDSINK | Esgoto - Ventilação 18
Port_7488194_2 | SOURCEANDSINK | Esgoto - Ventilação 18
Port_7488182_0 | SOURCEANDSINK | Esgoto - Ventilação 18
Port_7488182_1 | SOURCEANDSINK | Esgoto - Ventilação 18
Port_7488184_1 | SOURCEANDSINK | Esgoto - Ventilação 18
Port_7488192_0 | SOURCEANDSINK | Esgoto - Ventilação 18
Port_7488194_1 | SOURCEANDSINK | Esgoto - Ventilação 18
Port_7488192_1 | SOURCEANDSINK | Esgoto - Ventilação 18
Port_7488204_1 | SOURCEANDSINK | Esgoto - Ventilação 18
Port_7488202_0 | SOURCEANDSINK | Esgoto - Ventilação 18
Port_7488204_2 | SOURCEANDSINK | Esgoto - Ventilação 18
Port_7488202_1 | SOURCEANDSINK | Esgoto - Ventilação 18
Port_7488212_1 | SOURCEANDSINK | Esgoto - Ventilação 18
Port_7489120_1 | SOURCEANDSINK
Port_7489120_2 | SOURCEANDSINK
Port_7489959_1 | SOURCEANDSINK
Port_7489959_2 | SOURCEANDSINK
InPort_7491131_0 | SINK | Esgoto Sanitário 16
OutPort_7491365_1 | SOURCE | Esgoto Sanitário 16
OutPort_7491131_1 | SOURCE | Esgoto Sanitário 16
Port_7491181_5 | SOURCEANDSINK
InPort_7491255_0 | SINK | Esgoto Sanitário 15
OutPort_7491181_6 | SOURCE | Esgoto Sanitário 15
InPort_7491224_1 | SINK | Esgoto Sanitário 15
OutPort_7491267_1 | SOURCE | Esgoto Sanitário 15
InPort_7491239_0 | SINK | Esgoto Sanitário 15
OutPort_7491257_2 | SOURCE | Esgoto Sanitário 15
InPort_7491267_2 | SINK | Esgoto Sanitário 15
OutPort_7491239_1 | SOURCE | Esgoto Sanitário 15
InPort_7491257_1 | SINK | Esgoto Sanitário 15
OutPort_7491255_1 | SOURCE | Esgoto Sanitário 15
InPort_7491342_0 | SINK | Esgoto - Ventilação 20
OutPort_7491365_3 | SOURCE | Esgoto - Ventilação 20
OutPort_7491342_1 | SOURCE | Esgoto - Ventilação 20
InPort_7491365_2 | SINK | Esgoto Sanitário 16
OutPort_7491366_1 | SOURCE | Esgoto Sanitário 16
Port_7491484_5 | SOURCEANDSINK | Esgoto Sanitário 82
Port_7491725_0 | SOURCEANDSINK | Esgoto Sanitário 82
InPort_7491876_0 | SINK | Esgoto Sanitário 29
OutPort_7491484_6 | SOURCE | Esgoto Sanitário 29
InPort_7491571_1 | SINK
InPort_7491571_2 | SINK | Esgoto Sanitário 29
OutPort_7491713_1 | SOURCE | Esgoto Sanitário 29
InPort_7491571_3 | SINK
InPort_7492008_0 | SINK | Esgoto Sanitário 11
OutPort_7491571_4 | SOURCE | Esgoto Sanitário 11
InPort_7491571_5 | SINK
InPort_7491603_0 | SINK | Esgoto Sanitário 11
OutPort_7492007_1 | SOURCE | Esgoto Sanitário 11
InPort_7505371_2 | SINK | Esgoto Sanitário 11
OutPort_7491603_1 | SOURCE | Esgoto Sanitário 11
InPort_7505195_3 | SINK | Esgoto Sanitário 11
OutPort_7491611_0 | SOURCE | Esgoto Sanitário 11
InPort_7491611_1 | SINK | Esgoto Sanitário 11
OutPort_7505371_1 | SOURCE | Esgoto Sanitário 11
InPort_7491713_0 | SINK | Esgoto Sanitário 29
OutPort_7491899_2 | SOURCE | Esgoto Sanitário 29
Port_7491725_1 | SOURCEANDSINK | Esgoto Sanitário 82
InPort_7491899_1 | SINK | Esgoto Sanitário 29
OutPort_7491876_1 | SOURCE | Esgoto Sanitário 29
InPort_7491996_0 | SINK | Esgoto - Ventilação 1
OutPort_7492019_2 | SOURCE | Esgoto - Ventilação 1
InPort_7492039_1 | SINK | Esgoto - Ventilação 1
OutPort_7491996_1 | SOURCE | Esgoto - Ventilação 1
InPort_7492005_0 | SINK | Esgoto - Ventilação 1
OutPort_7492007_3 | SOURCE | Esgoto - Ventilação 1
InPort_7492019_1 | SINK | Esgoto - Ventilação 1
OutPort_7492005_1 | SOURCE | Esgoto - Ventilação 1
InPort_7492007_2 | SINK | Esgoto Sanitário 11
OutPort_7492008_1 | SOURCE | Esgoto Sanitário 11
InPort_7492036_0 | SINK | Esgoto - Ventilação 1
OutPort_7492039_2 | SOURCE | Esgoto - Ventilação 1
InPort_7492382_1 | SINK | Esgoto - Ventilação 1
OutPort_7492036_1 | SOURCE | Esgoto - Ventilação 1
InPort_7492366_0 | SINK | Esgoto - Ventilação 1
OutPort_7492382_2 | SOURCE | Esgoto - Ventilação 1
InPort_7492398_1 | SINK | Esgoto - Ventilação 1
OutPort_7492366_1 | SOURCE | Esgoto - Ventilação 1
InPort_7492392_0 | SINK | Esgoto - Ventilação 1
OutPort_7492398_2 | SOURCE | Esgoto - Ventilação 1
InPort_7492418_1 | SINK | Esgoto - Ventilação 1
OutPort_7492392_1 | SOURCE | Esgoto - Ventilação 1
InPort_7492646_1 | SINK | Água Fria 9
OutPort_7492559_1 | SOURCE | Água Fria 9
Port_7492559_2 | SOURCEANDSINK | Água Fria 9
Port_7492648_1 | SOURCEANDSINK | Água Fria 9
Port_7492571_0 | SOURCEANDSINK | Água Fria 9
Port_7492648_2 | SOURCEANDSINK | Água Fria 9
Port_7492571_1 | SOURCEANDSINK | Água Fria 9
Port_7492595_2 | SOURCEANDSINK | Água Fria 9
InPort_7493210_0 | SINK | Água Fria - Extravasor e Limpeza 1
OutPort_7493223_2 | SOURCE | Água Fria - Extravasor e Limpeza 1
InPort_7493231_1 | SINK | Água Fria - Extravasor e Limpeza 1
OutPort_7493210_1 | SOURCE | Água Fria - Extravasor e Limpeza 1
InPort_7493225_0 | SINK | Água Fria - Extravasor e Limpeza 1
OutPort_7493231_2 | SOURCE | Água Fria - Extravasor e Limpeza 1
Port_7496682_1 | SOURCEANDSINK | Esgoto Sanitário 86
InPort_7496727_1 | SINK | Esgoto Sanitário 87
OutPort_7497224_1 | SOURCE | Esgoto Sanitário 87
InPort_7496800_1 | SINK | Esgoto Sanitário 88
OutPort_7497238_1 | SOURCE | Esgoto Sanitário 88
Port_7496843_1 | SOURCEANDSINK | Esgoto Sanitário 89
Port_7496913_1 | SOURCEANDSINK | Esgoto Sanitário 90
InPort_7496960_1 | SINK | Esgoto Sanitário 91
OutPort_7497251_1 | SOURCE | Esgoto Sanitário 91
InPort_7497005_1 | SINK | Esgoto Sanitário 92
OutPort_7497045_1 | SOURCE | Esgoto Sanitário 93
OutPort_7497146_1 | SOURCE | Esgoto Sanitário 94
Port_7497188_1 | SOURCEANDSINK | Esgoto Sanitário 95
Port_7501636_2 | SOURCEANDSINK | Água Fria 9
Port_7501647_1 | SOURCEANDSINK | Água Fria 9
InPort_7501715_2 | SINK | Água Fria - Extravasor e Limpeza 1
OutPort_7501685_1 | SOURCE | Água Fria - Extravasor e Limpeza 1
InPort_7501697_1 | SINK | Água Fria - Extravasor e Limpeza 1
OutPort_7501715_1 | SOURCE | Água Fria - Extravasor e Limpeza 1
InPort_7501960_2 | SINK | Água Fria - Extravasor e Limpeza 1
OutPort_7501934_1 | SOURCE | Água Fria - Extravasor e Limpeza 1
InPort_7501944_1 | SINK | Água Fria - Extravasor e Limpeza 1
OutPort_7501960_1 | SOURCE | Água Fria - Extravasor e Limpeza 1
InPort_7502677_1 | SINK | Esgoto Sanitário 84
OutPort_7502684_1 | SOURCE | Esgoto Sanitário 84
InPort_7502677_2 | SINK
InPort_7502677_3 | SINK
InPort_7502680_1 | SINK | Esgoto Sanitário 60
OutPort_7502677_4 | SOURCE | Esgoto Sanitário 60
InPort_7502677_5 | SINK
InPort_7502694_2 | SINK | Esgoto Sanitário 60
OutPort_7502680_0 | SOURCE | Esgoto Sanitário 60
Port_7502682_5 | SOURCEANDSINK | Esgoto Sanitário 98
Port_7502686_0 | SOURCEANDSINK | Esgoto Sanitário 98
InPort_7502688_0 | SINK | Esgoto Sanitário 84
OutPort_7502682_6 | SOURCE | Esgoto Sanitário 84
InPort_7502684_0 | SINK | Esgoto Sanitário 84
OutPort_7502690_2 | SOURCE | Esgoto Sanitário 84
Port_7502686_1 | SOURCEANDSINK | Esgoto Sanitário 98
InPort_7502690_1 | SINK | Esgoto Sanitário 84
OutPort_7502688_1 | SOURCE | Esgoto Sanitário 84
InPort_7502692_0 | SINK | Esgoto - Ventilação 9
OutPort_7502694_3 | SOURCE | Esgoto - Ventilação 9
InPort_7502708_1 | SINK | Esgoto - Ventilação 9
OutPort_7502692_1 | SOURCE | Esgoto - Ventilação 9
InPort_7502695_1 | SINK | Esgoto Sanitário 60
OutPort_7502694_1 | SOURCE | Esgoto Sanitário 60
OutPort_7502695_0 | SOURCE | Esgoto Sanitário 60
InPort_7502706_0 | SINK | Esgoto - Ventilação 9
OutPort_7502708_2 | SOURCE | Esgoto - Ventilação 9
InPort_7502718_1 | SINK | Esgoto - Ventilação 9
OutPort_7502706_1 | SOURCE | Esgoto - Ventilação 9
InPort_7502716_0 | SINK | Esgoto - Ventilação 9
OutPort_7502718_2 | SOURCE | Esgoto - Ventilação 9
InPort_7502726_1 | SINK | Esgoto - Ventilação 9
OutPort_7502716_1 | SOURCE | Esgoto - Ventilação 9
InPort_7502795_0 | SINK | Esgoto Sanitário 56
OutPort_7502825_2 | SOURCE | Esgoto Sanitário 56
InPort_7502850_1 | SINK | Esgoto Sanitário 56
OutPort_7502795_1 | SOURCE | Esgoto Sanitário 56
InPort_7502835_0 | SINK | Esgoto Sanitário 56
OutPort_7502850_2 | SOURCE | Esgoto Sanitário 56
OutPort_7502835_1 | SOURCE | Esgoto Sanitário 56
InPort_7503520_0 | SINK | Esgoto Sanitário 17
OutPort_7503883_1 | SOURCE | Esgoto Sanitário 17
OutPort_7503520_1 | SOURCE | Esgoto Sanitário 17
InPort_7503844_1 | SINK | Esgoto Sanitário 17
OutPort_7503828_1 | SOURCE | Esgoto Sanitário 17
InPort_7503838_0 | SINK | Esgoto Sanitário 17
OutPort_7503844_2 | SOURCE | Esgoto Sanitário 17
InPort_7503860_1 | SINK | Esgoto Sanitário 17
OutPort_7503838_1 | SOURCE | Esgoto Sanitário 17
InPort_7504579_0 | SINK | Esgoto Sanitário 17
OutPort_7503860_2 | SOURCE | Esgoto Sanitário 17
InPort_7503883_2 | SINK | Esgoto Sanitário 17
OutPort_7503945_1 | SOURCE | Esgoto Sanitário 17
InPort_7503921_0 | SINK | Esgoto Sanitário 17
OutPort_7504578_1 | SOURCE | Esgoto Sanitário 17
InPort_7503945_2 | SINK | Esgoto Sanitário 17
OutPort_7503921_1 | SOURCE | Esgoto Sanitário 17
InPort_7504140_0 | SINK | Esgoto Sanitário 20
OutPort_7504214_2 | SOURCE | Esgoto Sanitário 20
OutPort_7504511_1 | SOURCE | Esgoto Sanitário 23
InPort_7504557_0 | SINK | Esgoto - Ventilação 6
OutPort_7504591_2 | SOURCE | Esgoto - Ventilação 6
InPort_7504611_1 | SINK | Esgoto - Ventilação 6
OutPort_7504557_1 | SOURCE | Esgoto - Ventilação 6
InPort_7504578_3 | SINK | Esgoto Sanitário 17
OutPort_7504576_0 | SOURCE | Esgoto Sanitário 17
InPort_7504591_1 | SINK | Esgoto - Ventilação 6
OutPort_7504576_1 | SOURCE | Esgoto - Ventilação 6
InPort_7504578_2 | SINK | Esgoto Sanitário 17
OutPort_7504579_1 | SOURCE | Esgoto Sanitário 17
InPort_7504608_0 | SINK | Esgoto - Ventilação 6
OutPort_7504611_2 | SOURCE | Esgoto - Ventilação 6
InPort_7504882_1 | SINK | Esgoto - Ventilação 6
OutPort_7504608_1 | SOURCE | Esgoto - Ventilação 6
InPort_7504865_0 | SINK | Esgoto - Ventilação 6
OutPort_7504882_2 | SOURCE | Esgoto - Ventilação 6
InPort_7504898_1 | SINK | Esgoto - Ventilação 6
OutPort_7504865_1 | SOURCE | Esgoto - Ventilação 6
InPort_7504892_0 | SINK | Esgoto - Ventilação 6
OutPort_7504898_2 | SOURCE | Esgoto - Ventilação 6
InPort_7504916_1 | SINK | Esgoto - Ventilação 6
OutPort_7504892_1 | SOURCE | Esgoto - Ventilação 6
OutPort_7505148_1 | SOURCE | Esgoto Sanitário 25
InPort_7505195_2 | SINK | Esgoto Sanitário 11
OutPort_7505196_1 | SOURCE | Esgoto Sanitário 11
InPort_7505477_0 | SINK | Esgoto Sanitário 63
OutPort_7505487_2 | SOURCE | Esgoto Sanitário 63
InPort_7505765_3 | SINK | Esgoto Sanitário 63
OutPort_7505477_1 | SOURCE | Esgoto Sanitário 63
InPort_7505580_0 | SINK | Esgoto Sanitário 63
OutPort_7505765_1 | SOURCE | Esgoto Sanitário 63
OutPort_7505580_1 | SOURCE | Esgoto Sanitário 63
InPort_7505834_2 | SINK | Esgoto Sanitário 63
OutPort_7505734_0 | SOURCE | Esgoto Sanitário 63
InPort_7505734_1 | SINK | Esgoto Sanitário 63
OutPort_7505987_2 | SOURCE | Esgoto Sanitário 63
InPort_7505765_2 | SINK | Esgoto Sanitário 63
OutPort_7505834_1 | SOURCE | Esgoto Sanitário 63
InPort_7505987_1 | SINK | Esgoto Sanitário 63
OutPort_7506486_1 | SOURCE | Esgoto Sanitário 63
InPort_7506663_3 | SINK | Esgoto Sanitário 63
OutPort_7506462_0 | SOURCE | Esgoto Sanitário 63
InPort_7506695_1 | SINK | Esgoto - Ventilação 17
OutPort_7506462_1 | SOURCE | Esgoto - Ventilação 17
InPort_7506486_0 | SINK | Esgoto Sanitário 63
OutPort_7506663_1 | SOURCE | Esgoto Sanitário 63
InPort_7506663_2 | SINK | Esgoto Sanitário 63
OutPort_7506664_1 | SOURCE | Esgoto Sanitário 63
InPort_7506676_0 | SINK | Esgoto - Ventilação 17
OutPort_7506695_2 | SOURCE | Esgoto - Ventilação 17
InPort_7506711_1 | SINK | Esgoto - Ventilação 17
OutPort_7506676_1 | SOURCE | Esgoto - Ventilação 17
InPort_7506705_0 | SINK | Esgoto - Ventilação 17
OutPort_7506711_2 | SOURCE | Esgoto - Ventilação 17
InPort_7506739_1 | SINK | Esgoto - Ventilação 17
OutPort_7506705_1 | SOURCE | Esgoto - Ventilação 17
InPort_7506964_1 | SINK | Esgoto Sanitário 19
OutPort_7507032_3 | SOURCE | Esgoto Sanitário 26
InPort_7507032_4 | SINK
InPort_7507032_5 | SINK
InPort_7507032_6 | SINK
InPort_7507032_7 | SINK
InPort_7507032_8 | SINK
InPort_7507032_9 | SINK
InPort_7507032_10 | SINK
InPort_7507032_11 | SINK
InPort_7507032_12 | SINK
OutPort_7507308_1 | SOURCE | Esgoto Sanitário 40
InPort_7508131_0 | SINK | Esgoto Sanitário 22
OutPort_7507330_3 | SOURCE | Esgoto Sanitário 22
InPort_7507330_4 | SINK
InPort_7507330_5 | SINK
InPort_7507330_6 | SINK
InPort_7507330_7 | SINK
InPort_7507330_8 | SINK
InPort_7507330_9 | SINK
InPort_7507330_10 | SINK
InPort_7507330_11 | SINK
InPort_7507330_12 | SINK
InPort_7507472_0 | SINK | Esgoto Sanitário 69
OutPort_7507493_2 | SOURCE | Esgoto Sanitário 69
OutPort_7507472_1 | SOURCE | Esgoto Sanitário 69
OutPort_7507617_1 | SOURCE | Esgoto Sanitário 81
InPort_7508052_1 | SINK | Esgoto Sanitário 21
OutPort_7508131_1 | SOURCE | Esgoto Sanitário 22
InPort_7509233_0 | SINK | Água Fria - Extravasor e Limpeza 1
OutPort_7509247_2 | SOURCE | Água Fria - Extravasor e Limpeza 1
InPort_7509259_1 | SINK | Água Fria - Extravasor e Limpeza 1
OutPort_7509233_1 | SOURCE | Água Fria - Extravasor e Limpeza 1
InPort_7509251_0 | SINK | Água Fria - Extravasor e Limpeza 1
OutPort_7509259_2 | SOURCE | Água Fria - Extravasor e Limpeza 1
InPort_7509347_2 | SINK | Água Fria - Extravasor e Limpeza 1
OutPort_7509251_1 | SOURCE | Água Fria - Extravasor e Limpeza 1
InPort_7509313_2 | SINK | Água Fria - Extravasor e Limpeza 1
OutPort_7509324_1 | SOURCE | Água Fria - Extravasor e Limpeza 1
InPort_7509324_0 | SINK | Água Fria - Extravasor e Limpeza 1
OutPort_7509347_1 | SOURCE | Água Fria - Extravasor e Limpeza 1
InPort_7510374_0 | SINK | Água Pluvial 8
OutPort_7510373_1 | SOURCE | Água Pluvial 8
InPort_7510378_1 | SINK | Água Pluvial 8
OutPort_7510374_1 | SOURCE | Água Pluvial 8
InPort_7510376_0 | SINK | Água Pluvial 8
OutPort_7510378_2 | SOURCE | Água Pluvial 8
InPort_7510382_1 | SINK | Água Pluvial 8
OutPort_7510376_1 | SOURCE | Água Pluvial 8
InPort_7510380_0 | SINK | Água Pluvial 8
OutPort_7510382_2 | SOURCE | Água Pluvial 8
InPort_7510386_1 | SINK | Água Pluvial 8
OutPort_7510380_1 | SOURCE | Água Pluvial 8
OutPort_7510386_2 | SOURCE | Água Pluvial 8
InPort_7510389_0 | SINK | Água Pluvial 10
OutPort_7510388_1 | SOURCE | Água Pluvial 10
InPort_7510393_1 | SINK | Água Pluvial 10
OutPort_7510389_1 | SOURCE | Água Pluvial 10
InPort_7510391_0 | SINK | Água Pluvial 10
OutPort_7510393_2 | SOURCE | Água Pluvial 10
InPort_7510397_1 | SINK | Água Pluvial 10
OutPort_7510391_1 | SOURCE | Água Pluvial 10
InPort_7510395_0 | SINK | Água Pluvial 10
OutPort_7510397_2 | SOURCE | Água Pluvial 10
InPort_7510401_1 | SINK | Água Pluvial 10
OutPort_7510395_1 | SOURCE | Água Pluvial 10
OutPort_7510401_2 | SOURCE | Água Pluvial 10
InPort_7510404_0 | SINK | Água Pluvial 12
OutPort_7510403_1 | SOURCE | Água Pluvial 12
InPort_7510408_1 | SINK | Água Pluvial 12
OutPort_7510404_1 | SOURCE | Água Pluvial 12
InPort_7510406_0 | SINK | Água Pluvial 12
OutPort_7510408_2 | SOURCE | Água Pluvial 12
InPort_7510412_1 | SINK | Água Pluvial 12
OutPort_7510406_1 | SOURCE | Água Pluvial 12
InPort_7510410_0 | SINK | Água Pluvial 12
OutPort_7510412_2 | SOURCE | Água Pluvial 12
InPort_7510416_1 | SINK | Água Pluvial 12
OutPort_7510410_1 | SOURCE | Água Pluvial 12
OutPort_7510416_2 | SOURCE | Água Pluvial 12
InPort_7510419_0 | SINK | Água Pluvial 14
OutPort_7510418_1 | SOURCE | Água Pluvial 14
InPort_7510423_1 | SINK | Água Pluvial 14
OutPort_7510419_1 | SOURCE | Água Pluvial 14
InPort_7510421_0 | SINK | Água Pluvial 14
OutPort_7510423_2 | SOURCE | Água Pluvial 14
InPort_7510427_1 | SINK | Água Pluvial 14
OutPort_7510421_1 | SOURCE | Água Pluvial 14
InPort_7510425_0 | SINK | Água Pluvial 14
OutPort_7510427_2 | SOURCE | Água Pluvial 14
InPort_7510431_1 | SINK | Água Pluvial 14
OutPort_7510425_1 | SOURCE | Água Pluvial 14
OutPort_7510431_2 | SOURCE | Água Pluvial 14
InPort_7510434_0 | SINK | Água Pluvial 19
OutPort_7510433_1 | SOURCE | Água Pluvial 19
InPort_7510438_1 | SINK | Água Pluvial 19
OutPort_7510434_1 | SOURCE | Água Pluvial 19
InPort_7510436_0 | SINK | Água Pluvial 19
OutPort_7510438_2 | SOURCE | Água Pluvial 19
InPort_7510442_1 | SINK | Água Pluvial 19
OutPort_7510436_1 | SOURCE | Água Pluvial 19
InPort_7510440_0 | SINK | Água Pluvial 19
OutPort_7510442_2 | SOURCE | Água Pluvial 19
InPort_7510446_1 | SINK | Água Pluvial 19
OutPort_7510440_1 | SOURCE | Água Pluvial 19
OutPort_7510446_2 | SOURCE | Água Pluvial 19
InPort_7510449_0 | SINK | Água Pluvial 21
OutPort_7510448_1 | SOURCE | Água Pluvial 21
InPort_7510453_1 | SINK | Água Pluvial 21
OutPort_7510449_1 | SOURCE | Água Pluvial 21
InPort_7510451_0 | SINK | Água Pluvial 21
OutPort_7510453_2 | SOURCE | Água Pluvial 21
InPort_7510457_1 | SINK | Água Pluvial 21
OutPort_7510451_1 | SOURCE | Água Pluvial 21
InPort_7510455_0 | SINK | Água Pluvial 21
OutPort_7510457_2 | SOURCE | Água Pluvial 21
InPort_7510461_1 | SINK | Água Pluvial 21
OutPort_7510455_1 | SOURCE | Água Pluvial 21
OutPort_7510461_2 | SOURCE | Água Pluvial 21
InPort_7510464_0 | SINK | Água Pluvial 23
OutPort_7510463_1 | SOURCE | Água Pluvial 23
InPort_7510468_1 | SINK | Água Pluvial 23
OutPort_7510464_1 | SOURCE | Água Pluvial 23
InPort_7510466_0 | SINK | Água Pluvial 23
OutPort_7510468_2 | SOURCE | Água Pluvial 23
InPort_7510472_1 | SINK | Água Pluvial 23
OutPort_7510466_1 | SOURCE | Água Pluvial 23
InPort_7510470_0 | SINK | Água Pluvial 23
OutPort_7510472_2 | SOURCE | Água Pluvial 23
InPort_7510476_1 | SINK | Água Pluvial 23
OutPort_7510470_1 | SOURCE | Água Pluvial 23
OutPort_7510476_2 | SOURCE | Água Pluvial 23
InPort_7510479_0 | SINK | Água Pluvial 25
OutPort_7510478_1 | SOURCE | Água Pluvial 25
InPort_7510483_1 | SINK | Água Pluvial 25
OutPort_7510479_1 | SOURCE | Água Pluvial 25
InPort_7510481_0 | SINK | Água Pluvial 25
OutPort_7510483_2 | SOURCE | Água Pluvial 25
InPort_7510487_1 | SINK | Água Pluvial 25
OutPort_7510481_1 | SOURCE | Água Pluvial 25
InPort_7510485_0 | SINK | Água Pluvial 25
OutPort_7510487_2 | SOURCE | Água Pluvial 25
InPort_7510491_1 | SINK | Água Pluvial 25
OutPort_7510485_1 | SOURCE | Água Pluvial 25
OutPort_7510491_2 | SOURCE | Água Pluvial 25
Port_7510603_1 | SOURCEANDSINK
Port_7510603_2 | SOURCEANDSINK
Port_7510726_1 | SOURCEANDSINK
Port_7510726_2 | SOURCEANDSINK
Port_7510773_1 | SOURCEANDSINK
Port_7510773_2 | SOURCEANDSINK
Port_7511192_1 | SOURCEANDSINK
Port_7511192_2 | SOURCEANDSINK
Port_7511332_1 | SOURCEANDSINK
Port_7511332_2 | SOURCEANDSINK
Port_7511494_1 | SOURCEANDSINK
Port_7511494_2 | SOURCEANDSINK

# IfcFlowController: Hidrômetro_Com Caixa de Proteção_Rodrigo MEP:Caixa de Proteção para Hidrômetro, Hidrômetro_Com Caixa de Proteção_Rodrigo MEP:Caixa de Proteção para Hidrômetro:7474886
In: TÉRREO
Type - Material: .CONCRETO, <Unnamed>
Type - Pset_ManufacturerTypeInformation - Manufacturer: -
Material: <Unnamed>, Laminate, Navy, .CONCRETO, PVC, Flexible, Plastic, Opaque Black; Group: Água Fria - Extravasor e Limpeza 3
Pset_DistributionFlowElementCommon - Reference: Caixa de Proteção para Hidrômetro; sets with these values: 2

# IfcFlowController: Registro Esfera Soldável_Agua Fria_Rodrigo MEP:Registro de Esfera_Ø32 mm (3)
Type - Material: Phenolic Resin, PVC Marrom
Type - Pset_ManufacturerTypeInformation - Manufacturer: Tigre
Pset_DistributionFlowElementCommon - Reference: Registro de Esfera_Ø32 mm; sets with these values: 2
Group: Água Fria - Extravasor e Limpeza 2
Name (Registro Esfera Soldável_Agua Fria_Rodrigo MEP:Registro de Esfera_Ø32 mm:...) | In
7389462 | DRENAGEM PLUVIAL - PLANTA DE COBERTURA
7389510 | DRENAGEM PLUVIAL - PLANTA DE COBERTURA
7436991 | TÉRREO

# IfcFlowController: Registro Esfera Soldável_Agua Fria_Rodrigo MEP:Registro de Esfera_Ø50 mm (2)
In: DRENAGEM PLUVIAL - PLANTA DE COBERTURA
Type - Material: Phenolic Resin, PVC Marrom
Type - Pset_ManufacturerTypeInformation - Manufacturer: Tigre
Pset_DistributionFlowElementCommon - Reference: Registro de Esfera_Ø50 mm; sets with these values: 2
Name (Registro Esfera Soldável_Agua Fria_Rodrigo MEP:Registro de Esfera_Ø50 mm:...) | Group
7435403 | Água Fria 9
7435461 | Água Fria 1

# IfcFlowController: Registro Esfera Soldável_Agua Fria_Rodrigo MEP:Registro de Esfera_Ø60 mm (3)
In: DRENAGEM PLUVIAL - PLANTA DE COBERTURA
Type - Material: Phenolic Resin, PVC Marrom
Type - Pset_ManufacturerTypeInformation - Manufacturer: Tigre
Pset_DistributionFlowElementCommon - Reference: Registro de Esfera_Ø60 mm; sets with these values: 2
Group: Água Fria - Extravasor e Limpeza 1
Name (Registro Esfera Soldável_Agua Fria_Rodrigo MEP:Registro de Esfera_Ø60 mm:...)
7434855
7434999
7488132

# IfcFlowController: Registro de Gaveta__Rodrigo MEP:g. RG_Ø3/4" (25mm) com acabamento (19)
In: TÉRREO
Type - Material: BRONZE, Branco - Docol, .BRANCO
Type - Pset_ManufacturerTypeInformation - Manufacturer: Docol
Material: .BRANCO, Branco - Docol, BRONZE
Pset_DistributionFlowElementCommon - Reference: g. RG_Ø3/4" (25mm) com acabamento; sets with these values: 2
Name (Registro de Gaveta__Rodrigo MEP:g. RG_Ø3/4" (25mm) com acabamento:...) | Group
7382415 | Água Fria - Extravasor e Limpeza 1
7382595 | Água Fria - Extravasor e Limpeza 1
7382981 | Água Fria - Extravasor e Limpeza 1
7383585 | Água Fria - Extravasor e Limpeza 1
7383638 | Água Fria - Extravasor e Limpeza 1
7383770 | Água Fria 9
7383921 | Água Fria 9
7384386 | Água Fria 9
7384782 | Água Fria 9
7385018 | Água Fria 1
7385182 | Água Fria 1
7385306 | Água Fria - Extravasor e Limpeza 1
7385555 | Água Fria - Extravasor e Limpeza 1
7432426 | Água Fria 1
7447290 | Água Fria - Extravasor e Limpeza 1
7485723 | Água Fria - Extravasor e Limpeza 1
7485752 | Água Fria - Extravasor e Limpeza 1
7487079 | Água Fria - Extravasor e Limpeza 1
7487093 | Água Fria - Extravasor e Limpeza 1

# IfcFlowController: Registro de Gaveta__Rodrigo MEP:j. RG_1 1/2" (50mm) com acabamento (6)
In: TÉRREO
Type - Material: BRONZE, Branco - Docol, .BRANCO
Type - Pset_ManufacturerTypeInformation - Manufacturer: Docol
Material: .BRANCO, Branco - Docol, BRONZE
Pset_DistributionFlowElementCommon - Reference: j. RG_1 1/2" (50mm) com acabamento; sets with these values: 2
Name (Registro de Gaveta__Rodrigo MEP:j. RG_1 1/2" (50mm) com acabamento:...) | Group
7033167 | Água Fria - Extravasor e Limpeza 1
7033647 | Água Fria - Extravasor e Limpeza 1
7380722 | Água Fria - Extravasor e Limpeza 1
7380803 | Água Fria 1
7380969 | Água Fria 9
7429214 | Água Fria - Extravasor e Limpeza 1

# IfcFlowController: Registro de Pressão para Chuveiro_Rodrigo MEP:d. RP_Ø3/4" (25mm) com acabamento (2)
In: TÉRREO
Type - Material: .BRANCO, BRONZE, Branco - Docol
Type - Pset_ManufacturerTypeInformation - Manufacturer: Docol
Pset_DistributionFlowElementCommon - Reference: d. RP_Ø3/4" (25mm) com acabamento; sets with these values: 2
Group: Água Fria - Extravasor e Limpeza 1
Name (Registro de Pressão para Chuveiro_Rodrigo MEP:d. RP_Ø3/4" (25mm) com acabamento:...)
7032074
7385562

# IfcFlowFitting: Adaptador Soldavel com Anel p Caixa Dagua - Fortlev - AleBim:Standard (9)
In: DRENAGEM PLUVIAL - PLANTA DE COBERTURA
Type - Material: PVC Marrom
Type - Pset_ManufacturerTypeInformation - Manufacturer: FortLev
Pset_DistributionFlowElementCommon - Reference: Standard; sets with these values: 2
Name (Adaptador Soldavel com Anel p Caixa Dagua - Fortlev - AleBim:Standard:...)
7132677
7132678
7132679
7132680
7133906
7133907
7135410
7438258
7451061

# IfcFlowFitting: Calha Galvanizada Retangular - Calha_Rodrigo MEP:Calha Galvanizada, 130x90mm (2)
In: DRENAGEM PLUVIAL - PLANTA DE COBERTURA
Type - Material: .CINZA
Type - Pset_ManufacturerTypeInformation - Manufacturer: -
Pset_DistributionFlowElementCommon - Reference: Calha Galvanizada, 130x90mm; sets with these values: 2
Name (Calha Galvanizada Retangular - Calha_Rodrigo MEP:Calha Galvanizada, 130x90mm:...)
7510773
7511192

# IfcFlowFitting: Calha Galvanizada Retangular - Calha_Rodrigo MEP:Calha Galvanizada, 250x100mm (10)
In: DRENAGEM PLUVIAL - PLANTA DE COBERTURA
Type - Material: .CINZA
Type - Pset_ManufacturerTypeInformation - Manufacturer: -
Pset_DistributionFlowElementCommon - Reference: Calha Galvanizada, 250x100mm; sets with these values: 2
Name (Calha Galvanizada Retangular - Calha_Rodrigo MEP:Calha Galvanizada, 250x100mm:...)
7484271
7484528
7484816
7485295
7489120
7489959
7510603
7510726
7511332
7511494

# IfcFlowFitting: Curva 87 - Serie Reforcada - Esgoto - MEP - Tigre:Standard (58)
In: DRENAGEM PLUVIAL - PLANTA DE COBERTURA
Type - Material: PVC Bege Pérola
Type - Pset_ManufacturerTypeInformation - Manufacturer: © Tigre S/A
Pset_DistributionFlowElementCommon - Reference: Standard; sets with these values: 2
Name (Curva 87 - Serie Reforcada - Esgoto - MEP - Tigre:Standard:...) | Group
7192028 | Água Pluvial 1
7192061 | Água Pluvial 1
7192075 | Água Pluvial 1
7418412 | Água Pluvial 2
7418434 | Água Pluvial 2
7418469 | Água Pluvial 2
7418830 | Água Pluvial 3
7418832 | Água Pluvial 3
7418834 | Água Pluvial 3
7419048 | Água Pluvial 4
7419052 | Água Pluvial 4
7419056 | Água Pluvial 4
7419072 | Água Pluvial 5
7419076 | Água Pluvial 5
7419080 | Água Pluvial 5
7419120 | Água Pluvial 6
7419264 | Água Pluvial 6
7419323 | Água Pluvial 6
7419470 | Água Pluvial 6
7419515 | Água Pluvial 7
7419517 | Água Pluvial 7
7419521 | Água Pluvial 7
7419523 | Água Pluvial 7
7420816 | Água Pluvial 15
7421032 | Água Pluvial 15
7421063 | Água Pluvial 15
7421108 | Água Pluvial 15
7421408 | Água Pluvial 17
7421412 | Água Pluvial 17
7421416 | Água Pluvial 17
7421457 | Água Pluvial 17
7422320 | Água Pluvial 18
7422322 | Água Pluvial 18
7422324 | Água Pluvial 18
7510378 | Água Pluvial 8
7510382 | Água Pluvial 8
7510386 | Água Pluvial 8
7510393 | Água Pluvial 10
7510397 | Água Pluvial 10
7510401 | Água Pluvial 10
7510408 | Água Pluvial 12
7510412 | Água Pluvial 12
7510416 | Água Pluvial 12
7510423 | Água Pluvial 14
7510427 | Água Pluvial 14
7510431 | Água Pluvial 14
7510438 | Água Pluvial 19
7510442 | Água Pluvial 19
7510446 | Água Pluvial 19
7510453 | Água Pluvial 21
7510457 | Água Pluvial 21
7510461 | Água Pluvial 21
7510468 | Água Pluvial 23
7510472 | Água Pluvial 23
7510476 | Água Pluvial 23
7510483 | Água Pluvial 25
7510487 | Água Pluvial 25
7510491 | Água Pluvial 25

# IfcFlowFitting: Luva Soldavel com Bucha de Latao - Fortlev - AleBim:Standard (24)
In: TÉRREO
Type - Material: PVC Azul
Type - Pset_ManufacturerTypeInformation - Manufacturer: FortLev
Pset_DistributionFlowElementCommon - Reference: Standard; sets with these values: 2
Name (Luva Soldavel com Bucha de Latao - Fortlev - AleBim:Standard:...) | Group
7424491 | Dreno Ar 3
7440524 | Dreno Ar 2
7440650 | Dreno Ar 2
7440992 | Dreno Ar 4
7441157 | Dreno Ar 6
7441455 | Dreno Ar 5
7441480 | Dreno Ar 7
7441513 | Dreno Ar 8
7441715 | Dreno Ar 9
7442003 | Dreno Ar 11
7442150 | Dreno Ar 10
7442589 | Dreno Ar 14
7442639 | Dreno Ar 13
7442977 | Dreno Ar 17
7443115 | Dreno Ar 15
7443213 | Dreno Ar 12
7443295 | Dreno Ar 16
7443368 | Dreno Ar 18
7443440 | Dreno Ar 19
7443457 | Dreno Ar 21
7443566 | Dreno Ar 20
7443799 | Dreno Ar 23
7443804 | Dreno Ar 24
7443898 | Dreno Ar 27

# IfcFlowFitting: PVC Esgoto_Adaptador para Saida de Vaso Sanitario_Rodrigo MEP:Bacia Sanitária BS (6 UHC) (6)
In: TÉRREO
Type - Material: Preto, PVC Série Normal
Type - Pset_ManufacturerTypeInformation - Manufacturer: Tigre
Pset_DistributionFlowElementCommon - Reference: Bacia Sanitária BS (6 UHC); sets with these values: 2
Name (PVC Esgoto_Adaptador para Saida de Vaso Sanitario_Rodrigo MEP:Bacia Sanitária BS (6 UHC):...) | Group
7029972 | Esgoto Primário 10
7391105 | Esgoto Sanitário 7
7392505 | Esgoto Sanitário 17
7392582 | Esgoto Sanitário 18
7403513 | Esgoto Sanitário 49
7404857 | Esgoto Sanitário 50

# IfcFlowFitting: PVC Esgoto_Cap_Rodrigo MEP:a. Série Normal (3)
In: TÉRREO
Type - Material: PVC Série Normal
Type - Pset_ManufacturerTypeInformation - Manufacturer: Tigre
Pset_DistributionFlowElementCommon - Reference: a. Série Normal; sets with these values: 2
Name (PVC Esgoto_Cap_Rodrigo MEP:a. Série Normal:...) | Group
7497224 | Esgoto Sanitário 87
7497238 | Esgoto Sanitário 88
7497251 | Esgoto Sanitário 91

# IfcFlowFitting: PVC Esgoto_Curva 90° Curta:a. Série Normal (34)
In: TÉRREO
Type - Material: PVC Branco
Type - Pset_ManufacturerTypeInformation - Manufacturer: Tigre
Pset_DistributionFlowElementCommon - Reference: a. Série Normal; sets with these values: 2
Name (PVC Esgoto_Curva 90° Curta:a. Série Normal:...) | Group
7029736 | Esgoto Primário 7
7390308 | Esgoto Primário 10
7390897 | Esgoto Sanitário 3
7391051 | Esgoto Sanitário 4
7391111 | Esgoto Sanitário 7
7391532 | Esgoto Sanitário 8
7391897 | Esgoto Sanitário 9
7392074 | Esgoto Sanitário 10
7392588 | Esgoto Sanitário 18
7393336 | Esgoto Sanitário 20
7397354 | Esgoto Sanitário 24
7400453 | Esgoto Sanitário 30
7402154 | Esgoto Sanitário 34
7403025 | Esgoto Sanitário 38
7403086 | Esgoto Sanitário 37
7403153 | Esgoto Sanitário 39
7403481 | Esgoto Sanitário 42
7403579 | Esgoto Sanitário 49
7404474 | Esgoto Sanitário 46
7404556 | Esgoto Sanitário 48
7405571 | Esgoto Sanitário 53
7407247 | Esgoto Sanitário 58
7407315 | Esgoto Sanitário 59
7407366 | Esgoto Sanitário 57
7408889 | Esgoto Sanitário 64
7408948 | Esgoto Sanitário 66
7409309 | Esgoto Sanitário 65
7409395 | Esgoto Sanitário 68
7412950 | Esgoto Sanitário 31
7491257 | Esgoto Sanitário 15
7491899 | Esgoto Sanitário 29
7502599 | Esgoto Sanitário 50
7502690 | Esgoto Sanitário 84
7503503 | Esgoto Sanitário 17

# IfcFlowFitting: PVC Esgoto_Joelho 45_90 Aninhado_Rodrigo MEP:a. Série Normal, PVC Esgoto_Joelho 45_90 Aninhado_Rodrigo MEP:a. Série Normal:7495609
In: TÉRREO
Type - Material: PVC Série Normal
Type - Pset_ManufacturerTypeInformation - Manufacturer: Tigre
Pset_DistributionFlowElementCommon - Reference: a. Série Normal; sets with these values: 2

# IfcFlowFitting: PVC Esgoto_Joelho 45_90_Rodrigo MEP:a. Série Normal (96)
In: TÉRREO
Type - Material: PVC Série Normal
Type - Pset_ManufacturerTypeInformation - Manufacturer: Tigre
Pset_DistributionFlowElementCommon - Reference: a. Série Normal; sets with these values: 2
Name (PVC Esgoto_Joelho 45_90_Rodrigo MEP:a. Série Normal:...) | Group
7038239 | Esgoto - Ventilação 3
7038259 | Esgoto - Ventilação 3
7390674 | Esgoto Sanitário 1
7390753 | Esgoto Sanitário 2
7390838 | Esgoto Sanitário 2
7390907 | Esgoto Sanitário 3
7391055 | Esgoto Sanitário 4
7391512 | Esgoto Sanitário 8
7391536 | Esgoto Sanitário 8
7391901 | Esgoto Sanitário 9
7399092 | Esgoto - Ventilação 4
7399111 | Esgoto - Ventilação 4
7399147 | Esgoto - Ventilação 4
7399163 | Esgoto - Ventilação 4
7400206 | Esgoto Sanitário 27
7400732 | Esgoto Sanitário 30
7400990 | Esgoto - Ventilação 7
7401006 | Esgoto - Ventilação 7
7401487 | Esgoto Sanitário 27
7402002 | Esgoto Sanitário 33
7402018 | Esgoto Sanitário 33
7403090 | Esgoto Sanitário 37
7403157 | Esgoto Sanitário 39
7403493 | Esgoto - Ventilação 2
7403499 | Esgoto - Ventilação 2
7404048 | Esgoto Sanitário 43
7404252 | Esgoto Sanitário 43
7404560 | Esgoto Sanitário 48
7405207 | Esgoto Sanitário 52
7405577 | Esgoto Sanitário 53
7407251 | Esgoto Sanitário 58
7407297 | Esgoto Sanitário 59
7407319 | Esgoto Sanitário 59
7407370 | Esgoto Sanitário 57
7408893 | Esgoto Sanitário 64
7408952 | Esgoto Sanitário 66
7409296 | Esgoto Sanitário 65
7409382 | Esgoto Sanitário 68
7412059 | Esgoto - Ventilação 5
7412078 | Esgoto - Ventilação 5
7412169 | Esgoto - Ventilação 5
7412185 | Esgoto - Ventilação 5
7412483 | Esgoto - Ventilação 10
7412499 | Esgoto - Ventilação 10
7412521 | Esgoto - Ventilação 10
7412696 | Esgoto - Ventilação 10
7412712 | Esgoto - Ventilação 10
7413031 | Esgoto - Ventilação 11
7413047 | Esgoto - Ventilação 11
7413066 | Esgoto - Ventilação 11
7413283 | Esgoto - Ventilação 12
7413309 | Esgoto - Ventilação 12
7413462 | Esgoto - Ventilação 12
7413478 | Esgoto - Ventilação 12
7413550 | Esgoto - Ventilação 13
7413569 | Esgoto - Ventilação 13
7413638 | Esgoto - Ventilação 13
7413654 | Esgoto - Ventilação 13
7413822 | Esgoto - Ventilação 14
7413839 | Esgoto - Ventilação 14
7413862 | Esgoto - Ventilação 14
7413941 | Esgoto - Ventilação 14
7413957 | Esgoto - Ventilação 14
7414233 | Esgoto - Ventilação 16
7414249 | Esgoto - Ventilação 16
7414870 | Esgoto - Ventilação 15
7414886 | Esgoto - Ventilação 15
7414905 | Esgoto - Ventilação 15
7415538 | Esgoto - Ventilação 19
7415554 | Esgoto - Ventilação 19
7488184 | Esgoto - Ventilação 18
7488194 | Esgoto - Ventilação 18
7488204 | Esgoto - Ventilação 18
7491267 | Esgoto Sanitário 15
7492019 | Esgoto - Ventilação 1
7492039 | Esgoto - Ventilação 1
7492382 | Esgoto - Ventilação 1
7492398 | Esgoto - Ventilação 1
7502708 | Esgoto - Ventilação 9
7502718 | Esgoto - Ventilação 9
7502825 | Esgoto Sanitário 56
7502850 | Esgoto Sanitário 56
7503844 | Esgoto Sanitário 17
7503860 | Esgoto Sanitário 17
7504214 | Esgoto Sanitário 20
7504591 | Esgoto - Ventilação 6
7504611 | Esgoto - Ventilação 6
7504882 | Esgoto - Ventilação 6
7504898 | Esgoto - Ventilação 6
7505371 | Esgoto Sanitário 11
7505487 | Esgoto Sanitário 63
7505987 | Esgoto Sanitário 63
7506366 | Esgoto Sanitário 64
7506695 | Esgoto - Ventilação 17
7506711 | Esgoto - Ventilação 17
7507493 | Esgoto Sanitário 69

# IfcFlowFitting: PVC Esgoto_Joelho 90° com anel, DN40mm, para Aparelhos Sanitários_Rodrigo MEP:Bebedouro (0,5 UHC) 60cm do Piso (6)
In: TÉRREO
Type - Material: PVC Série Normal
Type - Pset_ManufacturerTypeInformation - Manufacturer: Tigre
Pset_DistributionFlowElementCommon - Reference: Bebedouro (0,5 UHC) 60cm do Piso; sets with these values: 2
Name (PVC Esgoto_Joelho 90° com anel, DN40mm, para Aparelhos Sanitários_Rodrigo MEP:Bebedouro (0,5 UHC) 60cm do Piso:...) | Group
7405253 | Esgoto Sanitário 53
7406668 | Esgoto Sanitário 57
7406707 | Esgoto Sanitário 59
7406719 | Esgoto Sanitário 58
7408344 | Esgoto Sanitário 66
7408401 | Esgoto Sanitário 64

# IfcFlowFitting: PVC Esgoto_Joelho 90° com anel, DN40mm, para Aparelhos Sanitários_Rodrigo MEP:Lavatório de Uso Geral LV (2 UHC) 50cm do Piso (15)
In: TÉRREO
Type - Material: PVC Série Normal
Type - Pset_ManufacturerTypeInformation - Manufacturer: Tigre
Pset_DistributionFlowElementCommon - Reference: Lavatório de Uso Geral LV (2 UHC) 50cm do Piso; sets with these values: 2
Name (PVC Esgoto_Joelho 90° com anel, DN40mm, para Aparelhos Sanitários_Rodrigo MEP:Lavatório de Uso Geral LV (2 UHC) 50cm do Piso:...) | Group
7390845 | Esgoto Sanitário 3
7390981 | Esgoto Sanitário 4
7391229 | Esgoto Sanitário 8
7391275 | Esgoto Sanitário 10; Esgoto Sanitário 13
7391618 | Esgoto Sanitário 9; Esgoto Sanitário 12
7393067 | Esgoto Sanitário 20
7401636 | Esgoto Sanitário 31; Esgoto Sanitário 32
7402067 | Esgoto Sanitário 34; Esgoto Sanitário 35
7402841 | Esgoto Sanitário 37
7402857 | Esgoto Sanitário 39
7402901 | Esgoto Sanitário 38
7404263 | Esgoto Sanitário 46; Esgoto Sanitário 47
7404506 | Esgoto Sanitário 48
7491181 | Esgoto Sanitário 15
7491484 | Esgoto Sanitário 82; Esgoto Sanitário 29

# IfcFlowFitting: PVC Esgoto_Joelho 90° com anel, DN40mm, para Aparelhos Sanitários_Rodrigo MEP:Lavatório de Uso Geral LV (2 UHC) 60cm do Piso (3)
In: TÉRREO
Type - Material: PVC Série Normal
Type - Pset_ManufacturerTypeInformation - Manufacturer: Tigre
Pset_DistributionFlowElementCommon - Reference: Lavatório de Uso Geral LV (2 UHC) 60cm do Piso; sets with these values: 2
Name (PVC Esgoto_Joelho 90° com anel, DN40mm, para Aparelhos Sanitários_Rodrigo MEP:Lavatório de Uso Geral LV (2 UHC) 60cm do Piso:...) | Group
7029388 | Esgoto Primário 7
7403470 | Esgoto Sanitário 42
7502682 | Esgoto Sanitário 84; Esgoto Sanitário 98

# IfcFlowFitting: PVC Esgoto_Joelho 90° com anel, DN40mm, para Aparelhos Sanitários_Rodrigo MEP:Tanque TN (3 UHC) 50cm do Piso, PVC Esgoto_Joelho 90° com anel, DN40mm, para Aparelhos Sanitários_Rodrigo MEP:Tanque TN (3 UHC) 50cm do Piso:7399608
In: TÉRREO
Type - Material: PVC Série Normal
Type - Pset_ManufacturerTypeInformation - Manufacturer: Tigre
Pset_DistributionFlowElementCommon - Reference: Tanque TN (3 UHC) 50cm do Piso; sets with these values: 2
Group: Esgoto Sanitário 30

# IfcFlowFitting: PVC Esgoto_Joelho 90°, DN50mm, para Aparelhos Sanitários_Rodrigo MEP:Pia de Cozinha Residencial (3 UHC) 50cm do Piso, PVC Esgoto_Joelho 90°, DN50mm, para Aparelhos Sanitários_Rodrigo MEP:Pia de Cozinha Residencial (3 UHC) 50cm do Piso:7397277
In: TÉRREO
Type - Material: PVC Série Normal
Type - Pset_ManufacturerTypeInformation - Manufacturer: Tigre
Pset_DistributionFlowElementCommon - Reference: Pia de Cozinha Residencial (3 UHC) 50cm do Piso; sets with these values: 2
Group: Esgoto Sanitário 24

# IfcFlowFitting: PVC Esgoto_Luva Simples para Conexão_Rodrigo MEP:Standard (103)
In: TÉRREO
Type - Material: PVC Série Normal
Type - Pset_ManufacturerTypeInformation - Manufacturer: Tigre
Pset_DistributionFlowElementCommon - Reference: Standard; sets with these values: 2
Name (PVC Esgoto_Luva Simples para Conexão_Rodrigo MEP:Standard:...)
7038261
7038278
7390312
7391113
7392590
7397279
7397378
7397424
7399094
7399113
7399149
7399165
7400208
7400954
7400992
7401008
7401254
7401490
7402004
7402042
7403501
7403507
7403581
7404112
7404254
7405209
7412061
7412080
7412171
7412187
7412414
7412502
7412523
7412698
7412714
7412984
7413033
7413049
7413068
7413231
7413285
7413311
7413416
7413464
7413480
7413552
7413571
7413640
7413656
7413705
7413825
7413841
7413864
7413943
7413959
7414212
7414235
7414251
7414626
7414862
7414888
7414907
7415523
7415540
7415556
7416419
7416580
7417644
7479424
7488186
7488196
7488206
7491387
7492041
7492057
7492384
7492400
7495580
7495584
7495598
7502603
7502698
7502710
7502720
7502827
7502853
7503507
7503846
7503862
7503887
7504614
7504639
7504884
7504900
7505200
7505373
7505489
7505767
7505989
7506667
7506697
7506713
7507495

# IfcFlowFitting: PVC Esgoto_Redução Excentrica_Rodrigo MEP:a. Série Normal (2)
In: TÉRREO
Type - Material: PVC Série Normal
Type - Pset_ManufacturerTypeInformation - Manufacturer: Tigre
Pset_DistributionFlowElementCommon - Reference: a. Série Normal; sets with these values: 2
Name (PVC Esgoto_Redução Excentrica_Rodrigo MEP:a. Série Normal:...) | Group
7503945 | Esgoto Sanitário 17
7505834 | Esgoto Sanitário 63

# IfcFlowFitting: PVC Esgoto_Terminal de Ventilação_Rodrigo MEP:a. Série Normal (17)
In: TÉRREO
Type - Material: PVC Série Normal
Type - Pset_ManufacturerTypeInformation - Manufacturer: Tigre
Pset_DistributionFlowElementCommon - Reference: a. Série Normal; sets with these values: 2
Name (PVC Esgoto_Terminal de Ventilação_Rodrigo MEP:a. Série Normal:...) | Group
7399192 | Esgoto - Ventilação 4
7401035 | Esgoto - Ventilação 7
7412237 | Esgoto - Ventilação 5
7412741 | Esgoto - Ventilação 10
7413205 | Esgoto - Ventilação 11
7413508 | Esgoto - Ventilação 12
7413683 | Esgoto - Ventilação 13
7413991 | Esgoto - Ventilação 14
7414279 | Esgoto - Ventilação 16
7415004 | Esgoto - Ventilação 15
7415583 | Esgoto - Ventilação 19
7438639 | Esgoto - Ventilação 2
7488212 | Esgoto - Ventilação 18
7492418 | Esgoto - Ventilação 1
7502726 | Esgoto - Ventilação 9
7504916 | Esgoto - Ventilação 6
7506739 | Esgoto - Ventilação 17

# IfcFlowFitting: PVC Esgoto_Tê_Juncão_Rodrigo MEP Aninhado:a. Série Normal (4)
In: TÉRREO
Type - Material: PVC Série Normal
Type - Pset_ManufacturerTypeInformation - Manufacturer: Tigre
Pset_DistributionFlowElementCommon - Reference: a. Série Normal; sets with these values: 2
Name (PVC Esgoto_Tê_Juncão_Rodrigo MEP Aninhado:a. Série Normal:...)
7397423
7495573
7495574
7495590

# IfcFlowFitting: PVC Esgoto_Tê_Juncão_Rodrigo MEP:a. Série Normal (24)
In: TÉRREO
Type - Material: PVC Série Normal
Type - Pset_ManufacturerTypeInformation - Manufacturer: Tigre
Pset_DistributionFlowElementCommon - Reference: a. Série Normal; sets with these values: 2
Name (PVC Esgoto_Tê_Juncão_Rodrigo MEP:a. Série Normal:...) | Group
7038226 | Esgoto Primário 8; Esgoto - Ventilação 3
7399080 | Esgoto Sanitário 11; Esgoto - Ventilação 4
7400950 | Esgoto Sanitário 27; Esgoto - Ventilação 7
7401249 | Esgoto Sanitário 27
7403485 | Esgoto Sanitário 44; Esgoto - Ventilação 2
7404107 | Esgoto Sanitário 43
7412047 | Esgoto Sanitário 33; Esgoto - Ventilação 5
7412314 | Esgoto Sanitário 36
7412470 | Esgoto Sanitário 27; Esgoto - Ventilação 10
7413019 | Esgoto Sanitário 43; Esgoto - Ventilação 11
7413271 | Esgoto Sanitário 43; Esgoto - Ventilação 12
7413538 | Esgoto Sanitário 52; Esgoto - Ventilação 13
7413810 | Esgoto Sanitário 56; Esgoto - Ventilação 14
7414208 | Esgoto Sanitário 63; Esgoto - Ventilação 16
7414858 | Esgoto Sanitário 6; Esgoto - Ventilação 15
7415519 | Esgoto Sanitário 1; Esgoto - Ventilação 19
7491365 | Esgoto Sanitário 16; Esgoto - Ventilação 20
7492007 | Esgoto Sanitário 11; Esgoto - Ventilação 1
7502694 | Esgoto Sanitário 60; Esgoto - Ventilação 9
7503883 | Esgoto Sanitário 17
7504578 | Esgoto Sanitário 17
7505195 | Esgoto Sanitário 11
7505765 | Esgoto Sanitário 63
7506663 | Esgoto Sanitário 63

# IfcFlowFitting: PVC Marrom Soldável_Adaptador Curto com Bolsa e Rosca Aninhado_Rodrigo MEP:Adaptador (58)
In: TÉRREO
Type - Material: PVC Marrom
Type - Pset_ManufacturerTypeInformation - Manufacturer: Tigre
Pset_DistributionFlowElementCommon - Reference: Adaptador; sets with these values: 2
Name (PVC Marrom Soldável_Adaptador Curto com Bolsa e Rosca Aninhado_Rodrigo MEP:Adaptador:...)
7032075
7033168
7033169
7033645
7033648
7033649
7380720
7380723
7380724
7380801
7380804
7380805
7380967
7380970
7380971
7382416
7382417
7382596
7382597
7382982
7382983
7383586
7383587
7383639
7383640
7383771
7383772
7383922
7383923
7384387
7384388
7384783
7384784
7385019
7385020
7385183
7385184
7385307
7385308
7385488
7385556
7385557
7385563
7427229
7429215
7429216
7432427
7432428
7447291
7447292
7485724
7485725
7485753
7485754
7487080
7487081
7487094
7487095

# IfcFlowFitting: PVC Marrom Soldável_Bucha de Reducão Curta_Rodrigo MEP:Bucha de Redução Curta (9)
In: TÉRREO
Type - Material: PVC Marrom
Type - Pset_ManufacturerTypeInformation - Manufacturer: Tigre
Pset_DistributionFlowElementCommon - Reference: Bucha de Redução Curta; sets with these values: 2
Name (PVC Marrom Soldável_Bucha de Reducão Curta_Rodrigo MEP:Bucha de Redução Curta:...) | Group
7389079 | Água Fria - Extravasor e Limpeza 1
7389731 | Água Fria - Extravasor e Limpeza 1
7389902 | Água Fria - Extravasor e Limpeza 1
7389983 | Água Fria - Extravasor e Limpeza 1
7475683 | Água Fria 2
7487359 | Água Fria - Extravasor e Limpeza 1
7492646 | Água Fria 9
7492648 | Água Fria 9
7501647 | Água Fria 9

# IfcFlowFitting: PVC Marrom Soldável_Bucha de Reducão Longa_Rodrigo MEP:Bucha de Redução (10)
In: TÉRREO
Type - Material: PVC Marrom
Type - Pset_ManufacturerTypeInformation - Manufacturer: Tigre
Pset_DistributionFlowElementCommon - Reference: Bucha de Redução; sets with these values: 2
Name (PVC Marrom Soldável_Bucha de Reducão Longa_Rodrigo MEP:Bucha de Redução:...) | Group
7387085 | Água Fria - Extravasor e Limpeza 1
7387855 | Água Fria - Extravasor e Limpeza 1
7387897 | Água Fria - Extravasor e Limpeza 1
7389049 | Água Fria - Extravasor e Limpeza 1
7389145 | Água Fria - Extravasor e Limpeza 1
7475392 | Água Fria - Extravasor e Limpeza 1
7486725 | Água Fria 9
7487250 | Água Fria - Extravasor e Limpeza 1
7501715 | Água Fria - Extravasor e Limpeza 1
7501960 | Água Fria - Extravasor e Limpeza 1

# IfcFlowFitting: PVC Marrom Soldável_Curva 45°_90°_Rodrigo MEP:Curva (19)
Type - Material: PVC Marrom
Type - Pset_ManufacturerTypeInformation - Manufacturer: Tigre
Pset_DistributionFlowElementCommon - Reference: Curva; sets with these values: 2
Name (PVC Marrom Soldável_Curva 45°_90°_Rodrigo MEP:Curva:...) | In | Group
7031451 | TÉRREO | Água Fria - Extravasor e Limpeza 1
7377896 | TÉRREO | Água Fria - Extravasor e Limpeza 1
7377898 | TÉRREO | Água Fria - Extravasor e Limpeza 1
7385551 | TÉRREO | Água Fria - Extravasor e Limpeza 1
7385554 | TÉRREO | Água Fria - Extravasor e Limpeza 1
7386160 | DRENAGEM PLUVIAL - PLANTA DE COBERTURA | Água Fria 1
7386168 | DRENAGEM PLUVIAL - PLANTA DE COBERTURA | Água Fria 1
7386593 | TÉRREO | Água Fria - Extravasor e Limpeza 1
7386806 | DRENAGEM PLUVIAL - PLANTA DE COBERTURA | Água Fria - Extravasor e Limpeza 1
7387979 | TÉRREO | Água Fria 1
7388678 | DRENAGEM PLUVIAL - PLANTA DE COBERTURA | Água Fria 9
7388686 | DRENAGEM PLUVIAL - PLANTA DE COBERTURA | Água Fria 9
7388761 | DRENAGEM PLUVIAL - PLANTA DE COBERTURA | Água Fria 9
7486542 | DRENAGEM PLUVIAL - PLANTA DE COBERTURA | Água Fria - Extravasor e Limpeza 1
7487016 | DRENAGEM PLUVIAL - PLANTA DE COBERTURA | Água Fria - Extravasor e Limpeza 1
7488005 | DRENAGEM PLUVIAL - PLANTA DE COBERTURA | Água Fria - Extravasor e Limpeza 1
7488015 | DRENAGEM PLUVIAL - PLANTA DE COBERTURA | Água Fria - Extravasor e Limpeza 1
7493223 | DRENAGEM PLUVIAL - PLANTA DE COBERTURA | Água Fria - Extravasor e Limpeza 1
7493231 | DRENAGEM PLUVIAL - PLANTA DE COBERTURA | Água Fria - Extravasor e Limpeza 1

# IfcFlowFitting: PVC Marrom Soldável_Curva de Transposicao_Rodrigo MEP1:Curva de Transposição 2 (2)
In: TÉRREO
Type - Material: PVC Marrom
Type - Pset_ManufacturerTypeInformation - Manufacturer: Tigre
Pset_DistributionFlowElementCommon - Reference: Curva de Transposição 2; sets with these values: 2
Name (PVC Marrom Soldável_Curva de Transposicao_Rodrigo MEP1:Curva de Transposição 2:...) | Group
7416091 | Água Fria - Extravasor e Limpeza 1
7417016 | Água Fria 9

# IfcFlowFitting: PVC Marrom Soldável_Joelho 45°_90°_Rodrigo MEP:Joelho (144)
Type - Material: PVC Marrom
Type - Pset_ManufacturerTypeInformation - Manufacturer: Tigre
Pset_DistributionFlowElementCommon - Reference: Joelho; sets with these values: 2
Name (PVC Marrom Soldável_Joelho 45°_90°_Rodrigo MEP:Joelho:...) | In | Group
7377770 | TÉRREO | Água Fria - Extravasor e Limpeza 1
7380743 | TÉRREO | Água Fria - Extravasor e Limpeza 1
7380745 | TÉRREO | Água Fria - Extravasor e Limpeza 1
7380747 | TÉRREO | Água Fria - Extravasor e Limpeza 1
7380824 | TÉRREO | Água Fria 1
7380826 | TÉRREO | Água Fria 1
7380828 | TÉRREO | Água Fria 1
7380990 | TÉRREO | Água Fria 9
7380992 | TÉRREO | Água Fria 9
7380994 | TÉRREO | Água Fria 9
7383086 | TÉRREO | Água Fria - Extravasor e Limpeza 1
7383177 | TÉRREO | Água Fria - Extravasor e Limpeza 1
7383294 | TÉRREO | Água Fria - Extravasor e Limpeza 1
7383564 | TÉRREO | Água Fria - Extravasor e Limpeza 1
7383777 | TÉRREO | Água Fria 9
7384190 | TÉRREO | Água Fria 9
7384202 | TÉRREO | Água Fria 9
7384393 | TÉRREO | Água Fria 9
7384639 | TÉRREO | Água Fria 9
7385180 | TÉRREO | Água Fria 1
7385313 | TÉRREO | Água Fria - Extravasor e Limpeza 1
7385504 | TÉRREO | Água Fria - Extravasor e Limpeza 1
7386510 | TÉRREO | Água Fria - Extravasor e Limpeza 1
7386739 | TÉRREO | Água Fria - Extravasor e Limpeza 1
7386743 | TÉRREO | Água Fria - Extravasor e Limpeza 1
7387071 | TÉRREO | Água Fria - Extravasor e Limpeza 1
7387075 | TÉRREO | Água Fria - Extravasor e Limpeza 1
7387137 | TÉRREO | Água Fria 1
7387851 | TÉRREO | Água Fria - Extravasor e Limpeza 1
7387908 | TÉRREO | Água Fria - Extravasor e Limpeza 1
7387912 | TÉRREO | Água Fria - Extravasor e Limpeza 1
7388571 | TÉRREO | Água Fria 9
7388575 | TÉRREO | Água Fria 9
7388602 | TÉRREO | Água Fria 9
7388606 | TÉRREO | Água Fria 9
7388757 | TÉRREO | Água Fria 9
7388818 | TÉRREO | Água Fria 1
7388879 | TÉRREO | Água Fria - Extravasor e Limpeza 1
7388926 | TÉRREO | Água Fria - Extravasor e Limpeza 1
7388945 | TÉRREO | Água Fria - Extravasor e Limpeza 1
7389045 | TÉRREO | Água Fria - Extravasor e Limpeza 1
7389126 | TÉRREO | Água Fria - Extravasor e Limpeza 1
7389700 | TÉRREO | Água Fria - Extravasor e Limpeza 1
7389791 | TÉRREO | Água Fria 9
7424497 | TÉRREO | Dreno Ar 3
7432859 | TÉRREO | Água Fria Alimentação 5
7436000 | DRENAGEM PLUVIAL - PLANTA DE COBERTURA | Água Fria - Extravasor e Limpeza 2
7436398 | TÉRREO | Água Fria - Extravasor e Limpeza 2
7436546 | DRENAGEM PLUVIAL - PLANTA DE COBERTURA | Água Fria - Extravasor e Limpeza 2
7436563 | TÉRREO | Água Fria - Extravasor e Limpeza 2
7436934 | DRENAGEM PLUVIAL - PLANTA DE COBERTURA | Água Fria - Extravasor e Limpeza 2
7439112 | TÉRREO | Água Fria Alimentação 5
7440530 | TÉRREO | Dreno Ar 2
7440656 | TÉRREO | Dreno Ar 2
7440693 | TÉRREO | Dreno Ar 2
7440710 | TÉRREO | Dreno Ar 2
7440722 | TÉRREO | Dreno Ar 2
7440916 | TÉRREO | Dreno Ar 2
7440920 | TÉRREO | Dreno Ar 2
7440947 | TÉRREO | Dreno Ar 3
7440964 | TÉRREO | Dreno Ar 3
7440998 | TÉRREO | Dreno Ar 4
7441000 | TÉRREO | Dreno Ar 4
7441163 | TÉRREO | Dreno Ar 6
7441187 | TÉRREO | Dreno Ar 6
7441214 | TÉRREO | Dreno Ar 6
7441461 | TÉRREO | Dreno Ar 5
7441486 | TÉRREO | Dreno Ar 7
7441519 | TÉRREO | Dreno Ar 8
7441521 | TÉRREO | Dreno Ar 8
7441569 | TÉRREO | Dreno Ar 7
7441654 | TÉRREO | Dreno Ar 5
7441667 | TÉRREO | Dreno Ar 5
7441721 | TÉRREO | Dreno Ar 9
7441723 | TÉRREO | Dreno Ar 9
7441727 | TÉRREO | Dreno Ar 9
7442009 | TÉRREO | Dreno Ar 11
7442123 | TÉRREO | Dreno Ar 11
7442156 | TÉRREO | Dreno Ar 10
7442158 | TÉRREO | Dreno Ar 10
7442595 | TÉRREO | Dreno Ar 14
7442597 | TÉRREO | Dreno Ar 14
7442645 | TÉRREO | Dreno Ar 13
7442647 | TÉRREO | Dreno Ar 13
7442983 | TÉRREO | Dreno Ar 17
7443071 | TÉRREO | Dreno Ar 17
7443087 | TÉRREO | Dreno Ar 17
7443121 | TÉRREO | Dreno Ar 15
7443163 | TÉRREO | Dreno Ar 15
7443176 | TÉRREO | Dreno Ar 15
7443219 | TÉRREO | Dreno Ar 12
7443251 | TÉRREO | Dreno Ar 12
7443264 | TÉRREO | Dreno Ar 12
7443301 | TÉRREO | Dreno Ar 16
7443335 | TÉRREO | Dreno Ar 16
7443356 | TÉRREO | Dreno Ar 16
7443374 | TÉRREO | Dreno Ar 18
7443376 | TÉRREO | Dreno Ar 18
7443416 | TÉRREO | Dreno Ar 18
7443446 | TÉRREO | Dreno Ar 19
7443448 | TÉRREO | Dreno Ar 19
7443452 | TÉRREO | Dreno Ar 19
7443463 | TÉRREO | Dreno Ar 21
7443465 | TÉRREO | Dreno Ar 21
7443495 | TÉRREO | Dreno Ar 21
7443572 | TÉRREO | Dreno Ar 20
7443574 | TÉRREO | Dreno Ar 20
7443810 | TÉRREO | Dreno Ar 24
7443812 | TÉRREO | Dreno Ar 24
7443842 | TÉRREO | Dreno Ar 26
7443844 | TÉRREO | Dreno Ar 26
7443904 | TÉRREO | Dreno Ar 27
7443943 | TÉRREO | Dreno Ar 27
7443957 | TÉRREO | Dreno Ar 27
7446619 | TÉRREO | Água Fria - Extravasor e Limpeza 1
7446726 | TÉRREO | Água Fria - Extravasor e Limpeza 1
7449609 | TÉRREO | Água Fria - Extravasor e Limpeza 1
7449845 | TÉRREO | Água Fria Alimentação 5
7449884 | TÉRREO | Água Fria Alimentação 5
7449886 | TÉRREO | Água Fria Alimentação 5
7450992 | DRENAGEM PLUVIAL - PLANTA DE COBERTURA | Água Fria - Extravasor e Limpeza 12
7451274 | DRENAGEM PLUVIAL - PLANTA DE COBERTURA | Água Fria - Extravasor e Limpeza 12; Água Fria Alimentação 5
7475026 | TÉRREO | Água Fria - Extravasor e Limpeza 3
7475176 | TÉRREO | Água Fria - Extravasor e Limpeza 3
7475452 | TÉRREO | Água Fria 2
7485759 | TÉRREO | Água Fria - Extravasor e Limpeza 1
7485892 | TÉRREO | Água Fria - Extravasor e Limpeza 1
7485896 | TÉRREO | Água Fria - Extravasor e Limpeza 1
7486587 | DRENAGEM PLUVIAL - PLANTA DE COBERTURA | Água Fria - Extravasor e Limpeza 1
7486705 | TÉRREO | Água Fria 9
7486879 | TÉRREO | Água Fria 1
7486918 | TÉRREO | Água Fria 1
7486926 | TÉRREO | Água Fria 1
7487086 | TÉRREO | Água Fria - Extravasor e Limpeza 1
7487100 | TÉRREO | Água Fria - Extravasor e Limpeza 1
7487423 | TÉRREO | Água Fria - Extravasor e Limpeza 1
7487454 | TÉRREO | Água Fria - Extravasor e Limpeza 1
7487477 | TÉRREO | Água Fria - Extravasor e Limpeza 1
7492595 | TÉRREO | Água Fria 9
7492597 | TÉRREO | Água Fria 9
7501636 | TÉRREO | Água Fria 9
7509247 | TÉRREO | Água Fria - Extravasor e Limpeza 1
7509259 | TÉRREO | Água Fria - Extravasor e Limpeza 1
7509347 | TÉRREO | Água Fria - Extravasor e Limpeza 1

# IfcFlowFitting: PVC Marrom Soldável_Joelho 90° Azul com Bucha de Latão_Rodrigo MEP:Joelho_20x1/2''_ 25x1/2''_ 25x3/4'' _ 32x3/4'' (31)
In: TÉRREO
Type - Material: PVC Azul
Type - Pset_ManufacturerTypeInformation - Manufacturer: Tigre
Pset_DistributionFlowElementCommon - Reference: Joelho_20x1/2''_ 25x1/2''_ 25x3/4'' _ 32x3/4''; sets with these values: 2
Name (PVC Marrom Soldável_Joelho 90° Azul com Bucha de Latão_Rodrigo MEP:Joelho_20x1/2''_ 25x1/2''_ 25x3/4'' _ 32x3/4'':...) | Group
7031441 | Água Fria - Extravasor e Limpeza 1
7034971 | Água Fria - Extravasor e Limpeza 1
7380737 | Água Fria - Extravasor e Limpeza 1
7380818 | Água Fria 1
7380984 | Água Fria 9
7382259 | Água Fria - Extravasor e Limpeza 1
7382351 | Água Fria - Extravasor e Limpeza 1
7382593 | Água Fria - Extravasor e Limpeza 1
7382840 | Água Fria - Extravasor e Limpeza 1
7383206 | Água Fria - Extravasor e Limpeza 1
7383277 | Água Fria - Extravasor e Limpeza 1
7383583 | Água Fria - Extravasor e Limpeza 1
7383636 | Água Fria - Extravasor e Limpeza 1
7383760 | Água Fria 9
7384077 | Água Fria 9
7384294 | Água Fria 9
7384376 | Água Fria 9
7384610 | Água Fria 9
7385016 | Água Fria 1
7385176 | Água Fria 1
7385315 | Água Fria - Extravasor e Limpeza 1
7385403 | Água Fria 1
7385493 | Água Fria - Extravasor e Limpeza 1
7385548 | Água Fria - Extravasor e Limpeza 1
7446434 | Água Fria - Extravasor e Limpeza 1
7446468 | Água Fria - Extravasor e Limpeza 1
7446510 | Água Fria - Extravasor e Limpeza 1
7485719 | Água Fria - Extravasor e Limpeza 1
7485748 | Água Fria - Extravasor e Limpeza 1
7487069 | Água Fria - Extravasor e Limpeza 1
7487102 | Água Fria - Extravasor e Limpeza 1

# IfcFlowFitting: PVC Marrom Soldável_Luva com Bucha de Latão Aninhado_Rodrigo MEP:Luva com bucha de latão_20x1/2''_ 25x1/2''_ 25x3/4'' _ 32x1'' (2)
In: TÉRREO
Type - Material: PVC Azul
Type - Pset_ManufacturerTypeInformation - Manufacturer: Tigre
Pset_DistributionFlowElementCommon - Reference: Luva com bucha de latão_20x1/2''_ 25x1/2''_ 25x3/4'' _ 32x1''; sets with these values: 2
Name (PVC Marrom Soldável_Luva com Bucha de Latão Aninhado_Rodrigo MEP:Luva com bucha de latão_20x1/2''_ 25x1/2''_ 25x3/4'' _ 32x1'':...)
7032076
7385564

# IfcFlowFitting: PVC Marrom Soldável_Tê 90° Azul com Bucha de Latão_Rodrigo MEP:Tê_20x1/2''_ 25x1/2''_ 25x3/4''_ 32x3/4'' (5)
In: TÉRREO
Type - Material: PVC Azul
Type - Pset_ManufacturerTypeInformation - Manufacturer: Tigre
Pset_DistributionFlowElementCommon - Reference: Tê_20x1/2''_ 25x1/2''_ 25x3/4''_ 32x3/4''; sets with these values: 2
Name (PVC Marrom Soldável_Tê 90° Azul com Bucha de Latão_Rodrigo MEP:Tê_20x1/2''_ 25x1/2''_ 25x3/4''_ 32x3/4'':...) | Group
7383281 | Água Fria - Extravasor e Limpeza 1
7383764 | Água Fria 9
7384380 | Água Fria 9
7475044 | Água Fria - Extravasor e Limpeza 3
7487073 | Água Fria - Extravasor e Limpeza 1

# IfcFlowFitting: PVC Marrom Soldável_Tê e Tê de Reducão_Rodrigo MEP:Tê (36)
In: TÉRREO
Type - Material: PVC Marrom
Type - Pset_ManufacturerTypeInformation - Manufacturer: Tigre
Pset_DistributionFlowElementCommon - Reference: Tê; sets with these values: 2
Name (PVC Marrom Soldável_Tê e Tê de Reducão_Rodrigo MEP:Tê:...) | Group
7377744 | Água Fria - Extravasor e Limpeza 1
7377870 | Água Fria - Extravasor e Limpeza 1
7380731 | Água Fria - Extravasor e Limpeza 1
7380812 | Água Fria 1
7380978 | Água Fria 9
7383058 | Água Fria - Extravasor e Limpeza 1
7383525 | Água Fria - Extravasor e Limpeza 1
7384180 | Água Fria 9
7385500 | Água Fria - Extravasor e Limpeza 1
7386614 | Água Fria - Extravasor e Limpeza 1
7386976 | Água Fria - Extravasor e Limpeza 1
7387822 | Água Fria - Extravasor e Limpeza 1
7387883 | Água Fria - Extravasor e Limpeza 1
7388553 | Água Fria 9
7388586 | Água Fria 9
7388802 | Água Fria 1
7388843 | Água Fria - Extravasor e Limpeza 1
7388920 | Água Fria - Extravasor e Limpeza 1
7388966 | Água Fria - Extravasor e Limpeza 1
7389058 | Água Fria - Extravasor e Limpeza 1
7435879 | Água Fria - Extravasor e Limpeza 2
7436557 | Água Fria - Extravasor e Limpeza 2
7440908 | Dreno Ar 2
7446538 | Água Fria - Extravasor e Limpeza 1
7446581 | Água Fria - Extravasor e Limpeza 1
7452818 | Água Fria - Extravasor e Limpeza 1
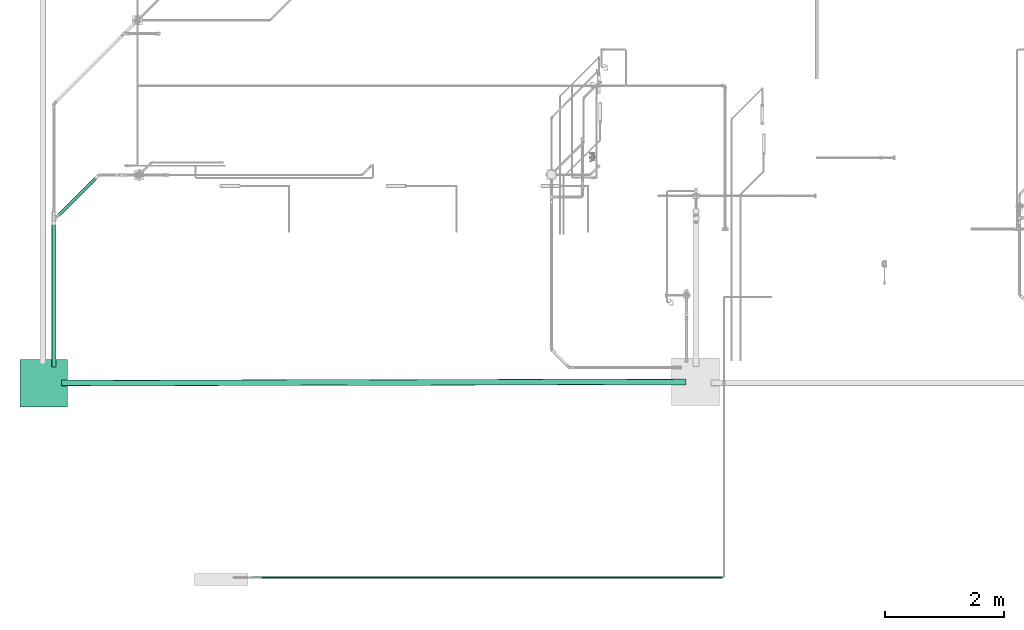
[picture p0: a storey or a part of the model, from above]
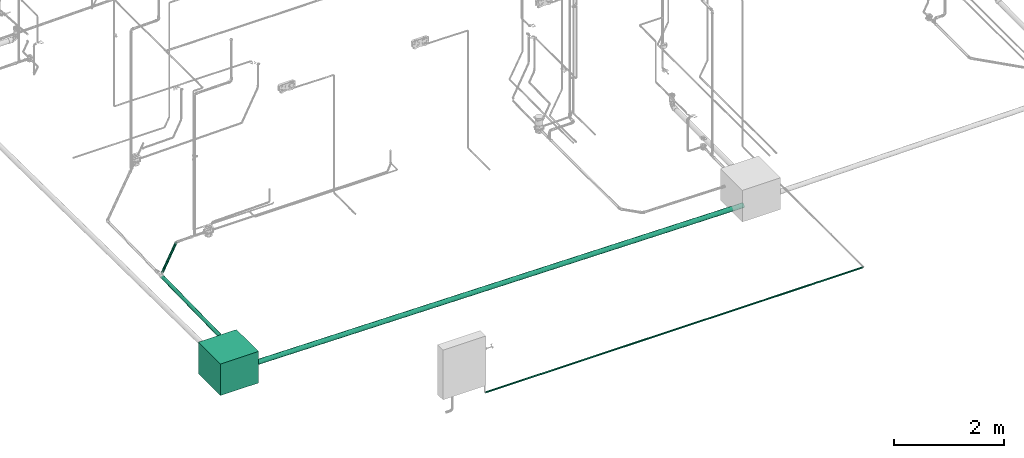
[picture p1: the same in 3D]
Properties of the parts of a building model (IFC2X3), part 4 of 4

# IfcFlowFitting: PVC Marrom Soldável_Tê e Tê de Reducão_Rodrigo MEP:Tê (36)
Name (PVC Marrom Soldável_Tê e Tê de Reducão_Rodrigo MEP:Tê:...) | Group
7486627 | Água Fria 9
7486852 | Água Fria 1
7486914 | Água Fria 1
7487181 | Água Fria - Extravasor e Limpeza 1
7487381 | Água Fria - Extravasor e Limpeza 1
7487405 | Água Fria - Extravasor e Limpeza 1
7487440 | Água Fria - Extravasor e Limpeza 1
7492559 | Água Fria 9
7509194 | Água Fria - Extravasor e Limpeza 1
7509313 | Água Fria - Extravasor e Limpeza 1

# IfcFlowFitting: Torneira de Jardim:Torneira de Jardim, 25mm x Ø3/4'' (4)
In: TÉRREO
Type - Material: <Unnamed>
Type - Pset_ManufacturerTypeInformation - Manufacturer: Deca
Pset_DistributionFlowElementCommon - Reference: Torneira de Jardim, 25mm x Ø3/4''; sets with these values: 2
Name (Torneira de Jardim:Torneira de Jardim, 25mm x Ø3/4'':...) | Group
7383223 | Água Fria - Extravasor e Limpeza 1
7475076 | Água Fria - Extravasor e Limpeza 3
7485721 | Água Fria 3
7485750 | Água Fria 4

# IfcFlowFitting: Tubo de Ligação Inox com anel para vaso sanitário 25cm:Tubo de Ligação Inox com anel para vaso sanitário 25cm (6)
In: TÉRREO
Type - Material: Cromada
Type - Pset_ManufacturerTypeInformation - Manufacturer: Deca
Pset_DistributionFlowElementCommon - Reference: Tubo de Ligação Inox com anel para vaso sanitário 25cm; sets with these values: 2
Name (Tubo de Ligação Inox com anel para vaso sanitário 25cm:Tubo de Ligação Inox com anel para vaso sanitário 25cm:...)
7033643
7380718
7380799
7380965
7385486
7427227

# IfcFlowFitting: Tubo para Válvula de descarga com Joelho azul, Ø38mmx0,8m:Tubo para Válvula de descarga com Joelho azul, Ø38mmx0,8m (6)
In: TÉRREO
Type - Material: PVC Azul, PVC Branco
Type - Pset_ManufacturerTypeInformation - Manufacturer: Tigre
Pset_DistributionFlowElementCommon - Reference: Tubo para Válvula de descarga com Joelho azul, Ø38mmx0,8m; sets with these values: 2
Name (Tubo para Válvula de descarga com Joelho azul, Ø38mmx0,8m:Tubo para Válvula de descarga com Joelho azul, Ø38mmx0,8m:...)
7033641
7380716
7380797
7380963
7385484
7427225

# IfcFlowFitting: Valvula de Descarga com Acabamento:Baixa Pressão - Ø1.1/2'' (50mm) 1,5 a 15mca, Valvula de Descarga com Acabamento:Baixa Pressão - Ø1.1/2'' (50mm) 1,5 a 15mca:7033639
In: TÉRREO
Type - Material: Dourado - Docol, PVC Branco
Type - Pset_ManufacturerTypeInformation - Manufacturer: Docol
Pset_DistributionFlowElementCommon - Reference: Baixa Pressão - Ø1.1/2'' (50mm) 1,5 a 15mca; sets with these values: 2
Group: Água Fria - Extravasor e Limpeza 1

# IfcFlowFitting: Valvula de Descarga com Acabamento:Baixa Pressão - Ø1.1/2'' (50mm) 1,5 a 15mca - PCD (4)
In: TÉRREO
Type - Material: Dourado - Docol, PVC Branco
Type - Pset_ManufacturerTypeInformation - Manufacturer: Docol
Pset_DistributionFlowElementCommon - Reference: Baixa Pressão - Ø1.1/2'' (50mm) 1,5 a 15mca - PCD; sets with these values: 2
Name (Valvula de Descarga com Acabamento:Baixa Pressão - Ø1.1/2'' (50mm) 1,5 a 15mca - PCD:...) | Group
7380714 | Água Fria - Extravasor e Limpeza 1
7380795 | Água Fria 1
7380961 | Água Fria 9
7385482 | Água Fria - Extravasor e Limpeza 1

# IfcFlowFitting: Valvula de Descarga com Acabamento:Baixa Pressão - Ø1.1/2'' (50mm) 1,5 a 15mca 2, Valvula de Descarga com Acabamento:Baixa Pressão - Ø1.1/2'' (50mm) 1,5 a 15mca 2:7427211
In: TÉRREO
Type - Material: Dourado - Docol, PVC Branco
Type - Pset_ManufacturerTypeInformation - Manufacturer: Docol
Pset_DistributionFlowElementCommon - Reference: Baixa Pressão - Ø1.1/2'' (50mm) 1,5 a 15mca 2; sets with these values: 2
Group: Água Fria - Extravasor e Limpeza 1

# IfcFlowSegment: Tipos de tubos:PVC Esgoto Série Normal (262)
In: TÉRREO
Type - Pset_ManufacturerTypeInformation - Manufacturer: Tigre
Pset_DistributionFlowElementCommon - Reference: PVC Esgoto Série Normal; sets with these values: 2
Pset_FlowSegmentDuctSegment - sets with these values: 2
Name (Tipos de tubos:PVC Esgoto Série Normal:...) | Length (mm) | Group
7029509 | 202.431 | Esgoto Primário 7
7029546 | 1020 | Esgoto Primário 8
7029716 | 616.309 | Esgoto Primário 7
7030100 | 1216.72 | Esgoto Primário 10
7030112 | 110.993 | Esgoto Primário 10
7038217 | 288.194 | Esgoto - Ventilação 3
7038227 | 98.3566 | Esgoto Primário 8
7038256 | 4044.27 | Esgoto - Ventilação 3
7306475 | 138.409 | Esgoto Primário 9
7367177 | 1660 | Esgoto Primário 37
7390658 | 640.132 | Esgoto Sanitário 1
7390728 | 2071.37 | Esgoto Sanitário 2
7390743 | 309.468 | Esgoto Sanitário 2
7390759 | 169.541 | Esgoto Sanitário 2
7390870 | 237.351 | Esgoto Sanitário 3
7390881 | 236.745 | Esgoto Sanitário 3
7390895 | 620.975 | Esgoto Sanitário 3
7391026 | 740.041 | Esgoto Sanitário 4
7391035 | 164.648 | Esgoto Sanitário 4
7391049 | 614.28 | Esgoto Sanitário 4
7391071 | 5394.74 | Esgoto Sanitário 6
7391107 | 8310.03 | Esgoto Sanitário 7
7391109 | 107.993 | Esgoto Sanitário 7
7391445 | 145.914 | Esgoto Sanitário 10
7391464 | 25.4 | Esgoto Sanitário 13
7391497 | 51.9407 | Esgoto Sanitário 8
7391506 | 590.42 | Esgoto Sanitário 8
7391516 | 177.853 | Esgoto Sanitário 8
7391530 | 613.83 | Esgoto Sanitário 8
7391560 | 5604.79 | Esgoto Sanitário 11
7391866 | 35.9081 | Esgoto Sanitário 9
7391881 | 177.054 | Esgoto Sanitário 9
7391895 | 626.176 | Esgoto Sanitário 9
7392050 | 628.712 | Esgoto Sanitário 10
7392507 | 490.307 | Esgoto Sanitário 17
7392509 | 83.8622 | Esgoto Sanitário 17
7392584 | 2516.72 | Esgoto Sanitário 18
7392586 | 108.418 | Esgoto Sanitário 18
7393320 | 267.505 | Esgoto Sanitário 20
7393334 | 665.616 | Esgoto Sanitário 20
7397335 | 645.317 | Esgoto Sanitário 24
7397348 | 7917.47 | Esgoto Sanitário 24
7399067 | 1198.01 | Esgoto - Ventilação 4
7399078 | 34.5111 | Esgoto - Ventilação 4
7399081 | 176.399 | Esgoto Sanitário 11
7399108 | 2993.12 | Esgoto - Ventilação 4
7399139 | 358.138 | Esgoto - Ventilação 4
7399157 | 1010.36 | Esgoto - Ventilação 4
7400200 | 1217.3 | Esgoto Sanitário 27
7400434 | 744.661 | Esgoto Sanitário 30
7400447 | 35.9779 | Esgoto Sanitário 30
7400512 | 182.733 | Esgoto Sanitário 30
7400758 | 3253.47 | Esgoto - Ventilação 7
7400762 | 1409.33 | Esgoto Sanitário 27
7400951 | 118.55 | Esgoto Sanitário 27
7400973 | 239.797 | Esgoto - Ventilação 7
7401000 | 828.793 | Esgoto - Ventilação 7
7401178 | 75.8998 | Esgoto Sanitário 27
7401186 | 2391.58 | Esgoto Sanitário 27
7401250 | 645.554 | Esgoto Sanitário 27
7401724 | 144.285 | Esgoto Sanitário 31
7401736 | 3.59999 | Esgoto Sanitário 32
7401868 | 694.901 | Esgoto Sanitário 31
7401988 | 466.606 | Esgoto Sanitário 33
7401996 | 3468.81 | Esgoto Sanitário 33
7402012 | 2944.43 | Esgoto Sanitário 33
7402094 | 224.839 | Esgoto Sanitário 34
7402106 | 25.4 | Esgoto Sanitário 35
7402135 | 631.325 | Esgoto Sanitário 34
7402464 | 3575.25 | Esgoto Sanitário 36
7403006 | 129.246 | Esgoto Sanitário 38
7403023 | 697.104 | Esgoto Sanitário 38
7403063 | 172.655 | Esgoto Sanitário 37
7403072 | 93.091 | Esgoto Sanitário 37
7403084 | 693.914 | Esgoto Sanitário 37
7403128 | 798.952 | Esgoto Sanitário 39
7403137 | 253.072 | Esgoto Sanitário 39
7403151 | 678.253 | Esgoto Sanitário 39
7403475 | 202.431 | Esgoto Sanitário 42
7403477 | 940 | Esgoto Sanitário 44
7403479 | 616.309 | Esgoto Sanitário 42
7403483 | 288.194 | Esgoto - Ventilação 2
7403486 | 98.3566 | Esgoto Sanitário 44
7403497 | 4069.77 | Esgoto - Ventilação 2
7403511 | 138.409 | Esgoto Sanitário 45
7403515 | 2498.28 | Esgoto Sanitário 49
7403517 | 115.978 | Esgoto Sanitário 49
7403986 | 429.729 | Esgoto Sanitário 43
7404000 | 2436.95 | Esgoto Sanitário 43
7404034 | 968.927 | Esgoto Sanitário 43
7404042 | 1684.03 | Esgoto Sanitário 43
7404108 | 4048.18 | Esgoto Sanitário 43
7404314 | 134.509 | Esgoto Sanitário 46
7404326 | 25.4 | Esgoto Sanitário 47
7404457 | 671.795 | Esgoto Sanitário 46
7404531 | 142.674 | Esgoto Sanitário 48
7404540 | 217.881 | Esgoto Sanitário 48
7404554 | 616.25 | Esgoto Sanitário 48
7404861 | 115 | Esgoto Sanitário 50
7405101 | 6240.04 | Esgoto Sanitário 51
7405192 | 1189.63 | Esgoto Sanitário 52
7405201 | 1664.03 | Esgoto Sanitário 52
7405296 | 131.453 | Esgoto Sanitário 53
7405551 | 281.913 | Esgoto Sanitário 53
7405569 | 784.55 | Esgoto Sanitário 53
7405864 | 2524.3 | Esgoto Sanitário 50
7407157 | 2463.48 | Esgoto Sanitário 56
7407217 | 560.135 | Esgoto Sanitário 58
7407233 | 159.641 | Esgoto Sanitário 58
7407245 | 683.499 | Esgoto Sanitário 58
7407275 | 669.045 | Esgoto Sanitário 59
7407291 | 728.984 | Esgoto Sanitário 59
7407301 | 324.03 | Esgoto Sanitário 59
7407313 | 662.996 | Esgoto Sanitário 59
7407343 | 862.697 | Esgoto Sanitário 57
7407352 | 1079.8 | Esgoto Sanitário 57
7407364 | 604.18 | Esgoto Sanitário 57
7408856 | 456.7 | Esgoto Sanitário 64
7408865 | 600.413 | Esgoto Sanitário 64
7408875 | 534.855 | Esgoto Sanitário 64
7408887 | 632.879 | Esgoto Sanitário 64
7408917 | 2131.8 | Esgoto Sanitário 66
7408934 | 1087.88 | Esgoto Sanitário 66
7408946 | 485.529 | Esgoto Sanitário 66
7409279 | 3650.9 | Esgoto Sanitário 65
7409290 | 180.576 | Esgoto Sanitário 65
7409306 | 283.208 | Esgoto Sanitário 65
7409360 | 205.166 | Esgoto Sanitário 68
7409376 | 1146.85 | Esgoto Sanitário 68
7409392 | 257.009 | Esgoto Sanitário 68
7411528 | 10121.7 | Esgoto Sanitário 71
7411687 | 3385 | Esgoto Sanitário 72
7412038 | 278.134 | Esgoto - Ventilação 5
7412045 | 212.925 | Esgoto - Ventilação 5
7412048 | 204.191 | Esgoto Sanitário 33
7412075 | 2838.12 | Esgoto - Ventilação 5
7412163 | 338.137 | Esgoto - Ventilação 5
7412179 | 1000.56 | Esgoto - Ventilação 5
7412315 | 308.186 | Esgoto Sanitário 36
7412444 | 288.716 | Esgoto - Ventilação 10
7412464 | 10.8407 | Esgoto - Ventilação 10
7412471 | 128.749 | Esgoto Sanitário 27
7412493 | 417.885 | Esgoto - Ventilação 10
7412518 | 3048.1 | Esgoto - Ventilação 10
7412688 | 478.144 | Esgoto - Ventilação 10
7412706 | 1169.16 | Esgoto - Ventilação 10
7413010 | 261.202 | Esgoto - Ventilação 11
7413017 | 287.716 | Esgoto - Ventilação 11
7413020 | 169.332 | Esgoto Sanitário 43
7413041 | 457.887 | Esgoto - Ventilação 11
7413063 | 4014.56 | Esgoto - Ventilação 11
7413258 | 158.128 | Esgoto - Ventilação 12
7413269 | 237.369 | Esgoto - Ventilação 12
7413272 | 140.803 | Esgoto Sanitário 43
7413306 | 2898.12 | Esgoto - Ventilação 12
7413454 | 298.135 | Esgoto - Ventilação 12
7413472 | 790.959 | Esgoto - Ventilação 12
7413529 | 158.128 | Esgoto - Ventilação 13
7413536 | 25.8525 | Esgoto - Ventilação 13
7413539 | 109.866 | Esgoto Sanitário 52
7413566 | 3148.12 | Esgoto - Ventilação 13
7413630 | 618.151 | Esgoto - Ventilação 13
7413648 | 727.759 | Esgoto - Ventilação 13
7413799 | 456.624 | Esgoto - Ventilação 14
7413808 | 109.178 | Esgoto - Ventilação 14
7413811 | 264.542 | Esgoto Sanitário 56
7413833 | 103.656 | Esgoto - Ventilação 14
7413859 | 2993.12 | Esgoto - Ventilação 14
7413933 | 743.122 | Esgoto - Ventilação 14
7413951 | 766.509 | Esgoto - Ventilação 14
7414020 | 3068.88 | Esgoto - Ventilação 16
7414024 | 278.958 | Esgoto Sanitário 63
7414209 | 180.171 | Esgoto Sanitário 63
7414225 | 708.165 | Esgoto - Ventilação 16
7414243 | 887.159 | Esgoto - Ventilação 16
7414809 | 162.935 | Esgoto Sanitário 75
7414847 | 239.426 | Esgoto - Ventilação 15
7414856 | 5.14112 | Esgoto - Ventilação 15
7414859 | 67.4899 | Esgoto Sanitário 6
7414880 | 337.881 | Esgoto - Ventilação 15
7414902 | 4062.54 | Esgoto - Ventilação 15
7415421 | 137.321 | Esgoto Sanitário 5
7415459 | 3084.41 | Esgoto - Ventilação 19
7415463 | 480.379 | Esgoto Sanitário 1
7415520 | 138.447 | Esgoto Sanitário 1
7415532 | 678.154 | Esgoto - Ventilação 19
7415548 | 1087.16 | Esgoto - Ventilação 19
7415914 | 186.792 | Esgoto Sanitário 76
7426250 | 161.629 | Esgoto Sanitário 79
7439256 | 98.595 | Água Fria Alimentação 2
7479980 | 2581.7 | Esgoto Sanitário 69
7480440 | 1242.86 | Esgoto Sanitário 85
7488180 | 961.833 | Esgoto - Ventilação 18
7488182 | 276.421 | Esgoto - Ventilação 18
7488192 | 437.886 | Esgoto - Ventilação 18
7488202 | 3970.52 | Esgoto - Ventilação 18
7491131 | 5086.17 | Esgoto Sanitário 16
7491224 | 360.112 | Esgoto Sanitário 15
7491239 | 239.532 | Esgoto Sanitário 15
7491255 | 623.67 | Esgoto Sanitário 15
7491342 | 4154.27 | Esgoto - Ventilação 20
7491366 | 111.565 | Esgoto Sanitário 16
7491603 | 2756.73 | Esgoto Sanitário 11
7491611 | 3680.8 | Esgoto Sanitário 11
7491713 | 216.461 | Esgoto Sanitário 29
7491725 | 25.4 | Esgoto Sanitário 82
7491876 | 580.037 | Esgoto Sanitário 29
7491996 | 758.158 | Esgoto - Ventilação 1
7492005 | 5.56142 | Esgoto - Ventilação 1
7492008 | 146.983 | Esgoto Sanitário 11
7492036 | 3018.12 | Esgoto - Ventilação 1
7492366 | 358.138 | Esgoto - Ventilação 1
7492392 | 750.359 | Esgoto - Ventilação 1
7496682 | 1140 | Esgoto Sanitário 86
7496727 | 230 | Esgoto Sanitário 87
7496800 | 254.4 | Esgoto Sanitário 88
7496843 | 1200 | Esgoto Sanitário 89
7496913 | 740 | Esgoto Sanitário 90
7496960 | 210 | Esgoto Sanitário 91
7497005 | 300 | Esgoto Sanitário 92
7497045 | 740 | Esgoto Sanitário 93
7497146 | 1785 | Esgoto Sanitário 94
7497188 | 1400 | Esgoto Sanitário 95
7502680 | 248.077 | Esgoto Sanitário 60
7502684 | 237.628 | Esgoto Sanitário 84
7502686 | 25.4 | Esgoto Sanitário 98
7502688 | 673.397 | Esgoto Sanitário 84
7502692 | 3149.66 | Esgoto - Ventilação 9
7502695 | 710.98 | Esgoto Sanitário 60
7502706 | 338.137 | Esgoto - Ventilação 9
7502716 | 834.559 | Esgoto - Ventilação 9
7502795 | 391.415 | Esgoto Sanitário 56
7502835 | 1864.03 | Esgoto Sanitário 56
7503520 | 3578.66 | Esgoto Sanitário 17
7503828 | 373.699 | Esgoto Sanitário 17
7503838 | 248.788 | Esgoto Sanitário 17
7503921 | 136.014 | Esgoto Sanitário 17
7504074 | 1698.89 | Esgoto Sanitário 20
7504140 | 364.206 | Esgoto Sanitário 20
7504511 | 3455.12 | Esgoto Sanitário 23
7504557 | 735.9 | Esgoto - Ventilação 6
7504576 | 10.5935 | Esgoto Sanitário 17; Esgoto - Ventilação 6
7504579 | 107.202 | Esgoto Sanitário 17
7504608 | 3057.6 | Esgoto - Ventilação 6
7504865 | 518.146 | Esgoto - Ventilação 6
7504892 | 928.759 | Esgoto - Ventilação 6
7505148 | 2380.13 | Esgoto Sanitário 25
7505196 | 4990.3 | Esgoto Sanitário 11
7505477 | 966.129 | Esgoto Sanitário 63
7505580 | 2415.68 | Esgoto Sanitário 63
7505734 | 1779.53 | Esgoto Sanitário 63
7506462 | 3037.12 | Esgoto Sanitário 63; Esgoto - Ventilação 17
7506486 | 1568.56 | Esgoto Sanitário 63
7506664 | 207.166 | Esgoto Sanitário 63
7506676 | 516.496 | Esgoto - Ventilação 17
7506705 | 1003.21 | Esgoto - Ventilação 17
7506964 | 10487.9 | Esgoto Sanitário 19
7507308 | 5540 | Esgoto Sanitário 40
7507472 | 2913.24 | Esgoto Sanitário 69
7507617 | 13420.7 | Esgoto Sanitário 81
7508052 | 7640.41 | Esgoto Sanitário 21
7508131 | 2940.11 | Esgoto Sanitário 22

# IfcFlowSegment: Tipos de tubos:PVC Esgoto Série Reforçada (61)
In: DRENAGEM PLUVIAL - PLANTA DE COBERTURA
Type - Pset_ManufacturerTypeInformation - Manufacturer: Tigre
Pset_DistributionFlowElementCommon - Reference: PVC Esgoto Série Reforçada; sets with these values: 2
Pset_FlowSegmentDuctSegment - sets with these values: 2
Name (Tipos de tubos:PVC Esgoto Série Reforçada:...) | Length (mm) | Group
7191995 | 260.65 | Água Pluvial 1
7192022 | 276.3 | Água Pluvial 1
7192041 | 2881.3 | Água Pluvial 1
7417941 | 246.238 | Água Pluvial 2
7417943 | 1481.37 | Água Pluvial 2
7417947 | 2885.8 | Água Pluvial 2
7417951 | 15.65 | Água Pluvial 2
7418822 | 275.638 | Água Pluvial 3
7418824 | 1541.38 | Água Pluvial 3
7418826 | 2845.8 | Água Pluvial 3
7418828 | 15.65 | Água Pluvial 3
7419044 | 250.65 | Água Pluvial 4
7419046 | 211.3 | Água Pluvial 4
7419050 | 2911.3 | Água Pluvial 4
7419068 | 210.65 | Água Pluvial 5
7419070 | 231.3 | Água Pluvial 5
7419074 | 2921.3 | Água Pluvial 5
7419108 | 195.549 | Água Pluvial 6
7419110 | 266.075 | Água Pluvial 6
7419114 | 2922.29 | Água Pluvial 6
7419269 | 1361.83 | Água Pluvial 6
7419507 | 256.448 | Água Pluvial 7
7419509 | 266.075 | Água Pluvial 7
7419511 | 2895.78 | Água Pluvial 7
7419519 | 1392.74 | Água Pluvial 7
7420571 | 210.65 | Água Pluvial 15
7420573 | 158.979 | Água Pluvial 15
7420823 | 266.791 | Água Pluvial 15
7421055 | 2650.49 | Água Pluvial 15
7421404 | 210.65 | Água Pluvial 17
7421406 | 158.979 | Água Pluvial 17
7421410 | 266.791 | Água Pluvial 17
7421414 | 2660.49 | Água Pluvial 17
7422312 | 2923.99 | Água Pluvial 18
7422314 | 1861.36 | Água Pluvial 18
7422316 | 2844.8 | Água Pluvial 18
7422318 | 15.65 | Água Pluvial 18
7510374 | 210.65 | Água Pluvial 8
7510376 | 271.3 | Água Pluvial 8
7510380 | 2921.3 | Água Pluvial 8
7510389 | 210.65 | Água Pluvial 10
7510391 | 266.3 | Água Pluvial 10
7510395 | 2921.3 | Água Pluvial 10
7510404 | 210.65 | Água Pluvial 12
7510406 | 231.3 | Água Pluvial 12
7510410 | 2921.3 | Água Pluvial 12
7510419 | 210.65 | Água Pluvial 14
7510421 | 231.3 | Água Pluvial 14
7510425 | 2921.3 | Água Pluvial 14
7510434 | 210.65 | Água Pluvial 19
7510436 | 271.3 | Água Pluvial 19
7510440 | 2921.3 | Água Pluvial 19
7510449 | 210.65 | Água Pluvial 21
7510451 | 231.3 | Água Pluvial 21
7510455 | 2921.3 | Água Pluvial 21
7510464 | 210.65 | Água Pluvial 23
7510466 | 231.3 | Água Pluvial 23
7510470 | 2921.3 | Água Pluvial 23
7510479 | 210.65 | Água Pluvial 25
7510481 | 271.3 | Água Pluvial 25
7510485 | 2921.3 | Água Pluvial 25

# IfcFlowSegment: Tipos de tubos:PVC Marrom Soldável (313)
Type - Pset_ManufacturerTypeInformation - Manufacturer: Tigre
Pset_DistributionFlowElementCommon - Reference: PVC Marrom Soldável; sets with these values: 2
Pset_FlowSegmentDuctSegment - sets with these values: 2
Name (Tipos de tubos:PVC Marrom Soldável:...) | In | Length (mm) | Group
7031418 | TÉRREO | 434.01 | Água Fria - Extravasor e Limpeza 1
7031445 | TÉRREO | 423.112 | Água Fria - Extravasor e Limpeza 1
7031871 | TÉRREO | 1006.02 | Água Fria - Extravasor e Limpeza 1
7032081 | TÉRREO | 847.2 | Água Fria - Extravasor e Limpeza 1
7033181 | TÉRREO | 345.9 | Água Fria - Extravasor e Limpeza 1
7033652 | TÉRREO | 445.9 | Água Fria - Extravasor e Limpeza 1
7035195 | TÉRREO | 768.3 | Água Fria - Extravasor e Limpeza 1
7377732 | TÉRREO | 743.504 | Água Fria - Extravasor e Limpeza 1
7377745 | TÉRREO | 211.696 | Água Fria - Extravasor e Limpeza 1
7377862 | TÉRREO | 518.136 | Água Fria - Extravasor e Limpeza 1
7377871 | TÉRREO | 234.8 | Água Fria - Extravasor e Limpeza 1
7380727 | TÉRREO | 645.9 | Água Fria - Extravasor e Limpeza 1
7380729 | TÉRREO | 424.629 | Água Fria - Extravasor e Limpeza 1
7380732 | TÉRREO | 511.696 | Água Fria - Extravasor e Limpeza 1
7380735 | TÉRREO | 1020.88 | Água Fria - Extravasor e Limpeza 1
7380739 | TÉRREO | 565.2 | Água Fria - Extravasor e Limpeza 1
7380741 | TÉRREO | 868 | Água Fria - Extravasor e Limpeza 1
7380808 | TÉRREO | 645.9 | Água Fria 1
7380810 | TÉRREO | 419.629 | Água Fria 1
7380813 | TÉRREO | 511.696 | Água Fria 1
7380816 | TÉRREO | 1244.19 | Água Fria 1
7380820 | TÉRREO | 570.2 | Água Fria 1
7380822 | TÉRREO | 868 | Água Fria 1
7380974 | TÉRREO | 645.9 | Água Fria 9
7380976 | TÉRREO | 435.8 | Água Fria 9
7380979 | TÉRREO | 511.696 | Água Fria 9
7380982 | TÉRREO | 39.2467 | Água Fria 9
7380986 | TÉRREO | 565.2 | Água Fria 9
7380988 | TÉRREO | 868 | Água Fria 9
7382245 | TÉRREO | 1768.3 | Água Fria - Extravasor e Limpeza 1
7382432 | TÉRREO | 1563.7 | Água Fria - Extravasor e Limpeza 1
7382600 | TÉRREO | 1563.7 | Água Fria - Extravasor e Limpeza 1
7382826 | TÉRREO | 754.6 | Água Fria - Extravasor e Limpeza 1
7382987 | TÉRREO | 914.1 | Água Fria - Extravasor e Limpeza 1
7383050 | TÉRREO | 1330.1 | Água Fria - Extravasor e Limpeza 1
7383059 | TÉRREO | 617.8 | Água Fria - Extravasor e Limpeza 1
7383078 | TÉRREO | 554.883 | Água Fria - Extravasor e Limpeza 1
7383169 | TÉRREO | 619.3 | Água Fria - Extravasor e Limpeza 1
7383275 | TÉRREO | 841.556 | Água Fria - Extravasor e Limpeza 1
7383283 | TÉRREO | 380.322 | Água Fria - Extravasor e Limpeza 1
7383292 | TÉRREO | 1169.2 | Água Fria - Extravasor e Limpeza 1
7383542 | TÉRREO | 1217.79 | Água Fria - Extravasor e Limpeza 1
7383590 | TÉRREO | 1563.7 | Água Fria - Extravasor e Limpeza 1
7383634 | TÉRREO | 764.6 | Água Fria - Extravasor e Limpeza 1
7383643 | TÉRREO | 1563.7 | Água Fria - Extravasor e Limpeza 1
7383758 | TÉRREO | 1575.61 | Água Fria 9
7383766 | TÉRREO | 1240.17 | Água Fria 9
7383768 | TÉRREO | 734.6 | Água Fria 9
7383775 | TÉRREO | 1564.6 | Água Fria 9
7383818 | TÉRREO | 1569.45 | Água Fria 9
7383927 | TÉRREO | 1434.6 | Água Fria 9
7384061 | TÉRREO | 1145.8 | Água Fria 9
7384169 | TÉRREO | 179.884 | Água Fria 9
7384181 | TÉRREO | 468.3 | Água Fria 9
7384184 | TÉRREO | 2954.6 | Água Fria 9
7384192 | TÉRREO | 197.694 | Água Fria 9
7384374 | TÉRREO | 1178.83 | Água Fria 9
7384382 | TÉRREO | 312.668 | Água Fria 9
7384384 | TÉRREO | 714.599 | Água Fria 9
7384391 | TÉRREO | 1584.6 | Água Fria 9
7384607 | TÉRREO | 270.435 | Água Fria 9
7384636 | TÉRREO | 734.6 | Água Fria 9
7384799 | TÉRREO | 1564.6 | Água Fria 9
7385014 | TÉRREO | 759.6 | Água Fria 1
7385023 | TÉRREO | 1563.7 | Água Fria 1
7385174 | TÉRREO | 270.435 | Água Fria 1
7385178 | TÉRREO | 759.6 | Água Fria 1
7385187 | TÉRREO | 1564.6 | Água Fria 1
7385302 | TÉRREO | 496.943 | Água Fria - Extravasor e Limpeza 1
7385304 | TÉRREO | 764.6 | Água Fria - Extravasor e Limpeza 1
7385311 | TÉRREO | 1564.6 | Água Fria - Extravasor e Limpeza 1
7385389 | TÉRREO | 759.6 | Água Fria 1
7385495 | TÉRREO | 568.3 | Água Fria - Extravasor e Limpeza 1
7385498 | TÉRREO | 629.228 | Água Fria - Extravasor e Limpeza 1
7385501 | TÉRREO | 211.696 | Água Fria - Extravasor e Limpeza 1
7385546 | TÉRREO | 134.01 | Água Fria - Extravasor e Limpeza 1
7385549 | TÉRREO | 155.617 | Água Fria - Extravasor e Limpeza 1
7385560 | TÉRREO | 1433.01 | Água Fria - Extravasor e Limpeza 1
7385567 | TÉRREO | 1147.2 | Água Fria - Extravasor e Limpeza 1
7385954 | TÉRREO | 1210.17 | Água Fria - Extravasor e Limpeza 1
7386010 | TÉRREO | 744.4 | Água Fria 1
7386044 | TÉRREO | 749.4 | Água Fria - Extravasor e Limpeza 1
7386144 | DRENAGEM PLUVIAL - PLANTA DE COBERTURA | 120.625 | Água Fria 1
7386152 | DRENAGEM PLUVIAL - PLANTA DE COBERTURA | 667.12 | Água Fria 1
7386232 | DRENAGEM PLUVIAL - PLANTA DE COBERTURA | 385 | Água Fria - Extravasor e Limpeza 1
7386320 | TÉRREO | 50.438 | Água Fria - Extravasor e Limpeza 1
7386331 | TÉRREO | 521.163 | Água Fria 1
7386461 | TÉRREO | 1850.9 | Água Fria - Extravasor e Limpeza 1
7386471 | TÉRREO | 1202.1 | Água Fria - Extravasor e Limpeza 1
7386486 | TÉRREO | 710.15 | Água Fria - Extravasor e Limpeza 1
7386565 | TÉRREO | 3677.16 | Água Fria - Extravasor e Limpeza 1
7386604 | TÉRREO | 2471.77 | Água Fria - Extravasor e Limpeza 1
7386615 | TÉRREO | 129.187 | Água Fria - Extravasor e Limpeza 1
7386620 | TÉRREO | 627.407 | Água Fria - Extravasor e Limpeza 1
7386636 | TÉRREO | 719.4 | Água Fria - Extravasor e Limpeza 1
7386789 | DRENAGEM PLUVIAL - PLANTA DE COBERTURA | 188.112 | Água Fria - Extravasor e Limpeza 1
7386798 | DRENAGEM PLUVIAL - PLANTA DE COBERTURA | 655 | Água Fria - Extravasor e Limpeza 1
7386968 | TÉRREO | 1209.94 | Água Fria - Extravasor e Limpeza 1
7386977 | TÉRREO | 722.944 | Água Fria - Extravasor e Limpeza 1
7386985 | TÉRREO | 398.642 | Água Fria - Extravasor e Limpeza 1
7387007 | TÉRREO | 764.6 | Água Fria - Extravasor e Limpeza 1
7387144 | TÉRREO | 1260.16 | Água Fria 1
7387386 | TÉRREO | 1730.19 | Água Fria 1
7387515 | TÉRREO | 1144.92 | Água Fria - Extravasor e Limpeza 1
7387569 | TÉRREO | 6324.04 | Água Fria - Extravasor e Limpeza 1
7387592 | TÉRREO | 764.6 | Água Fria - Extravasor e Limpeza 1
7387812 | TÉRREO | 4.5725 | Água Fria - Extravasor e Limpeza 1
7387830 | TÉRREO | 857.885 | Água Fria - Extravasor e Limpeza 1
7387844 | TÉRREO | 734.6 | Água Fria - Extravasor e Limpeza 1
7387875 | TÉRREO | 23.4 | Água Fria - Extravasor e Limpeza 1
7387884 | TÉRREO | 2275.66 | Água Fria - Extravasor e Limpeza 1
7387891 | TÉRREO | 1674.69 | Água Fria - Extravasor e Limpeza 1
7387900 | TÉRREO | 454.062 | Água Fria - Extravasor e Limpeza 1
7388152 | TÉRREO | 7252.89 | Água Fria 9
7388208 | TÉRREO | 1840.7 | Água Fria 9
7388444 | TÉRREO | 171.823 | Água Fria 9
7388538 | TÉRREO | 1507.21 | Água Fria 9
7388554 | TÉRREO | 861.137 | Água Fria 9
7388561 | TÉRREO | 379.084 | Água Fria 9
7388578 | TÉRREO | 569.53 | Água Fria 9
7388594 | TÉRREO | 375.454 | Água Fria 9
7388662 | DRENAGEM PLUVIAL - PLANTA DE COBERTURA | 87.8317 | Água Fria 9
7388670 | DRENAGEM PLUVIAL - PLANTA DE COBERTURA | 692.12 | Água Fria 9
7388680 | DRENAGEM PLUVIAL - PLANTA DE COBERTURA | 361.704 | Água Fria 9
7388738 | TÉRREO | 516.163 | Água Fria 9
7388749 | TÉRREO | 719.4 | Água Fria 9
7388794 | TÉRREO | 348.448 | Água Fria 1
7388803 | TÉRREO | 748.187 | Água Fria 1
7388810 | TÉRREO | 222.815 | Água Fria 1
7388835 | TÉRREO | 1842.6 | Água Fria - Extravasor e Limpeza 1
7388869 | TÉRREO | 289.408 | Água Fria - Extravasor e Limpeza 1
7388958 | TÉRREO | 4.9 | Água Fria - Extravasor e Limpeza 1
7388967 | TÉRREO | 1505.83 | Água Fria - Extravasor e Limpeza 1
7388989 | TÉRREO | 489.813 | Água Fria - Extravasor e Limpeza 1
7389001 | TÉRREO | 734.6 | Água Fria - Extravasor e Limpeza 1
7389069 | TÉRREO | 9.15 | Água Fria - Extravasor e Limpeza 1
7389081 | TÉRREO | 4398.4 | Água Fria - Extravasor e Limpeza 1
7389240 | DRENAGEM PLUVIAL - PLANTA DE COBERTURA | 93.7052 | Água Fria - Extravasor e Limpeza 2
7389512 | DRENAGEM PLUVIAL - PLANTA DE COBERTURA | 34.3234 | Água Fria - Extravasor e Limpeza 2
7389688 | TÉRREO | 740.15 | Água Fria - Extravasor e Limpeza 1
7416094 | TÉRREO | 559.228 | Água Fria - Extravasor e Limpeza 1
7417019 | TÉRREO | 1074.75 | Água Fria 9
7424489 | TÉRREO | 235.877 | Dreno Ar 3
7424493 | TÉRREO | 2580.59 | Dreno Ar 3
7424495 | TÉRREO | 275.975 | Dreno Ar 3
7427189 | TÉRREO | 511.696 | Água Fria - Extravasor e Limpeza 1
7429220 | TÉRREO | 945.9 | Água Fria - Extravasor e Limpeza 1
7432432 | TÉRREO | 1563.7 | Água Fria 1
7432856 | TÉRREO | 3204.1 | Água Fria Alimentação 5
7434857 | DRENAGEM PLUVIAL - PLANTA DE COBERTURA | 140.237 | Água Fria - Extravasor e Limpeza 1
7435001 | DRENAGEM PLUVIAL - PLANTA DE COBERTURA | 120.318 | Água Fria - Extravasor e Limpeza 1
7435405 | DRENAGEM PLUVIAL - PLANTA DE COBERTURA | 114.765 | Água Fria 9
7435463 | DRENAGEM PLUVIAL - PLANTA DE COBERTURA | 107.325 | Água Fria 1
7435984 | DRENAGEM PLUVIAL - PLANTA DE COBERTURA | 360.5 | Água Fria - Extravasor e Limpeza 2
7435992 | DRENAGEM PLUVIAL - PLANTA DE COBERTURA | 751 | Água Fria - Extravasor e Limpeza 2
7436002 | DRENAGEM PLUVIAL - PLANTA DE COBERTURA | 519.295 | Água Fria - Extravasor e Limpeza 2
7436305 | TÉRREO | 559.753 | Água Fria - Extravasor e Limpeza 2
7436348 | TÉRREO | 836 | Água Fria - Extravasor e Limpeza 2
7436386 | TÉRREO | 2023.75 | Água Fria - Extravasor e Limpeza 2
7436558 | DRENAGEM PLUVIAL - PLANTA DE COBERTURA | 597.6 | Água Fria - Extravasor e Limpeza 2
7436766 | TÉRREO | 180.96 | Água Fria - Extravasor e Limpeza 2
7436959 | DRENAGEM PLUVIAL - PLANTA DE COBERTURA | 310.367 | Água Fria - Extravasor e Limpeza 2
7436973 | DRENAGEM PLUVIAL - PLANTA DE COBERTURA | 244.47 | Água Fria - Extravasor e Limpeza 2
7436993 | TÉRREO | 1052.92 | Água Fria - Extravasor e Limpeza 2
7439104 | TÉRREO | 804.3 | Água Fria Alimentação 5
7440522 | TÉRREO | 275.885 | Dreno Ar 2
7440526 | TÉRREO | 2687.9 | Dreno Ar 2
7440528 | TÉRREO | 175.98 | Dreno Ar 2
7440648 | TÉRREO | 250.672 | Dreno Ar 2
7440652 | TÉRREO | 2581.79 | Dreno Ar 2
7440654 | TÉRREO | 95.984 | Dreno Ar 2
7440699 | TÉRREO | 1425.41 | Dreno Ar 2
7440712 | TÉRREO | 2984.6 | Dreno Ar 2
7440906 | TÉRREO | 77.4112 | Dreno Ar 2
7440909 | TÉRREO | 815.561 | Dreno Ar 2
7440953 | TÉRREO | 1332.48 | Dreno Ar 3
7440990 | TÉRREO | 765.713 | Dreno Ar 4
7440994 | TÉRREO | 2583.09 | Dreno Ar 4
7440996 | TÉRREO | 877.005 | Dreno Ar 4
7441155 | TÉRREO | 507.803 | Dreno Ar 6
7441159 | TÉRREO | 2580.59 | Dreno Ar 6
7441161 | TÉRREO | 95.984 | Dreno Ar 6
7441206 | TÉRREO | 2532.48 | Dreno Ar 6
7441453 | TÉRREO | 1029.91 | Dreno Ar 5
7441457 | TÉRREO | 2581.89 | Dreno Ar 5
7441459 | TÉRREO | 877.005 | Dreno Ar 5
7441478 | TÉRREO | 1365.86 | Dreno Ar 7
7441482 | TÉRREO | 2581.89 | Dreno Ar 7
7441484 | TÉRREO | 877.005 | Dreno Ar 7
7441511 | TÉRREO | 744.6 | Dreno Ar 8
7441515 | TÉRREO | 2583.09 | Dreno Ar 8
7441517 | TÉRREO | 877.005 | Dreno Ar 8
7441659 | TÉRREO | 2712.94 | Dreno Ar 5
7441713 | TÉRREO | 1627.79 | Dreno Ar 9
7441717 | TÉRREO | 2575.26 | Dreno Ar 9
7441719 | TÉRREO | 628.765 | Dreno Ar 9
7441725 | TÉRREO | 2252.05 | Dreno Ar 9
7442001 | TÉRREO | 2561 | Dreno Ar 11
7442005 | TÉRREO | 2580.69 | Dreno Ar 11
7442007 | TÉRREO | 266.097 | Dreno Ar 11
7442148 | TÉRREO | 744.6 | Dreno Ar 10
7442152 | TÉRREO | 2589.41 | Dreno Ar 10
7442154 | TÉRREO | 245.335 | Dreno Ar 10
7442587 | TÉRREO | 764.6 | Dreno Ar 14
7442591 | TÉRREO | 2577.31 | Dreno Ar 14
7442593 | TÉRREO | 723.18 | Dreno Ar 14
7442637 | TÉRREO | 764.6 | Dreno Ar 13
7442641 | TÉRREO | 2575.95 | Dreno Ar 13
7442643 | TÉRREO | 859.091 | Dreno Ar 13
7442975 | TÉRREO | 530.946 | Dreno Ar 17
7442979 | TÉRREO | 2580.69 | Dreno Ar 17
7442981 | TÉRREO | 266.097 | Dreno Ar 17
7443077 | TÉRREO | 2780.01 | Dreno Ar 17
7443113 | TÉRREO | 576.335 | Dreno Ar 15
7443117 | TÉRREO | 2580.69 | Dreno Ar 15
7443119 | TÉRREO | 106.105 | Dreno Ar 15
7443168 | TÉRREO | 2680.36 | Dreno Ar 15
7443211 | TÉRREO | 536.335 | Dreno Ar 12
7443215 | TÉRREO | 2450.69 | Dreno Ar 12
7443217 | TÉRREO | 266.097 | Dreno Ar 12
7443256 | TÉRREO | 1316.64 | Dreno Ar 12
7443293 | TÉRREO | 793.493 | Dreno Ar 16
7443297 | TÉRREO | 2580.69 | Dreno Ar 16
7443299 | TÉRREO | 266.097 | Dreno Ar 16
7443348 | TÉRREO | 3668.74 | Dreno Ar 16
7443366 | TÉRREO | 708.898 | Dreno Ar 18
7443370 | TÉRREO | 2580.69 | Dreno Ar 18
7443372 | TÉRREO | 266.097 | Dreno Ar 18
7443408 | TÉRREO | 4048.56 | Dreno Ar 18
7443438 | TÉRREO | 848.131 | Dreno Ar 19
7443442 | TÉRREO | 2580.69 | Dreno Ar 19
7443444 | TÉRREO | 266.097 | Dreno Ar 19
7443450 | TÉRREO | 954.921 | Dreno Ar 19
7443455 | TÉRREO | 899.565 | Dreno Ar 21
7443459 | TÉRREO | 2580.69 | Dreno Ar 21
7443461 | TÉRREO | 266.097 | Dreno Ar 21
7443487 | TÉRREO | 2312.94 | Dreno Ar 21
7443564 | TÉRREO | 764.6 | Dreno Ar 20
7443568 | TÉRREO | 2580.18 | Dreno Ar 20
7443570 | TÉRREO | 437.141 | Dreno Ar 20
7443802 | TÉRREO | 764.6 | Dreno Ar 24
7443806 | TÉRREO | 2576.26 | Dreno Ar 24
7443808 | TÉRREO | 828.624 | Dreno Ar 24
7443834 | TÉRREO | 764.6 | Dreno Ar 26
7443838 | TÉRREO | 2576.45 | Dreno Ar 26
7443840 | TÉRREO | 809.445 | Dreno Ar 26
7443896 | TÉRREO | 315.88 | Dreno Ar 27
7443900 | TÉRREO | 2501.04 | Dreno Ar 27
7443902 | TÉRREO | 961.658 | Dreno Ar 27
7443949 | TÉRREO | 1907.83 | Dreno Ar 27
7446417 | TÉRREO | 734.6 | Água Fria - Extravasor e Limpeza 1
7446454 | TÉRREO | 269.2 | Água Fria - Extravasor e Limpeza 1
7446472 | TÉRREO | 389.6 | Água Fria - Extravasor e Limpeza 1
7446496 | TÉRREO | 268.3 | Água Fria - Extravasor e Limpeza 1
7446514 | TÉRREO | 366.795 | Água Fria - Extravasor e Limpeza 1
7446582 | TÉRREO | 267.8 | Água Fria - Extravasor e Limpeza 1
7447296 | TÉRREO | 864.1 | Água Fria - Extravasor e Limpeza 1
7449294 | TÉRREO | 450.688 | Água Fria - Extravasor e Limpeza 1
7449590 | TÉRREO | 3219.2 | Água Fria - Extravasor e Limpeza 1
7449835 | TÉRREO | 753.606 | Água Fria Alimentação 5
7449849 | TÉRREO | 293.435 | Água Fria Alimentação 5
7450968 | DRENAGEM PLUVIAL - PLANTA DE COBERTURA | 172.165 | Água Fria - Extravasor e Limpeza 12
7450976 | DRENAGEM PLUVIAL - PLANTA DE COBERTURA | 794.2 | Água Fria - Extravasor e Limpeza 12
7451251 | DRENAGEM PLUVIAL - PLANTA DE COBERTURA | 2047.98 | Água Fria Alimentação 5
7452802 | TÉRREO | 9.6 | Água Fria - Extravasor e Limpeza 1
7452819 | TÉRREO | 1093.25 | Água Fria - Extravasor e Limpeza 1
7452826 | TÉRREO | 1534 | Água Fria - Extravasor e Limpeza 1
7474995 | TÉRREO | 283.6 | Água Fria - Extravasor e Limpeza 3
7475010 | TÉRREO | 932.276 | Água Fria - Extravasor e Limpeza 3
7475020 | TÉRREO | 7907.72 | Água Fria - Extravasor e Limpeza 3
7475143 | TÉRREO | 4363 | Água Fria Alimentação 5; Água Fria - Extravasor e Limpeza 3
7475438 | TÉRREO | 320.1 | Água Fria - Extravasor e Limpeza 1
7475475 | TÉRREO | 451.188 | Água Fria - Extravasor e Limpeza 1
7477108 | TÉRREO | 1246.94 | Água Fria 1
7485717 | TÉRREO | 714.6 | Água Fria - Extravasor e Limpeza 1
7485728 | TÉRREO | 464.7 | Água Fria - Extravasor e Limpeza 1
7485746 | TÉRREO | 714.6 | Água Fria - Extravasor e Limpeza 1
7485757 | TÉRREO | 464.7 | Água Fria - Extravasor e Limpeza 1
7486484 | TÉRREO | 8501.98 | Água Fria - Extravasor e Limpeza 1
7486613 | TÉRREO | 2352.31 | Água Fria 9
7486628 | DRENAGEM PLUVIAL - PLANTA DE COBERTURA | 1553.84 | Água Fria 9
7486633 | TÉRREO | 1576.64 | Água Fria 9
7486863 | TÉRREO | 2587.79 | Água Fria 1
7486915 | TÉRREO | 2676.48 | Água Fria 1
7487067 | TÉRREO | 1363.92 | Água Fria - Extravasor e Limpeza 1
7487075 | TÉRREO | 917.311 | Água Fria - Extravasor e Limpeza 1
7487077 | TÉRREO | 765.5 | Água Fria - Extravasor e Limpeza 1
7487084 | TÉRREO | 1564.6 | Água Fria - Extravasor e Limpeza 1
7487089 | TÉRREO | 1311.11 | Água Fria - Extravasor e Limpeza 1
7487091 | TÉRREO | 764.6 | Água Fria - Extravasor e Limpeza 1
7487098 | TÉRREO | 1564.6 | Água Fria - Extravasor e Limpeza 1
7487106 | TÉRREO | 21.6 | Água Fria - Extravasor e Limpeza 1
7487167 | TÉRREO | 7.5 | Água Fria - Extravasor e Limpeza 1
7487182 | TÉRREO | 1851.95 | Água Fria - Extravasor e Limpeza 1
7487189 | TÉRREO | 740.236 | Água Fria - Extravasor e Limpeza 1
7487366 | TÉRREO | 388.277 | Água Fria - Extravasor e Limpeza 1
7487382 | TÉRREO | 4154.91 | Água Fria - Extravasor e Limpeza 1
7487432 | TÉRREO | 913.318 | Água Fria - Extravasor e Limpeza 1
7487446 | TÉRREO | 3113.79 | Água Fria - Extravasor e Limpeza 1
7487987 | DRENAGEM PLUVIAL - PLANTA DE COBERTURA | 193.283 | Água Fria - Extravasor e Limpeza 1
7487997 | DRENAGEM PLUVIAL - PLANTA DE COBERTURA | 625 | Água Fria - Extravasor e Limpeza 1
7488007 | DRENAGEM PLUVIAL - PLANTA DE COBERTURA | 4183.24 | Água Fria - Extravasor e Limpeza 1
7488134 | DRENAGEM PLUVIAL - PLANTA DE COBERTURA | 153.012 | Água Fria - Extravasor e Limpeza 1
7492571 | TÉRREO | 1305.11 | Água Fria 9
7493210 | DRENAGEM PLUVIAL - PLANTA DE COBERTURA | 625 | Água Fria - Extravasor e Limpeza 1
7493225 | DRENAGEM PLUVIAL - PLANTA DE COBERTURA | 3520.63 | Água Fria - Extravasor e Limpeza 1
7501685 | TÉRREO | 2.9 | Água Fria - Extravasor e Limpeza 1
7501697 | TÉRREO | 656.667 | Água Fria - Extravasor e Limpeza 1
7501934 | TÉRREO | 2.9 | Água Fria - Extravasor e Limpeza 1
7501944 | TÉRREO | 2731.81 | Água Fria - Extravasor e Limpeza 1
7509233 | TÉRREO | 769.2 | Água Fria - Extravasor e Limpeza 1
7509251 | TÉRREO | 7774.2 | Água Fria - Extravasor e Limpeza 1
7509324 | TÉRREO | 6031.42 | Água Fria - Extravasor e Limpeza 1

# IfcFlowTerminal: Caixa dagua de polietileno - Fortlev - AleBim:2000 L (2)
In: DRENAGEM PLUVIAL - PLANTA DE COBERTURA
Type - Material: PEMD Azul
Type - Pset_ManufacturerTypeInformation - Manufacturer: FortLev
Pset_DistributionFlowElementCommon - Reference: 2000 L; sets with these values: 2
Name (Caixa dagua de polietileno - Fortlev - AleBim:2000 L:...) | Group
7132676 | Água Fria - Extravasor e Limpeza 1; Água Fria - Extravasor e Limpeza 2; Água Fria Alimentação 1; Água Fria Alimentação 3
7133905 | Água Fria - Extravasor e Limpeza 2; Água Fria 9; Água Fria 1; Água Fria - Extravasor e Limpeza 12; Água Fria Alimentação 4

# IfcFlowTerminal: Caixa de Gordura em Alvenaria_Rodrigo MEP:60x60cm - CG, Caixa de Gordura em Alvenaria_Rodrigo MEP:60x60cm - CG:7397422
In: TÉRREO
Type - Material: Tijolo, Comum, .CONCRETO
Type - Pset_ManufacturerTypeInformation - Manufacturer: -
Pset_DistributionFlowElementCommon - Reference: 60x60cm - CG; sets with these values: 2
Group: Esgoto Sanitário 25

# IfcFlowTerminal: Caixa de Pre Instalação Split:Caixa de Pré-Instalação Split (24)
In: TÉRREO
Type - Material: PEAD
Pset_DistributionFlowElementCommon - Reference: Caixa de Pré-Instalação Split; sets with these values: 2
Name (Caixa de Pre Instalação Split:Caixa de Pré-Instalação Split:...)
7424440
7440521
7440630
7440989
7441154
7441452
7441477
7441510
7441712
7441975
7442147
7442586
7442636
7442705
7443112
7443210
7443292
7443365
7443437
7443454
7443563
7443798
7443830
7443895

# IfcFlowTerminal: Caixa em Alvenaria_Rodrigo MEP:Caixa de Inspeçao de Esgoto 60x60cm - CI (10)
In: TÉRREO
Type - Material: <Unnamed>, Tijolo, Comum, .CONCRETO
Type - Pset_ManufacturerTypeInformation - Manufacturer: -
Pset_DistributionFlowElementCommon - Reference: Caixa de Inspeçao de Esgoto 60x60cm - CI; sets with these values: 2
Name (Caixa em Alvenaria_Rodrigo MEP:Caixa de Inspeçao de Esgoto 60x60cm - CI:...) | Group
7182701 | Esgoto Sanitário 72
7392671 | Esgoto Sanitário 40
7392928 | Esgoto Sanitário 23; Esgoto Sanitário 41
7403525 | Esgoto Sanitário 51; Esgoto Sanitário 21
7404690 | Esgoto Sanitário 78
7411241 | Esgoto Sanitário 73; Esgoto Sanitário 19
7456933 | Esgoto Sanitário 80
7480029 | Esgoto Sanitário 81
7507032 | Esgoto Sanitário 26
7507330 | Esgoto Sanitário 22

# IfcFlowTerminal: Filtro Anaeróbio_Rodrigo MEP:Filtro Anaeróbio, Filtro Anaeróbio_Rodrigo MEP:Filtro Anaeróbio:7495569
In: TÉRREO
Type - Material: <Unnamed>
Pset_DistributionFlowElementCommon - Reference: Filtro Anaeróbio; sets with these values: 2

# IfcFlowTerminal: Fossa Septica_Rodrigo MEP:Fossa Septica, Fossa Septica_Rodrigo MEP:Fossa Septica:7495568
In: TÉRREO
Type - Material: <Unnamed>
Type - Pset_ManufacturerTypeInformation - Manufacturer: Não Listar
Pset_DistributionFlowElementCommon - Reference: Fossa Septica; sets with these values: 2

# IfcFlowTerminal: Hidráulica_Ponto de Utilização_Uso Provável_Rodrigo MEP:Bacia Sanitária com Valvula de Descarga BS (Peso 32) (5)
In: TÉRREO
Type - Material: <Unnamed>
Type - Pset_ManufacturerTypeInformation - Manufacturer: Não Listar
Pset_DistributionFlowElementCommon - Reference: Bacia Sanitária com Valvula de Descarga BS (Peso 32); sets with these values: 2
Name (Hidráulica_Ponto de Utilização_Uso Provável_Rodrigo MEP:Bacia Sanitária com Valvula de Descarga BS (Peso 32):...) | Group
7293043 | Água Fria - Extravasor e Limpeza 1
7380749 | Água Fria - Extravasor e Limpeza 1
7380830 | Água Fria 1
7380996 | Água Fria 9
7385497 | Água Fria - Extravasor e Limpeza 1

# IfcFlowTerminal: Hidráulica_Ponto de Utilização_Uso Provável_Rodrigo MEP:Bebedouro BE (Peso 0,1), Hidráulica_Ponto de Utilização_Uso Provável_Rodrigo MEP:Bebedouro BE (Peso 0,1):7385352
In: TÉRREO
Type - Material: <Unnamed>
Type - Pset_ManufacturerTypeInformation - Manufacturer: Não Listar
Pset_DistributionFlowElementCommon - Reference: Bebedouro BE (Peso 0,1); sets with these values: 2
Group: Água Fria 1

# IfcFlowTerminal: Hidráulica_Ponto de Utilização_Uso Provável_Rodrigo MEP:Chuveiro Elétrico CH (Peso 0,1) (2)
In: TÉRREO
Type - Material: <Unnamed>
Type - Pset_ManufacturerTypeInformation - Manufacturer: Não Listar
Pset_DistributionFlowElementCommon - Reference: Chuveiro Elétrico CH (Peso 0,1); sets with these values: 2
Group: Água Fria - Extravasor e Limpeza 1
Name (Hidráulica_Ponto de Utilização_Uso Provável_Rodrigo MEP:Chuveiro Elétrico CH (Peso 0,1):...)
7031165
7385545

# IfcFlowTerminal: Hidráulica_Ponto de Utilização_Uso Provável_Rodrigo MEP:EXPURGO, Hidráulica_Ponto de Utilização_Uso Provável_Rodrigo MEP:EXPURGO:7032948
In: TÉRREO
Type - Material: <Unnamed>
Type - Pset_ManufacturerTypeInformation - Manufacturer: Não Listar
Pset_DistributionFlowElementCommon - Reference: EXPURGO; sets with these values: 2
Group: Água Fria - Extravasor e Limpeza 1

# IfcFlowTerminal: Hidráulica_Ponto de Utilização_Uso Provável_Rodrigo MEP:Lavatório LV (Peso 0,3) 60cm do Piso (16)
In: TÉRREO
Type - Material: <Unnamed>
Type - Pset_ManufacturerTypeInformation - Manufacturer: Não Listar
Pset_DistributionFlowElementCommon - Reference: Lavatório LV (Peso 0,3) 60cm do Piso; sets with these values: 2
Name (Hidráulica_Ponto de Utilização_Uso Provável_Rodrigo MEP:Lavatório LV (Peso 0,3) 60cm do Piso:...) | Group
7034796 | Água Fria - Extravasor e Limpeza 1
7380750 | Água Fria - Extravasor e Limpeza 1
7380831 | Água Fria 1
7380997 | Água Fria 9
7382303 | Água Fria - Extravasor e Limpeza 1
7382590 | Água Fria - Extravasor e Limpeza 1
7383279 | Água Fria - Extravasor e Limpeza 1
7383580 | Água Fria - Extravasor e Limpeza 1
7383633 | Água Fria - Extravasor e Limpeza 1
7383762 | Água Fria 9
7384378 | Água Fria 9
7384567 | Água Fria 9
7385013 | Água Fria 1
7385173 | Água Fria 1
7385492 | Água Fria - Extravasor e Limpeza 1
7487072 | Água Fria - Extravasor e Limpeza 1

# IfcFlowTerminal: Hidráulica_Ponto de Utilização_Uso Provável_Rodrigo MEP:Pia com torneira Elétrica (Peso 0,1) 60cm do Piso (2)
In: TÉRREO
Type - Material: <Unnamed>
Type - Pset_ManufacturerTypeInformation - Manufacturer: Não Listar
Pset_DistributionFlowElementCommon - Reference: Pia com torneira Elétrica (Peso 0,1) 60cm do Piso; sets with these values: 2
Group: Água Fria - Extravasor e Limpeza 1
Name (Hidráulica_Ponto de Utilização_Uso Provável_Rodrigo MEP:Pia com torneira Elétrica (Peso 0,1) 60cm do Piso:...)
7382800
7487071

# IfcFlowTerminal: Hidráulica_Ponto de Utilização_Uso Provável_Rodrigo MEP:Pia com torneira ou misturador(Peso 0,7) (8)
In: TÉRREO
Type - Material: <Unnamed>
Type - Pset_ManufacturerTypeInformation - Manufacturer: Não Listar
Pset_DistributionFlowElementCommon - Reference: Pia com torneira ou misturador(Peso 0,7); sets with these values: 2
Name (Hidráulica_Ponto de Utilização_Uso Provável_Rodrigo MEP:Pia com torneira ou misturador(Peso 0,7):...) | Group
7383280 | Água Fria - Extravasor e Limpeza 1
7383763 | Água Fria 9
7384379 | Água Fria 9
7385301 | Água Fria - Extravasor e Limpeza 1
7446299 | Água Fria - Extravasor e Limpeza 1
7446353 | Água Fria - Extravasor e Limpeza 1
7446363 | Água Fria - Extravasor e Limpeza 1
7487088 | Água Fria - Extravasor e Limpeza 1

# IfcFlowTerminal: Hidráulica_Ponto de Utilização_Uso Provável_Rodrigo MEP:Tanque TN (Peso 0,7) 1,2m do Piso, Hidráulica_Ponto de Utilização_Uso Provável_Rodrigo MEP:Tanque TN (Peso 0,7) 1,2m do Piso:7382155
In: TÉRREO
Type - Material: <Unnamed>
Type - Pset_ManufacturerTypeInformation - Manufacturer: Não Listar
Pset_DistributionFlowElementCommon - Reference: Tanque TN (Peso 0,7) 1,2m do Piso; sets with these values: 2
Group: Água Fria - Extravasor e Limpeza 1

# IfcFlowTerminal: Hidráulica_Ponto de Utilização_Uso Provável_Rodrigo MEP:Torneira de Jardim TJ (Peso 0,4) 0,5m do Piso (2)
In: TÉRREO
Type - Material: <Unnamed>
Type - Pset_ManufacturerTypeInformation - Manufacturer: Não Listar
Pset_DistributionFlowElementCommon - Reference: Torneira de Jardim TJ (Peso 0,4) 0,5m do Piso; sets with these values: 2
Name (Hidráulica_Ponto de Utilização_Uso Provável_Rodrigo MEP:Torneira de Jardim TJ (Peso 0,4) 0,5m do Piso:...) | Group
7485732 | Água Fria - Extravasor e Limpeza 1; Água Fria 3
7485761 | Água Fria - Extravasor e Limpeza 1; Água Fria 4

# IfcFlowTerminal: PLUV_Grelha Ralo Hemisférico_Abacaxi:Grelha Abacaxi (18)
In: DRENAGEM PLUVIAL - PLANTA DE COBERTURA
Type - Material: Ferro forjado
Type - Pset_ManufacturerTypeInformation - Manufacturer: Moldada In Loco
Pset_DistributionFlowElementCommon - Reference: Grelha Abacaxi; sets with these values: 2
Name (PLUV_Grelha Ralo Hemisférico_Abacaxi:Grelha Abacaxi:...) | Group
7191267 | Água Pluvial 1
7417940 | Água Pluvial 2
7418821 | Água Pluvial 3
7419043 | Água Pluvial 4
7419067 | Água Pluvial 5
7419107 | Água Pluvial 6
7419506 | Água Pluvial 7
7420570 | Água Pluvial 15
7421403 | Água Pluvial 17
7422311 | Água Pluvial 18
7510373 | Água Pluvial 8
7510388 | Água Pluvial 10
7510403 | Água Pluvial 12
7510418 | Água Pluvial 14
7510433 | Água Pluvial 19
7510448 | Água Pluvial 21
7510463 | Água Pluvial 23
7510478 | Água Pluvial 25

# IfcFlowTerminal: PVC Esgoto_Caixa Sifonada Montada Ø150mm 7 Entradas_Rodrigo MEP:Quadrado Branco 150x150x50mm (6)
In: TÉRREO
Type - Material: Tigre - Caixas e Ralos_PVC Branco
Type - Pset_ManufacturerTypeInformation - Manufacturer: Tigre
Pset_DistributionFlowElementCommon - Reference: Quadrado Branco 150x150x50mm; sets with these values: 2
Name (PVC Esgoto_Caixa Sifonada Montada Ø150mm 7 Entradas_Rodrigo MEP:Quadrado Branco 150x150x50mm:...) | Group
7391159 | Esgoto Sanitário 11; Esgoto Sanitário 10; Água Fria Alimentação 2; Esgoto Sanitário 9; Esgoto Sanitário 8
7400082 | Esgoto Sanitário 30; Esgoto Sanitário 27
7402194 | Esgoto Sanitário 36; Esgoto Sanitário 37; Esgoto Sanitário 38; Esgoto Sanitário 39
7407036 | Esgoto Sanitário 57; Esgoto Sanitário 59; Esgoto Sanitário 58; Esgoto Sanitário 56; Esgoto Sanitário 75
7407902 | Esgoto Sanitário 63; Esgoto Sanitário 64; Esgoto Sanitário 66
7409151 | Esgoto Sanitário 63; Esgoto Sanitário 65; Esgoto Sanitário 68

# IfcFlowTerminal: PVC Esgoto_Caixa Sifonada Ø100mm 3 Entradas_Rodrigo MEP:Branco_Quadrado 100x100x50mm (14)
In: TÉRREO
Type - Material: Tigre - Caixas e Ralos_PVC Branco
Type - Pset_ManufacturerTypeInformation - Manufacturer: Tigre
Pset_DistributionFlowElementCommon - Reference: Branco_Quadrado 100x100x50mm; sets with these values: 2
Name (PVC Esgoto_Caixa Sifonada Ø100mm 3 Entradas_Rodrigo MEP:Branco_Quadrado 100x100x50mm:...) | Group
7029455 | Esgoto Primário 7; Esgoto Primário 8; Esgoto Primário 9
7390557 | Esgoto Sanitário 2; Esgoto Sanitário 3; Esgoto Sanitário 1
7390940 | Esgoto Sanitário 4; Esgoto Sanitário 6; Esgoto Sanitário 5
7392107 | Esgoto Sanitário 14; Esgoto Sanitário 15; Esgoto Sanitário 16
7392994 | Esgoto Sanitário 17; Esgoto Sanitário 20; Esgoto Sanitário 76
7401068 | Esgoto Sanitário 27; Esgoto Sanitário 31
7401928 | Esgoto Sanitário 34; Esgoto Sanitário 33
7403472 | Esgoto Sanitário 42; Esgoto Sanitário 44; Esgoto Sanitário 45
7403859 | Esgoto Sanitário 46; Esgoto Sanitário 43
7403936 | Esgoto Sanitário 43; Esgoto Sanitário 48
7405141 | Esgoto Sanitário 53; Esgoto Sanitário 52
7409821 | Esgoto Sanitário 83; Esgoto Sanitário 85; Esgoto Sanitário 69
7491571 | Esgoto Sanitário 11; Esgoto Sanitário 29
7502677 | Esgoto Sanitário 84; Esgoto Sanitário 60

# IfcFlowTerminal: Ralo Seco Ø100mm_Rodrigo MEP:Branco_Quadrado 100x100x40mm (3)
In: TÉRREO
Type - Material: Tigre - Caixas e Ralos_PVC Branco
Type - Pset_ManufacturerTypeInformation - Manufacturer: Tigre
Pset_DistributionFlowElementCommon - Reference: Branco_Quadrado 100x100x40mm; sets with these values: 2
Name (Ralo Seco Ø100mm_Rodrigo MEP:Branco_Quadrado 100x100x40mm:...) | Group
7390480 | Esgoto Sanitário 2
7392972 | Esgoto Sanitário 79; Esgoto Sanitário 20
7480328 | Esgoto Sanitário 85

# IfcFlowTerminal: Sumidouro_Rodrigo MEP:Sumidouro, Sumidouro_Rodrigo MEP:Sumidouro:7495570
In: TÉRREO
Type - Material: <Unnamed>
Type - Pset_ManufacturerTypeInformation - Manufacturer: Não Listar
Pset_DistributionFlowElementCommon - Reference: Sumidouro; sets with these values: 2

# IfcFlowTerminal: Torneira boia - Fortlev - AleBim:3/4", Torneira boia - Fortlev - AleBim:3/4":7454165
In: TÉRREO
Type - Material: PEMD Azul, Plastic
Type - Pset_ManufacturerTypeInformation - Manufacturer: FortLev
Pset_DistributionFlowElementCommon - Reference: 3/4"; sets with these values: 2

# IfcSlab: Piso:Generic 200mm, Piso:Generic 200mm:7227686
In: DRENAGEM PLUVIAL - PLANTA DE COBERTURA
Type - PredefinedType: FLOOR; Material: <Unnamed> 200 mm
Type - Pset_SlabCommon - IsExternal: no
Pset_QuantityTakeOff - Reference: Generic 200mm; sets with these values: 2
Pset_SlabCommon - Reference: Generic 200mm; LoadBearing: no; PitchAngle: 0 deg
